# Generated by FakeRAM 2.0
VERSION 5.7 ;
BUSBITCHARS "[]" ;
PROPERTYDEFINITIONS
  MACRO width INTEGER ;
  MACRO depth INTEGER ;
  MACRO banks INTEGER ;
END PROPERTYDEFINITIONS
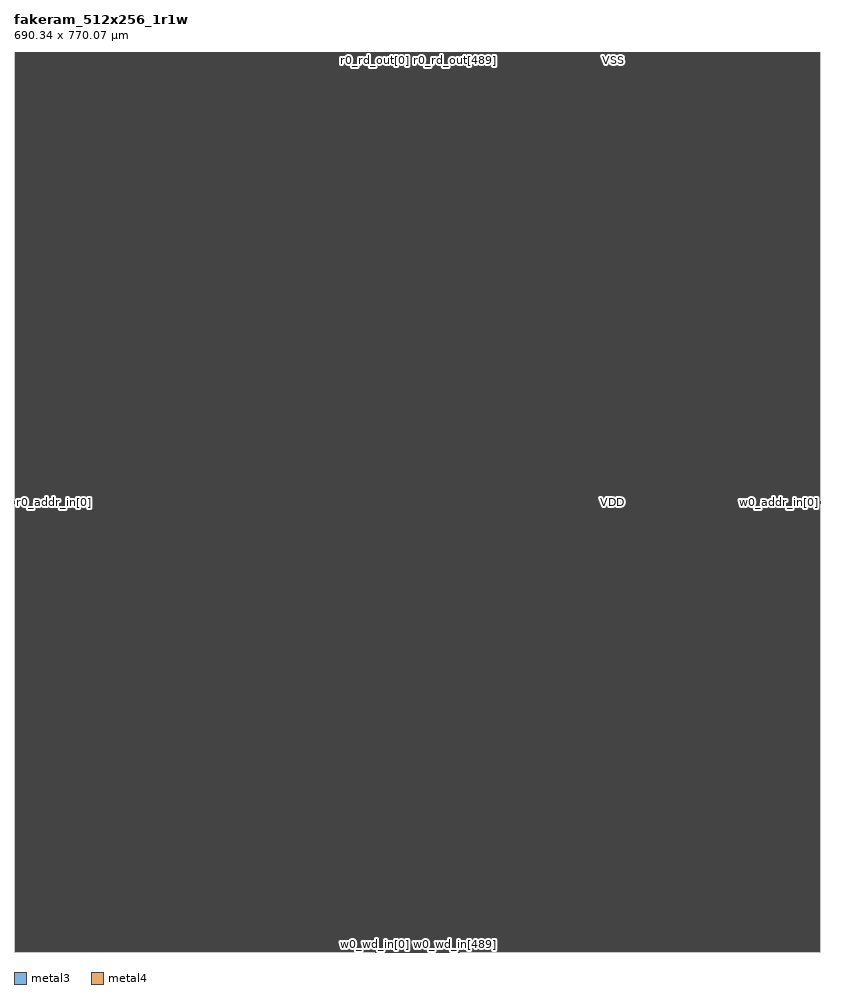
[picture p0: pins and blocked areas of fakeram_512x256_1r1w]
MACRO fakeram_512x256_1r1w
  PROPERTY width 512 ;
  PROPERTY depth 256 ;
  PROPERTY banks 1 ;
  FOREIGN fakeram_512x256_1r1w 0 0 ;
  SYMMETRY X Y R90 ;
  SIZE 690.340 BY 770.070 ;
  CLASS BLOCK ;
  PIN r0_addr_in[0]
    DIRECTION INPUT ;
    USE SIGNAL ;
    SHAPE ABUTMENT ;
    PORT
      LAYER metal3 ;
      RECT 0.000 384.160 0.070 384.230 ;
    END
  END r0_addr_in[0]
  PIN r0_addr_in[1]
    DIRECTION INPUT ;
    USE SIGNAL ;
    SHAPE ABUTMENT ;
    PORT
      LAYER metal3 ;
      RECT 0.000 384.300 0.070 384.370 ;
    END
  END r0_addr_in[1]
  PIN r0_addr_in[2]
    DIRECTION INPUT ;
    USE SIGNAL ;
    SHAPE ABUTMENT ;
    PORT
      LAYER metal3 ;
      RECT 0.000 384.440 0.070 384.510 ;
    END
  END r0_addr_in[2]
  PIN r0_addr_in[3]
    DIRECTION INPUT ;
    USE SIGNAL ;
    SHAPE ABUTMENT ;
    PORT
      LAYER metal3 ;
      RECT 0.000 384.580 0.070 384.650 ;
    END
  END r0_addr_in[3]
  PIN r0_addr_in[4]
    DIRECTION INPUT ;
    USE SIGNAL ;
    SHAPE ABUTMENT ;
    PORT
      LAYER metal3 ;
      RECT 0.000 384.720 0.070 384.790 ;
    END
  END r0_addr_in[4]
  PIN r0_addr_in[5]
    DIRECTION INPUT ;
    USE SIGNAL ;
    SHAPE ABUTMENT ;
    PORT
      LAYER metal3 ;
      RECT 0.000 384.860 0.070 384.930 ;
    END
  END r0_addr_in[5]
  PIN r0_addr_in[6]
    DIRECTION INPUT ;
    USE SIGNAL ;
    SHAPE ABUTMENT ;
    PORT
      LAYER metal3 ;
      RECT 0.000 385.000 0.070 385.070 ;
    END
  END r0_addr_in[6]
  PIN r0_addr_in[7]
    DIRECTION INPUT ;
    USE SIGNAL ;
    SHAPE ABUTMENT ;
    PORT
      LAYER metal3 ;
      RECT 0.000 385.140 0.070 385.210 ;
    END
  END r0_addr_in[7]
  PIN r0_ce_in
    DIRECTION INPUT ;
    USE SIGNAL ;
    SHAPE ABUTMENT ;
    PORT
      LAYER metal3 ;
      RECT 0.000 385.420 0.070 385.490 ;
    END
  END r0_ce_in
  PIN r0_clk
    DIRECTION INPUT ;
    USE SIGNAL ;
    SHAPE ABUTMENT ;
    PORT
      LAYER metal3 ;
      RECT 0.000 385.560 0.070 385.630 ;
    END
  END r0_clk
  PIN r0_rd_out[0]
    DIRECTION OUTPUT ;
    USE SIGNAL ;
    SHAPE ABUTMENT ;
    PORT
      LAYER metal3 ;
      RECT 309.225 770.000 309.295 770.070 ;
    END
  END r0_rd_out[0]
  PIN r0_rd_out[1]
    DIRECTION OUTPUT ;
    USE SIGNAL ;
    SHAPE ABUTMENT ;
    PORT
      LAYER metal3 ;
      RECT 309.365 770.000 309.435 770.070 ;
    END
  END r0_rd_out[1]
  PIN r0_rd_out[2]
    DIRECTION OUTPUT ;
    USE SIGNAL ;
    SHAPE ABUTMENT ;
    PORT
      LAYER metal3 ;
      RECT 309.505 770.000 309.575 770.070 ;
    END
  END r0_rd_out[2]
  PIN r0_rd_out[3]
    DIRECTION OUTPUT ;
    USE SIGNAL ;
    SHAPE ABUTMENT ;
    PORT
      LAYER metal3 ;
      RECT 309.645 770.000 309.715 770.070 ;
    END
  END r0_rd_out[3]
  PIN r0_rd_out[4]
    DIRECTION OUTPUT ;
    USE SIGNAL ;
    SHAPE ABUTMENT ;
    PORT
      LAYER metal3 ;
      RECT 309.785 770.000 309.855 770.070 ;
    END
  END r0_rd_out[4]
  PIN r0_rd_out[5]
    DIRECTION OUTPUT ;
    USE SIGNAL ;
    SHAPE ABUTMENT ;
    PORT
      LAYER metal3 ;
      RECT 309.925 770.000 309.995 770.070 ;
    END
  END r0_rd_out[5]
  PIN r0_rd_out[6]
    DIRECTION OUTPUT ;
    USE SIGNAL ;
    SHAPE ABUTMENT ;
    PORT
      LAYER metal3 ;
      RECT 310.065 770.000 310.135 770.070 ;
    END
  END r0_rd_out[6]
  PIN r0_rd_out[7]
    DIRECTION OUTPUT ;
    USE SIGNAL ;
    SHAPE ABUTMENT ;
    PORT
      LAYER metal3 ;
      RECT 310.205 770.000 310.275 770.070 ;
    END
  END r0_rd_out[7]
  PIN r0_rd_out[8]
    DIRECTION OUTPUT ;
    USE SIGNAL ;
    SHAPE ABUTMENT ;
    PORT
      LAYER metal3 ;
      RECT 310.345 770.000 310.415 770.070 ;
    END
  END r0_rd_out[8]
  PIN r0_rd_out[9]
    DIRECTION OUTPUT ;
    USE SIGNAL ;
    SHAPE ABUTMENT ;
    PORT
      LAYER metal3 ;
      RECT 310.485 770.000 310.555 770.070 ;
    END
  END r0_rd_out[9]
  PIN r0_rd_out[10]
    DIRECTION OUTPUT ;
    USE SIGNAL ;
    SHAPE ABUTMENT ;
    PORT
      LAYER metal3 ;
      RECT 310.625 770.000 310.695 770.070 ;
    END
  END r0_rd_out[10]
  PIN r0_rd_out[11]
    DIRECTION OUTPUT ;
    USE SIGNAL ;
    SHAPE ABUTMENT ;
    PORT
      LAYER metal3 ;
      RECT 310.765 770.000 310.835 770.070 ;
    END
  END r0_rd_out[11]
  PIN r0_rd_out[12]
    DIRECTION OUTPUT ;
    USE SIGNAL ;
    SHAPE ABUTMENT ;
    PORT
      LAYER metal3 ;
      RECT 310.905 770.000 310.975 770.070 ;
    END
  END r0_rd_out[12]
  PIN r0_rd_out[13]
    DIRECTION OUTPUT ;
    USE SIGNAL ;
    SHAPE ABUTMENT ;
    PORT
      LAYER metal3 ;
      RECT 311.045 770.000 311.115 770.070 ;
    END
  END r0_rd_out[13]
  PIN r0_rd_out[14]
    DIRECTION OUTPUT ;
    USE SIGNAL ;
    SHAPE ABUTMENT ;
    PORT
      LAYER metal3 ;
      RECT 311.185 770.000 311.255 770.070 ;
    END
  END r0_rd_out[14]
  PIN r0_rd_out[15]
    DIRECTION OUTPUT ;
    USE SIGNAL ;
    SHAPE ABUTMENT ;
    PORT
      LAYER metal3 ;
      RECT 311.325 770.000 311.395 770.070 ;
    END
  END r0_rd_out[15]
  PIN r0_rd_out[16]
    DIRECTION OUTPUT ;
    USE SIGNAL ;
    SHAPE ABUTMENT ;
    PORT
      LAYER metal3 ;
      RECT 311.465 770.000 311.535 770.070 ;
    END
  END r0_rd_out[16]
  PIN r0_rd_out[17]
    DIRECTION OUTPUT ;
    USE SIGNAL ;
    SHAPE ABUTMENT ;
    PORT
      LAYER metal3 ;
      RECT 311.605 770.000 311.675 770.070 ;
    END
  END r0_rd_out[17]
  PIN r0_rd_out[18]
    DIRECTION OUTPUT ;
    USE SIGNAL ;
    SHAPE ABUTMENT ;
    PORT
      LAYER metal3 ;
      RECT 311.745 770.000 311.815 770.070 ;
    END
  END r0_rd_out[18]
  PIN r0_rd_out[19]
    DIRECTION OUTPUT ;
    USE SIGNAL ;
    SHAPE ABUTMENT ;
    PORT
      LAYER metal3 ;
      RECT 311.885 770.000 311.955 770.070 ;
    END
  END r0_rd_out[19]
  PIN r0_rd_out[20]
    DIRECTION OUTPUT ;
    USE SIGNAL ;
    SHAPE ABUTMENT ;
    PORT
      LAYER metal3 ;
      RECT 312.025 770.000 312.095 770.070 ;
    END
  END r0_rd_out[20]
  PIN r0_rd_out[21]
    DIRECTION OUTPUT ;
    USE SIGNAL ;
    SHAPE ABUTMENT ;
    PORT
      LAYER metal3 ;
      RECT 312.165 770.000 312.235 770.070 ;
    END
  END r0_rd_out[21]
  PIN r0_rd_out[22]
    DIRECTION OUTPUT ;
    USE SIGNAL ;
    SHAPE ABUTMENT ;
    PORT
      LAYER metal3 ;
      RECT 312.305 770.000 312.375 770.070 ;
    END
  END r0_rd_out[22]
  PIN r0_rd_out[23]
    DIRECTION OUTPUT ;
    USE SIGNAL ;
    SHAPE ABUTMENT ;
    PORT
      LAYER metal3 ;
      RECT 312.445 770.000 312.515 770.070 ;
    END
  END r0_rd_out[23]
  PIN r0_rd_out[24]
    DIRECTION OUTPUT ;
    USE SIGNAL ;
    SHAPE ABUTMENT ;
    PORT
      LAYER metal3 ;
      RECT 312.585 770.000 312.655 770.070 ;
    END
  END r0_rd_out[24]
  PIN r0_rd_out[25]
    DIRECTION OUTPUT ;
    USE SIGNAL ;
    SHAPE ABUTMENT ;
    PORT
      LAYER metal3 ;
      RECT 312.725 770.000 312.795 770.070 ;
    END
  END r0_rd_out[25]
  PIN r0_rd_out[26]
    DIRECTION OUTPUT ;
    USE SIGNAL ;
    SHAPE ABUTMENT ;
    PORT
      LAYER metal3 ;
      RECT 312.865 770.000 312.935 770.070 ;
    END
  END r0_rd_out[26]
  PIN r0_rd_out[27]
    DIRECTION OUTPUT ;
    USE SIGNAL ;
    SHAPE ABUTMENT ;
    PORT
      LAYER metal3 ;
      RECT 313.005 770.000 313.075 770.070 ;
    END
  END r0_rd_out[27]
  PIN r0_rd_out[28]
    DIRECTION OUTPUT ;
    USE SIGNAL ;
    SHAPE ABUTMENT ;
    PORT
      LAYER metal3 ;
      RECT 313.145 770.000 313.215 770.070 ;
    END
  END r0_rd_out[28]
  PIN r0_rd_out[29]
    DIRECTION OUTPUT ;
    USE SIGNAL ;
    SHAPE ABUTMENT ;
    PORT
      LAYER metal3 ;
      RECT 313.285 770.000 313.355 770.070 ;
    END
  END r0_rd_out[29]
  PIN r0_rd_out[30]
    DIRECTION OUTPUT ;
    USE SIGNAL ;
    SHAPE ABUTMENT ;
    PORT
      LAYER metal3 ;
      RECT 313.425 770.000 313.495 770.070 ;
    END
  END r0_rd_out[30]
  PIN r0_rd_out[31]
    DIRECTION OUTPUT ;
    USE SIGNAL ;
    SHAPE ABUTMENT ;
    PORT
      LAYER metal3 ;
      RECT 313.565 770.000 313.635 770.070 ;
    END
  END r0_rd_out[31]
  PIN r0_rd_out[32]
    DIRECTION OUTPUT ;
    USE SIGNAL ;
    SHAPE ABUTMENT ;
    PORT
      LAYER metal3 ;
      RECT 313.705 770.000 313.775 770.070 ;
    END
  END r0_rd_out[32]
  PIN r0_rd_out[33]
    DIRECTION OUTPUT ;
    USE SIGNAL ;
    SHAPE ABUTMENT ;
    PORT
      LAYER metal3 ;
      RECT 313.845 770.000 313.915 770.070 ;
    END
  END r0_rd_out[33]
  PIN r0_rd_out[34]
    DIRECTION OUTPUT ;
    USE SIGNAL ;
    SHAPE ABUTMENT ;
    PORT
      LAYER metal3 ;
      RECT 313.985 770.000 314.055 770.070 ;
    END
  END r0_rd_out[34]
  PIN r0_rd_out[35]
    DIRECTION OUTPUT ;
    USE SIGNAL ;
    SHAPE ABUTMENT ;
    PORT
      LAYER metal3 ;
      RECT 314.125 770.000 314.195 770.070 ;
    END
  END r0_rd_out[35]
  PIN r0_rd_out[36]
    DIRECTION OUTPUT ;
    USE SIGNAL ;
    SHAPE ABUTMENT ;
    PORT
      LAYER metal3 ;
      RECT 314.265 770.000 314.335 770.070 ;
    END
  END r0_rd_out[36]
  PIN r0_rd_out[37]
    DIRECTION OUTPUT ;
    USE SIGNAL ;
    SHAPE ABUTMENT ;
    PORT
      LAYER metal3 ;
      RECT 314.405 770.000 314.475 770.070 ;
    END
  END r0_rd_out[37]
  PIN r0_rd_out[38]
    DIRECTION OUTPUT ;
    USE SIGNAL ;
    SHAPE ABUTMENT ;
    PORT
      LAYER metal3 ;
      RECT 314.545 770.000 314.615 770.070 ;
    END
  END r0_rd_out[38]
  PIN r0_rd_out[39]
    DIRECTION OUTPUT ;
    USE SIGNAL ;
    SHAPE ABUTMENT ;
    PORT
      LAYER metal3 ;
      RECT 314.685 770.000 314.755 770.070 ;
    END
  END r0_rd_out[39]
  PIN r0_rd_out[40]
    DIRECTION OUTPUT ;
    USE SIGNAL ;
    SHAPE ABUTMENT ;
    PORT
      LAYER metal3 ;
      RECT 314.825 770.000 314.895 770.070 ;
    END
  END r0_rd_out[40]
  PIN r0_rd_out[41]
    DIRECTION OUTPUT ;
    USE SIGNAL ;
    SHAPE ABUTMENT ;
    PORT
      LAYER metal3 ;
      RECT 314.965 770.000 315.035 770.070 ;
    END
  END r0_rd_out[41]
  PIN r0_rd_out[42]
    DIRECTION OUTPUT ;
    USE SIGNAL ;
    SHAPE ABUTMENT ;
    PORT
      LAYER metal3 ;
      RECT 315.105 770.000 315.175 770.070 ;
    END
  END r0_rd_out[42]
  PIN r0_rd_out[43]
    DIRECTION OUTPUT ;
    USE SIGNAL ;
    SHAPE ABUTMENT ;
    PORT
      LAYER metal3 ;
      RECT 315.245 770.000 315.315 770.070 ;
    END
  END r0_rd_out[43]
  PIN r0_rd_out[44]
    DIRECTION OUTPUT ;
    USE SIGNAL ;
    SHAPE ABUTMENT ;
    PORT
      LAYER metal3 ;
      RECT 315.385 770.000 315.455 770.070 ;
    END
  END r0_rd_out[44]
  PIN r0_rd_out[45]
    DIRECTION OUTPUT ;
    USE SIGNAL ;
    SHAPE ABUTMENT ;
    PORT
      LAYER metal3 ;
      RECT 315.525 770.000 315.595 770.070 ;
    END
  END r0_rd_out[45]
  PIN r0_rd_out[46]
    DIRECTION OUTPUT ;
    USE SIGNAL ;
    SHAPE ABUTMENT ;
    PORT
      LAYER metal3 ;
      RECT 315.665 770.000 315.735 770.070 ;
    END
  END r0_rd_out[46]
  PIN r0_rd_out[47]
    DIRECTION OUTPUT ;
    USE SIGNAL ;
    SHAPE ABUTMENT ;
    PORT
      LAYER metal3 ;
      RECT 315.805 770.000 315.875 770.070 ;
    END
  END r0_rd_out[47]
  PIN r0_rd_out[48]
    DIRECTION OUTPUT ;
    USE SIGNAL ;
    SHAPE ABUTMENT ;
    PORT
      LAYER metal3 ;
      RECT 315.945 770.000 316.015 770.070 ;
    END
  END r0_rd_out[48]
  PIN r0_rd_out[49]
    DIRECTION OUTPUT ;
    USE SIGNAL ;
    SHAPE ABUTMENT ;
    PORT
      LAYER metal3 ;
      RECT 316.085 770.000 316.155 770.070 ;
    END
  END r0_rd_out[49]
  PIN r0_rd_out[50]
    DIRECTION OUTPUT ;
    USE SIGNAL ;
    SHAPE ABUTMENT ;
    PORT
      LAYER metal3 ;
      RECT 316.225 770.000 316.295 770.070 ;
    END
  END r0_rd_out[50]
  PIN r0_rd_out[51]
    DIRECTION OUTPUT ;
    USE SIGNAL ;
    SHAPE ABUTMENT ;
    PORT
      LAYER metal3 ;
      RECT 316.365 770.000 316.435 770.070 ;
    END
  END r0_rd_out[51]
  PIN r0_rd_out[52]
    DIRECTION OUTPUT ;
    USE SIGNAL ;
    SHAPE ABUTMENT ;
    PORT
      LAYER metal3 ;
      RECT 316.505 770.000 316.575 770.070 ;
    END
  END r0_rd_out[52]
  PIN r0_rd_out[53]
    DIRECTION OUTPUT ;
    USE SIGNAL ;
    SHAPE ABUTMENT ;
    PORT
      LAYER metal3 ;
      RECT 316.645 770.000 316.715 770.070 ;
    END
  END r0_rd_out[53]
  PIN r0_rd_out[54]
    DIRECTION OUTPUT ;
    USE SIGNAL ;
    SHAPE ABUTMENT ;
    PORT
      LAYER metal3 ;
      RECT 316.785 770.000 316.855 770.070 ;
    END
  END r0_rd_out[54]
  PIN r0_rd_out[55]
    DIRECTION OUTPUT ;
    USE SIGNAL ;
    SHAPE ABUTMENT ;
    PORT
      LAYER metal3 ;
      RECT 316.925 770.000 316.995 770.070 ;
    END
  END r0_rd_out[55]
  PIN r0_rd_out[56]
    DIRECTION OUTPUT ;
    USE SIGNAL ;
    SHAPE ABUTMENT ;
    PORT
      LAYER metal3 ;
      RECT 317.065 770.000 317.135 770.070 ;
    END
  END r0_rd_out[56]
  PIN r0_rd_out[57]
    DIRECTION OUTPUT ;
    USE SIGNAL ;
    SHAPE ABUTMENT ;
    PORT
      LAYER metal3 ;
      RECT 317.205 770.000 317.275 770.070 ;
    END
  END r0_rd_out[57]
  PIN r0_rd_out[58]
    DIRECTION OUTPUT ;
    USE SIGNAL ;
    SHAPE ABUTMENT ;
    PORT
      LAYER metal3 ;
      RECT 317.345 770.000 317.415 770.070 ;
    END
  END r0_rd_out[58]
  PIN r0_rd_out[59]
    DIRECTION OUTPUT ;
    USE SIGNAL ;
    SHAPE ABUTMENT ;
    PORT
      LAYER metal3 ;
      RECT 317.485 770.000 317.555 770.070 ;
    END
  END r0_rd_out[59]
  PIN r0_rd_out[60]
    DIRECTION OUTPUT ;
    USE SIGNAL ;
    SHAPE ABUTMENT ;
    PORT
      LAYER metal3 ;
      RECT 317.625 770.000 317.695 770.070 ;
    END
  END r0_rd_out[60]
  PIN r0_rd_out[61]
    DIRECTION OUTPUT ;
    USE SIGNAL ;
    SHAPE ABUTMENT ;
    PORT
      LAYER metal3 ;
      RECT 317.765 770.000 317.835 770.070 ;
    END
  END r0_rd_out[61]
  PIN r0_rd_out[62]
    DIRECTION OUTPUT ;
    USE SIGNAL ;
    SHAPE ABUTMENT ;
    PORT
      LAYER metal3 ;
      RECT 317.905 770.000 317.975 770.070 ;
    END
  END r0_rd_out[62]
  PIN r0_rd_out[63]
    DIRECTION OUTPUT ;
    USE SIGNAL ;
    SHAPE ABUTMENT ;
    PORT
      LAYER metal3 ;
      RECT 318.045 770.000 318.115 770.070 ;
    END
  END r0_rd_out[63]
  PIN r0_rd_out[64]
    DIRECTION OUTPUT ;
    USE SIGNAL ;
    SHAPE ABUTMENT ;
    PORT
      LAYER metal3 ;
      RECT 318.185 770.000 318.255 770.070 ;
    END
  END r0_rd_out[64]
  PIN r0_rd_out[65]
    DIRECTION OUTPUT ;
    USE SIGNAL ;
    SHAPE ABUTMENT ;
    PORT
      LAYER metal3 ;
      RECT 318.325 770.000 318.395 770.070 ;
    END
  END r0_rd_out[65]
  PIN r0_rd_out[66]
    DIRECTION OUTPUT ;
    USE SIGNAL ;
    SHAPE ABUTMENT ;
    PORT
      LAYER metal3 ;
      RECT 318.465 770.000 318.535 770.070 ;
    END
  END r0_rd_out[66]
  PIN r0_rd_out[67]
    DIRECTION OUTPUT ;
    USE SIGNAL ;
    SHAPE ABUTMENT ;
    PORT
      LAYER metal3 ;
      RECT 318.605 770.000 318.675 770.070 ;
    END
  END r0_rd_out[67]
  PIN r0_rd_out[68]
    DIRECTION OUTPUT ;
    USE SIGNAL ;
    SHAPE ABUTMENT ;
    PORT
      LAYER metal3 ;
      RECT 318.745 770.000 318.815 770.070 ;
    END
  END r0_rd_out[68]
  PIN r0_rd_out[69]
    DIRECTION OUTPUT ;
    USE SIGNAL ;
    SHAPE ABUTMENT ;
    PORT
      LAYER metal3 ;
      RECT 318.885 770.000 318.955 770.070 ;
    END
  END r0_rd_out[69]
  PIN r0_rd_out[70]
    DIRECTION OUTPUT ;
    USE SIGNAL ;
    SHAPE ABUTMENT ;
    PORT
      LAYER metal3 ;
      RECT 319.025 770.000 319.095 770.070 ;
    END
  END r0_rd_out[70]
  PIN r0_rd_out[71]
    DIRECTION OUTPUT ;
    USE SIGNAL ;
    SHAPE ABUTMENT ;
    PORT
      LAYER metal3 ;
      RECT 319.165 770.000 319.235 770.070 ;
    END
  END r0_rd_out[71]
  PIN r0_rd_out[72]
    DIRECTION OUTPUT ;
    USE SIGNAL ;
    SHAPE ABUTMENT ;
    PORT
      LAYER metal3 ;
      RECT 319.305 770.000 319.375 770.070 ;
    END
  END r0_rd_out[72]
  PIN r0_rd_out[73]
    DIRECTION OUTPUT ;
    USE SIGNAL ;
    SHAPE ABUTMENT ;
    PORT
      LAYER metal3 ;
      RECT 319.445 770.000 319.515 770.070 ;
    END
  END r0_rd_out[73]
  PIN r0_rd_out[74]
    DIRECTION OUTPUT ;
    USE SIGNAL ;
    SHAPE ABUTMENT ;
    PORT
      LAYER metal3 ;
      RECT 319.585 770.000 319.655 770.070 ;
    END
  END r0_rd_out[74]
  PIN r0_rd_out[75]
    DIRECTION OUTPUT ;
    USE SIGNAL ;
    SHAPE ABUTMENT ;
    PORT
      LAYER metal3 ;
      RECT 319.725 770.000 319.795 770.070 ;
    END
  END r0_rd_out[75]
  PIN r0_rd_out[76]
    DIRECTION OUTPUT ;
    USE SIGNAL ;
    SHAPE ABUTMENT ;
    PORT
      LAYER metal3 ;
      RECT 319.865 770.000 319.935 770.070 ;
    END
  END r0_rd_out[76]
  PIN r0_rd_out[77]
    DIRECTION OUTPUT ;
    USE SIGNAL ;
    SHAPE ABUTMENT ;
    PORT
      LAYER metal3 ;
      RECT 320.005 770.000 320.075 770.070 ;
    END
  END r0_rd_out[77]
  PIN r0_rd_out[78]
    DIRECTION OUTPUT ;
    USE SIGNAL ;
    SHAPE ABUTMENT ;
    PORT
      LAYER metal3 ;
      RECT 320.145 770.000 320.215 770.070 ;
    END
  END r0_rd_out[78]
  PIN r0_rd_out[79]
    DIRECTION OUTPUT ;
    USE SIGNAL ;
    SHAPE ABUTMENT ;
    PORT
      LAYER metal3 ;
      RECT 320.285 770.000 320.355 770.070 ;
    END
  END r0_rd_out[79]
  PIN r0_rd_out[80]
    DIRECTION OUTPUT ;
    USE SIGNAL ;
    SHAPE ABUTMENT ;
    PORT
      LAYER metal3 ;
      RECT 320.425 770.000 320.495 770.070 ;
    END
  END r0_rd_out[80]
  PIN r0_rd_out[81]
    DIRECTION OUTPUT ;
    USE SIGNAL ;
    SHAPE ABUTMENT ;
    PORT
      LAYER metal3 ;
      RECT 320.565 770.000 320.635 770.070 ;
    END
  END r0_rd_out[81]
  PIN r0_rd_out[82]
    DIRECTION OUTPUT ;
    USE SIGNAL ;
    SHAPE ABUTMENT ;
    PORT
      LAYER metal3 ;
      RECT 320.705 770.000 320.775 770.070 ;
    END
  END r0_rd_out[82]
  PIN r0_rd_out[83]
    DIRECTION OUTPUT ;
    USE SIGNAL ;
    SHAPE ABUTMENT ;
    PORT
      LAYER metal3 ;
      RECT 320.845 770.000 320.915 770.070 ;
    END
  END r0_rd_out[83]
  PIN r0_rd_out[84]
    DIRECTION OUTPUT ;
    USE SIGNAL ;
    SHAPE ABUTMENT ;
    PORT
      LAYER metal3 ;
      RECT 320.985 770.000 321.055 770.070 ;
    END
  END r0_rd_out[84]
  PIN r0_rd_out[85]
    DIRECTION OUTPUT ;
    USE SIGNAL ;
    SHAPE ABUTMENT ;
    PORT
      LAYER metal3 ;
      RECT 321.125 770.000 321.195 770.070 ;
    END
  END r0_rd_out[85]
  PIN r0_rd_out[86]
    DIRECTION OUTPUT ;
    USE SIGNAL ;
    SHAPE ABUTMENT ;
    PORT
      LAYER metal3 ;
      RECT 321.265 770.000 321.335 770.070 ;
    END
  END r0_rd_out[86]
  PIN r0_rd_out[87]
    DIRECTION OUTPUT ;
    USE SIGNAL ;
    SHAPE ABUTMENT ;
    PORT
      LAYER metal3 ;
      RECT 321.405 770.000 321.475 770.070 ;
    END
  END r0_rd_out[87]
  PIN r0_rd_out[88]
    DIRECTION OUTPUT ;
    USE SIGNAL ;
    SHAPE ABUTMENT ;
    PORT
      LAYER metal3 ;
      RECT 321.545 770.000 321.615 770.070 ;
    END
  END r0_rd_out[88]
  PIN r0_rd_out[89]
    DIRECTION OUTPUT ;
    USE SIGNAL ;
    SHAPE ABUTMENT ;
    PORT
      LAYER metal3 ;
      RECT 321.685 770.000 321.755 770.070 ;
    END
  END r0_rd_out[89]
  PIN r0_rd_out[90]
    DIRECTION OUTPUT ;
    USE SIGNAL ;
    SHAPE ABUTMENT ;
    PORT
      LAYER metal3 ;
      RECT 321.825 770.000 321.895 770.070 ;
    END
  END r0_rd_out[90]
  PIN r0_rd_out[91]
    DIRECTION OUTPUT ;
    USE SIGNAL ;
    SHAPE ABUTMENT ;
    PORT
      LAYER metal3 ;
      RECT 321.965 770.000 322.035 770.070 ;
    END
  END r0_rd_out[91]
  PIN r0_rd_out[92]
    DIRECTION OUTPUT ;
    USE SIGNAL ;
    SHAPE ABUTMENT ;
    PORT
      LAYER metal3 ;
      RECT 322.105 770.000 322.175 770.070 ;
    END
  END r0_rd_out[92]
  PIN r0_rd_out[93]
    DIRECTION OUTPUT ;
    USE SIGNAL ;
    SHAPE ABUTMENT ;
    PORT
      LAYER metal3 ;
      RECT 322.245 770.000 322.315 770.070 ;
    END
  END r0_rd_out[93]
  PIN r0_rd_out[94]
    DIRECTION OUTPUT ;
    USE SIGNAL ;
    SHAPE ABUTMENT ;
    PORT
      LAYER metal3 ;
      RECT 322.385 770.000 322.455 770.070 ;
    END
  END r0_rd_out[94]
  PIN r0_rd_out[95]
    DIRECTION OUTPUT ;
    USE SIGNAL ;
    SHAPE ABUTMENT ;
    PORT
      LAYER metal3 ;
      RECT 322.525 770.000 322.595 770.070 ;
    END
  END r0_rd_out[95]
  PIN r0_rd_out[96]
    DIRECTION OUTPUT ;
    USE SIGNAL ;
    SHAPE ABUTMENT ;
    PORT
      LAYER metal3 ;
      RECT 322.665 770.000 322.735 770.070 ;
    END
  END r0_rd_out[96]
  PIN r0_rd_out[97]
    DIRECTION OUTPUT ;
    USE SIGNAL ;
    SHAPE ABUTMENT ;
    PORT
      LAYER metal3 ;
      RECT 322.805 770.000 322.875 770.070 ;
    END
  END r0_rd_out[97]
  PIN r0_rd_out[98]
    DIRECTION OUTPUT ;
    USE SIGNAL ;
    SHAPE ABUTMENT ;
    PORT
      LAYER metal3 ;
      RECT 322.945 770.000 323.015 770.070 ;
    END
  END r0_rd_out[98]
  PIN r0_rd_out[99]
    DIRECTION OUTPUT ;
    USE SIGNAL ;
    SHAPE ABUTMENT ;
    PORT
      LAYER metal3 ;
      RECT 323.085 770.000 323.155 770.070 ;
    END
  END r0_rd_out[99]
  PIN r0_rd_out[100]
    DIRECTION OUTPUT ;
    USE SIGNAL ;
    SHAPE ABUTMENT ;
    PORT
      LAYER metal3 ;
      RECT 323.225 770.000 323.295 770.070 ;
    END
  END r0_rd_out[100]
  PIN r0_rd_out[101]
    DIRECTION OUTPUT ;
    USE SIGNAL ;
    SHAPE ABUTMENT ;
    PORT
      LAYER metal3 ;
      RECT 323.365 770.000 323.435 770.070 ;
    END
  END r0_rd_out[101]
  PIN r0_rd_out[102]
    DIRECTION OUTPUT ;
    USE SIGNAL ;
    SHAPE ABUTMENT ;
    PORT
      LAYER metal3 ;
      RECT 323.505 770.000 323.575 770.070 ;
    END
  END r0_rd_out[102]
  PIN r0_rd_out[103]
    DIRECTION OUTPUT ;
    USE SIGNAL ;
    SHAPE ABUTMENT ;
    PORT
      LAYER metal3 ;
      RECT 323.645 770.000 323.715 770.070 ;
    END
  END r0_rd_out[103]
  PIN r0_rd_out[104]
    DIRECTION OUTPUT ;
    USE SIGNAL ;
    SHAPE ABUTMENT ;
    PORT
      LAYER metal3 ;
      RECT 323.785 770.000 323.855 770.070 ;
    END
  END r0_rd_out[104]
  PIN r0_rd_out[105]
    DIRECTION OUTPUT ;
    USE SIGNAL ;
    SHAPE ABUTMENT ;
    PORT
      LAYER metal3 ;
      RECT 323.925 770.000 323.995 770.070 ;
    END
  END r0_rd_out[105]
  PIN r0_rd_out[106]
    DIRECTION OUTPUT ;
    USE SIGNAL ;
    SHAPE ABUTMENT ;
    PORT
      LAYER metal3 ;
      RECT 324.065 770.000 324.135 770.070 ;
    END
  END r0_rd_out[106]
  PIN r0_rd_out[107]
    DIRECTION OUTPUT ;
    USE SIGNAL ;
    SHAPE ABUTMENT ;
    PORT
      LAYER metal3 ;
      RECT 324.205 770.000 324.275 770.070 ;
    END
  END r0_rd_out[107]
  PIN r0_rd_out[108]
    DIRECTION OUTPUT ;
    USE SIGNAL ;
    SHAPE ABUTMENT ;
    PORT
      LAYER metal3 ;
      RECT 324.345 770.000 324.415 770.070 ;
    END
  END r0_rd_out[108]
  PIN r0_rd_out[109]
    DIRECTION OUTPUT ;
    USE SIGNAL ;
    SHAPE ABUTMENT ;
    PORT
      LAYER metal3 ;
      RECT 324.485 770.000 324.555 770.070 ;
    END
  END r0_rd_out[109]
  PIN r0_rd_out[110]
    DIRECTION OUTPUT ;
    USE SIGNAL ;
    SHAPE ABUTMENT ;
    PORT
      LAYER metal3 ;
      RECT 324.625 770.000 324.695 770.070 ;
    END
  END r0_rd_out[110]
  PIN r0_rd_out[111]
    DIRECTION OUTPUT ;
    USE SIGNAL ;
    SHAPE ABUTMENT ;
    PORT
      LAYER metal3 ;
      RECT 324.765 770.000 324.835 770.070 ;
    END
  END r0_rd_out[111]
  PIN r0_rd_out[112]
    DIRECTION OUTPUT ;
    USE SIGNAL ;
    SHAPE ABUTMENT ;
    PORT
      LAYER metal3 ;
      RECT 324.905 770.000 324.975 770.070 ;
    END
  END r0_rd_out[112]
  PIN r0_rd_out[113]
    DIRECTION OUTPUT ;
    USE SIGNAL ;
    SHAPE ABUTMENT ;
    PORT
      LAYER metal3 ;
      RECT 325.045 770.000 325.115 770.070 ;
    END
  END r0_rd_out[113]
  PIN r0_rd_out[114]
    DIRECTION OUTPUT ;
    USE SIGNAL ;
    SHAPE ABUTMENT ;
    PORT
      LAYER metal3 ;
      RECT 325.185 770.000 325.255 770.070 ;
    END
  END r0_rd_out[114]
  PIN r0_rd_out[115]
    DIRECTION OUTPUT ;
    USE SIGNAL ;
    SHAPE ABUTMENT ;
    PORT
      LAYER metal3 ;
      RECT 325.325 770.000 325.395 770.070 ;
    END
  END r0_rd_out[115]
  PIN r0_rd_out[116]
    DIRECTION OUTPUT ;
    USE SIGNAL ;
    SHAPE ABUTMENT ;
    PORT
      LAYER metal3 ;
      RECT 325.465 770.000 325.535 770.070 ;
    END
  END r0_rd_out[116]
  PIN r0_rd_out[117]
    DIRECTION OUTPUT ;
    USE SIGNAL ;
    SHAPE ABUTMENT ;
    PORT
      LAYER metal3 ;
      RECT 325.605 770.000 325.675 770.070 ;
    END
  END r0_rd_out[117]
  PIN r0_rd_out[118]
    DIRECTION OUTPUT ;
    USE SIGNAL ;
    SHAPE ABUTMENT ;
    PORT
      LAYER metal3 ;
      RECT 325.745 770.000 325.815 770.070 ;
    END
  END r0_rd_out[118]
  PIN r0_rd_out[119]
    DIRECTION OUTPUT ;
    USE SIGNAL ;
    SHAPE ABUTMENT ;
    PORT
      LAYER metal3 ;
      RECT 325.885 770.000 325.955 770.070 ;
    END
  END r0_rd_out[119]
  PIN r0_rd_out[120]
    DIRECTION OUTPUT ;
    USE SIGNAL ;
    SHAPE ABUTMENT ;
    PORT
      LAYER metal3 ;
      RECT 326.025 770.000 326.095 770.070 ;
    END
  END r0_rd_out[120]
  PIN r0_rd_out[121]
    DIRECTION OUTPUT ;
    USE SIGNAL ;
    SHAPE ABUTMENT ;
    PORT
      LAYER metal3 ;
      RECT 326.165 770.000 326.235 770.070 ;
    END
  END r0_rd_out[121]
  PIN r0_rd_out[122]
    DIRECTION OUTPUT ;
    USE SIGNAL ;
    SHAPE ABUTMENT ;
    PORT
      LAYER metal3 ;
      RECT 326.305 770.000 326.375 770.070 ;
    END
  END r0_rd_out[122]
  PIN r0_rd_out[123]
    DIRECTION OUTPUT ;
    USE SIGNAL ;
    SHAPE ABUTMENT ;
    PORT
      LAYER metal3 ;
      RECT 326.445 770.000 326.515 770.070 ;
    END
  END r0_rd_out[123]
  PIN r0_rd_out[124]
    DIRECTION OUTPUT ;
    USE SIGNAL ;
    SHAPE ABUTMENT ;
    PORT
      LAYER metal3 ;
      RECT 326.585 770.000 326.655 770.070 ;
    END
  END r0_rd_out[124]
  PIN r0_rd_out[125]
    DIRECTION OUTPUT ;
    USE SIGNAL ;
    SHAPE ABUTMENT ;
    PORT
      LAYER metal3 ;
      RECT 326.725 770.000 326.795 770.070 ;
    END
  END r0_rd_out[125]
  PIN r0_rd_out[126]
    DIRECTION OUTPUT ;
    USE SIGNAL ;
    SHAPE ABUTMENT ;
    PORT
      LAYER metal3 ;
      RECT 326.865 770.000 326.935 770.070 ;
    END
  END r0_rd_out[126]
  PIN r0_rd_out[127]
    DIRECTION OUTPUT ;
    USE SIGNAL ;
    SHAPE ABUTMENT ;
    PORT
      LAYER metal3 ;
      RECT 327.005 770.000 327.075 770.070 ;
    END
  END r0_rd_out[127]
  PIN r0_rd_out[128]
    DIRECTION OUTPUT ;
    USE SIGNAL ;
    SHAPE ABUTMENT ;
    PORT
      LAYER metal3 ;
      RECT 327.145 770.000 327.215 770.070 ;
    END
  END r0_rd_out[128]
  PIN r0_rd_out[129]
    DIRECTION OUTPUT ;
    USE SIGNAL ;
    SHAPE ABUTMENT ;
    PORT
      LAYER metal3 ;
      RECT 327.285 770.000 327.355 770.070 ;
    END
  END r0_rd_out[129]
  PIN r0_rd_out[130]
    DIRECTION OUTPUT ;
    USE SIGNAL ;
    SHAPE ABUTMENT ;
    PORT
      LAYER metal3 ;
      RECT 327.425 770.000 327.495 770.070 ;
    END
  END r0_rd_out[130]
  PIN r0_rd_out[131]
    DIRECTION OUTPUT ;
    USE SIGNAL ;
    SHAPE ABUTMENT ;
    PORT
      LAYER metal3 ;
      RECT 327.565 770.000 327.635 770.070 ;
    END
  END r0_rd_out[131]
  PIN r0_rd_out[132]
    DIRECTION OUTPUT ;
    USE SIGNAL ;
    SHAPE ABUTMENT ;
    PORT
      LAYER metal3 ;
      RECT 327.705 770.000 327.775 770.070 ;
    END
  END r0_rd_out[132]
  PIN r0_rd_out[133]
    DIRECTION OUTPUT ;
    USE SIGNAL ;
    SHAPE ABUTMENT ;
    PORT
      LAYER metal3 ;
      RECT 327.845 770.000 327.915 770.070 ;
    END
  END r0_rd_out[133]
  PIN r0_rd_out[134]
    DIRECTION OUTPUT ;
    USE SIGNAL ;
    SHAPE ABUTMENT ;
    PORT
      LAYER metal3 ;
      RECT 327.985 770.000 328.055 770.070 ;
    END
  END r0_rd_out[134]
  PIN r0_rd_out[135]
    DIRECTION OUTPUT ;
    USE SIGNAL ;
    SHAPE ABUTMENT ;
    PORT
      LAYER metal3 ;
      RECT 328.125 770.000 328.195 770.070 ;
    END
  END r0_rd_out[135]
  PIN r0_rd_out[136]
    DIRECTION OUTPUT ;
    USE SIGNAL ;
    SHAPE ABUTMENT ;
    PORT
      LAYER metal3 ;
      RECT 328.265 770.000 328.335 770.070 ;
    END
  END r0_rd_out[136]
  PIN r0_rd_out[137]
    DIRECTION OUTPUT ;
    USE SIGNAL ;
    SHAPE ABUTMENT ;
    PORT
      LAYER metal3 ;
      RECT 328.405 770.000 328.475 770.070 ;
    END
  END r0_rd_out[137]
  PIN r0_rd_out[138]
    DIRECTION OUTPUT ;
    USE SIGNAL ;
    SHAPE ABUTMENT ;
    PORT
      LAYER metal3 ;
      RECT 328.545 770.000 328.615 770.070 ;
    END
  END r0_rd_out[138]
  PIN r0_rd_out[139]
    DIRECTION OUTPUT ;
    USE SIGNAL ;
    SHAPE ABUTMENT ;
    PORT
      LAYER metal3 ;
      RECT 328.685 770.000 328.755 770.070 ;
    END
  END r0_rd_out[139]
  PIN r0_rd_out[140]
    DIRECTION OUTPUT ;
    USE SIGNAL ;
    SHAPE ABUTMENT ;
    PORT
      LAYER metal3 ;
      RECT 328.825 770.000 328.895 770.070 ;
    END
  END r0_rd_out[140]
  PIN r0_rd_out[141]
    DIRECTION OUTPUT ;
    USE SIGNAL ;
    SHAPE ABUTMENT ;
    PORT
      LAYER metal3 ;
      RECT 328.965 770.000 329.035 770.070 ;
    END
  END r0_rd_out[141]
  PIN r0_rd_out[142]
    DIRECTION OUTPUT ;
    USE SIGNAL ;
    SHAPE ABUTMENT ;
    PORT
      LAYER metal3 ;
      RECT 329.105 770.000 329.175 770.070 ;
    END
  END r0_rd_out[142]
  PIN r0_rd_out[143]
    DIRECTION OUTPUT ;
    USE SIGNAL ;
    SHAPE ABUTMENT ;
    PORT
      LAYER metal3 ;
      RECT 329.245 770.000 329.315 770.070 ;
    END
  END r0_rd_out[143]
  PIN r0_rd_out[144]
    DIRECTION OUTPUT ;
    USE SIGNAL ;
    SHAPE ABUTMENT ;
    PORT
      LAYER metal3 ;
      RECT 329.385 770.000 329.455 770.070 ;
    END
  END r0_rd_out[144]
  PIN r0_rd_out[145]
    DIRECTION OUTPUT ;
    USE SIGNAL ;
    SHAPE ABUTMENT ;
    PORT
      LAYER metal3 ;
      RECT 329.525 770.000 329.595 770.070 ;
    END
  END r0_rd_out[145]
  PIN r0_rd_out[146]
    DIRECTION OUTPUT ;
    USE SIGNAL ;
    SHAPE ABUTMENT ;
    PORT
      LAYER metal3 ;
      RECT 329.665 770.000 329.735 770.070 ;
    END
  END r0_rd_out[146]
  PIN r0_rd_out[147]
    DIRECTION OUTPUT ;
    USE SIGNAL ;
    SHAPE ABUTMENT ;
    PORT
      LAYER metal3 ;
      RECT 329.805 770.000 329.875 770.070 ;
    END
  END r0_rd_out[147]
  PIN r0_rd_out[148]
    DIRECTION OUTPUT ;
    USE SIGNAL ;
    SHAPE ABUTMENT ;
    PORT
      LAYER metal3 ;
      RECT 329.945 770.000 330.015 770.070 ;
    END
  END r0_rd_out[148]
  PIN r0_rd_out[149]
    DIRECTION OUTPUT ;
    USE SIGNAL ;
    SHAPE ABUTMENT ;
    PORT
      LAYER metal3 ;
      RECT 330.085 770.000 330.155 770.070 ;
    END
  END r0_rd_out[149]
  PIN r0_rd_out[150]
    DIRECTION OUTPUT ;
    USE SIGNAL ;
    SHAPE ABUTMENT ;
    PORT
      LAYER metal3 ;
      RECT 330.225 770.000 330.295 770.070 ;
    END
  END r0_rd_out[150]
  PIN r0_rd_out[151]
    DIRECTION OUTPUT ;
    USE SIGNAL ;
    SHAPE ABUTMENT ;
    PORT
      LAYER metal3 ;
      RECT 330.365 770.000 330.435 770.070 ;
    END
  END r0_rd_out[151]
  PIN r0_rd_out[152]
    DIRECTION OUTPUT ;
    USE SIGNAL ;
    SHAPE ABUTMENT ;
    PORT
      LAYER metal3 ;
      RECT 330.505 770.000 330.575 770.070 ;
    END
  END r0_rd_out[152]
  PIN r0_rd_out[153]
    DIRECTION OUTPUT ;
    USE SIGNAL ;
    SHAPE ABUTMENT ;
    PORT
      LAYER metal3 ;
      RECT 330.645 770.000 330.715 770.070 ;
    END
  END r0_rd_out[153]
  PIN r0_rd_out[154]
    DIRECTION OUTPUT ;
    USE SIGNAL ;
    SHAPE ABUTMENT ;
    PORT
      LAYER metal3 ;
      RECT 330.785 770.000 330.855 770.070 ;
    END
  END r0_rd_out[154]
  PIN r0_rd_out[155]
    DIRECTION OUTPUT ;
    USE SIGNAL ;
    SHAPE ABUTMENT ;
    PORT
      LAYER metal3 ;
      RECT 330.925 770.000 330.995 770.070 ;
    END
  END r0_rd_out[155]
  PIN r0_rd_out[156]
    DIRECTION OUTPUT ;
    USE SIGNAL ;
    SHAPE ABUTMENT ;
    PORT
      LAYER metal3 ;
      RECT 331.065 770.000 331.135 770.070 ;
    END
  END r0_rd_out[156]
  PIN r0_rd_out[157]
    DIRECTION OUTPUT ;
    USE SIGNAL ;
    SHAPE ABUTMENT ;
    PORT
      LAYER metal3 ;
      RECT 331.205 770.000 331.275 770.070 ;
    END
  END r0_rd_out[157]
  PIN r0_rd_out[158]
    DIRECTION OUTPUT ;
    USE SIGNAL ;
    SHAPE ABUTMENT ;
    PORT
      LAYER metal3 ;
      RECT 331.345 770.000 331.415 770.070 ;
    END
  END r0_rd_out[158]
  PIN r0_rd_out[159]
    DIRECTION OUTPUT ;
    USE SIGNAL ;
    SHAPE ABUTMENT ;
    PORT
      LAYER metal3 ;
      RECT 331.485 770.000 331.555 770.070 ;
    END
  END r0_rd_out[159]
  PIN r0_rd_out[160]
    DIRECTION OUTPUT ;
    USE SIGNAL ;
    SHAPE ABUTMENT ;
    PORT
      LAYER metal3 ;
      RECT 331.625 770.000 331.695 770.070 ;
    END
  END r0_rd_out[160]
  PIN r0_rd_out[161]
    DIRECTION OUTPUT ;
    USE SIGNAL ;
    SHAPE ABUTMENT ;
    PORT
      LAYER metal3 ;
      RECT 331.765 770.000 331.835 770.070 ;
    END
  END r0_rd_out[161]
  PIN r0_rd_out[162]
    DIRECTION OUTPUT ;
    USE SIGNAL ;
    SHAPE ABUTMENT ;
    PORT
      LAYER metal3 ;
      RECT 331.905 770.000 331.975 770.070 ;
    END
  END r0_rd_out[162]
  PIN r0_rd_out[163]
    DIRECTION OUTPUT ;
    USE SIGNAL ;
    SHAPE ABUTMENT ;
    PORT
      LAYER metal3 ;
      RECT 332.045 770.000 332.115 770.070 ;
    END
  END r0_rd_out[163]
  PIN r0_rd_out[164]
    DIRECTION OUTPUT ;
    USE SIGNAL ;
    SHAPE ABUTMENT ;
    PORT
      LAYER metal3 ;
      RECT 332.185 770.000 332.255 770.070 ;
    END
  END r0_rd_out[164]
  PIN r0_rd_out[165]
    DIRECTION OUTPUT ;
    USE SIGNAL ;
    SHAPE ABUTMENT ;
    PORT
      LAYER metal3 ;
      RECT 332.325 770.000 332.395 770.070 ;
    END
  END r0_rd_out[165]
  PIN r0_rd_out[166]
    DIRECTION OUTPUT ;
    USE SIGNAL ;
    SHAPE ABUTMENT ;
    PORT
      LAYER metal3 ;
      RECT 332.465 770.000 332.535 770.070 ;
    END
  END r0_rd_out[166]
  PIN r0_rd_out[167]
    DIRECTION OUTPUT ;
    USE SIGNAL ;
    SHAPE ABUTMENT ;
    PORT
      LAYER metal3 ;
      RECT 332.605 770.000 332.675 770.070 ;
    END
  END r0_rd_out[167]
  PIN r0_rd_out[168]
    DIRECTION OUTPUT ;
    USE SIGNAL ;
    SHAPE ABUTMENT ;
    PORT
      LAYER metal3 ;
      RECT 332.745 770.000 332.815 770.070 ;
    END
  END r0_rd_out[168]
  PIN r0_rd_out[169]
    DIRECTION OUTPUT ;
    USE SIGNAL ;
    SHAPE ABUTMENT ;
    PORT
      LAYER metal3 ;
      RECT 332.885 770.000 332.955 770.070 ;
    END
  END r0_rd_out[169]
  PIN r0_rd_out[170]
    DIRECTION OUTPUT ;
    USE SIGNAL ;
    SHAPE ABUTMENT ;
    PORT
      LAYER metal3 ;
      RECT 333.025 770.000 333.095 770.070 ;
    END
  END r0_rd_out[170]
  PIN r0_rd_out[171]
    DIRECTION OUTPUT ;
    USE SIGNAL ;
    SHAPE ABUTMENT ;
    PORT
      LAYER metal3 ;
      RECT 333.165 770.000 333.235 770.070 ;
    END
  END r0_rd_out[171]
  PIN r0_rd_out[172]
    DIRECTION OUTPUT ;
    USE SIGNAL ;
    SHAPE ABUTMENT ;
    PORT
      LAYER metal3 ;
      RECT 333.305 770.000 333.375 770.070 ;
    END
  END r0_rd_out[172]
  PIN r0_rd_out[173]
    DIRECTION OUTPUT ;
    USE SIGNAL ;
    SHAPE ABUTMENT ;
    PORT
      LAYER metal3 ;
      RECT 333.445 770.000 333.515 770.070 ;
    END
  END r0_rd_out[173]
  PIN r0_rd_out[174]
    DIRECTION OUTPUT ;
    USE SIGNAL ;
    SHAPE ABUTMENT ;
    PORT
      LAYER metal3 ;
      RECT 333.585 770.000 333.655 770.070 ;
    END
  END r0_rd_out[174]
  PIN r0_rd_out[175]
    DIRECTION OUTPUT ;
    USE SIGNAL ;
    SHAPE ABUTMENT ;
    PORT
      LAYER metal3 ;
      RECT 333.725 770.000 333.795 770.070 ;
    END
  END r0_rd_out[175]
  PIN r0_rd_out[176]
    DIRECTION OUTPUT ;
    USE SIGNAL ;
    SHAPE ABUTMENT ;
    PORT
      LAYER metal3 ;
      RECT 333.865 770.000 333.935 770.070 ;
    END
  END r0_rd_out[176]
  PIN r0_rd_out[177]
    DIRECTION OUTPUT ;
    USE SIGNAL ;
    SHAPE ABUTMENT ;
    PORT
      LAYER metal3 ;
      RECT 334.005 770.000 334.075 770.070 ;
    END
  END r0_rd_out[177]
  PIN r0_rd_out[178]
    DIRECTION OUTPUT ;
    USE SIGNAL ;
    SHAPE ABUTMENT ;
    PORT
      LAYER metal3 ;
      RECT 334.145 770.000 334.215 770.070 ;
    END
  END r0_rd_out[178]
  PIN r0_rd_out[179]
    DIRECTION OUTPUT ;
    USE SIGNAL ;
    SHAPE ABUTMENT ;
    PORT
      LAYER metal3 ;
      RECT 334.285 770.000 334.355 770.070 ;
    END
  END r0_rd_out[179]
  PIN r0_rd_out[180]
    DIRECTION OUTPUT ;
    USE SIGNAL ;
    SHAPE ABUTMENT ;
    PORT
      LAYER metal3 ;
      RECT 334.425 770.000 334.495 770.070 ;
    END
  END r0_rd_out[180]
  PIN r0_rd_out[181]
    DIRECTION OUTPUT ;
    USE SIGNAL ;
    SHAPE ABUTMENT ;
    PORT
      LAYER metal3 ;
      RECT 334.565 770.000 334.635 770.070 ;
    END
  END r0_rd_out[181]
  PIN r0_rd_out[182]
    DIRECTION OUTPUT ;
    USE SIGNAL ;
    SHAPE ABUTMENT ;
    PORT
      LAYER metal3 ;
      RECT 334.705 770.000 334.775 770.070 ;
    END
  END r0_rd_out[182]
  PIN r0_rd_out[183]
    DIRECTION OUTPUT ;
    USE SIGNAL ;
    SHAPE ABUTMENT ;
    PORT
      LAYER metal3 ;
      RECT 334.845 770.000 334.915 770.070 ;
    END
  END r0_rd_out[183]
  PIN r0_rd_out[184]
    DIRECTION OUTPUT ;
    USE SIGNAL ;
    SHAPE ABUTMENT ;
    PORT
      LAYER metal3 ;
      RECT 334.985 770.000 335.055 770.070 ;
    END
  END r0_rd_out[184]
  PIN r0_rd_out[185]
    DIRECTION OUTPUT ;
    USE SIGNAL ;
    SHAPE ABUTMENT ;
    PORT
      LAYER metal3 ;
      RECT 335.125 770.000 335.195 770.070 ;
    END
  END r0_rd_out[185]
  PIN r0_rd_out[186]
    DIRECTION OUTPUT ;
    USE SIGNAL ;
    SHAPE ABUTMENT ;
    PORT
      LAYER metal3 ;
      RECT 335.265 770.000 335.335 770.070 ;
    END
  END r0_rd_out[186]
  PIN r0_rd_out[187]
    DIRECTION OUTPUT ;
    USE SIGNAL ;
    SHAPE ABUTMENT ;
    PORT
      LAYER metal3 ;
      RECT 335.405 770.000 335.475 770.070 ;
    END
  END r0_rd_out[187]
  PIN r0_rd_out[188]
    DIRECTION OUTPUT ;
    USE SIGNAL ;
    SHAPE ABUTMENT ;
    PORT
      LAYER metal3 ;
      RECT 335.545 770.000 335.615 770.070 ;
    END
  END r0_rd_out[188]
  PIN r0_rd_out[189]
    DIRECTION OUTPUT ;
    USE SIGNAL ;
    SHAPE ABUTMENT ;
    PORT
      LAYER metal3 ;
      RECT 335.685 770.000 335.755 770.070 ;
    END
  END r0_rd_out[189]
  PIN r0_rd_out[190]
    DIRECTION OUTPUT ;
    USE SIGNAL ;
    SHAPE ABUTMENT ;
    PORT
      LAYER metal3 ;
      RECT 335.825 770.000 335.895 770.070 ;
    END
  END r0_rd_out[190]
  PIN r0_rd_out[191]
    DIRECTION OUTPUT ;
    USE SIGNAL ;
    SHAPE ABUTMENT ;
    PORT
      LAYER metal3 ;
      RECT 335.965 770.000 336.035 770.070 ;
    END
  END r0_rd_out[191]
  PIN r0_rd_out[192]
    DIRECTION OUTPUT ;
    USE SIGNAL ;
    SHAPE ABUTMENT ;
    PORT
      LAYER metal3 ;
      RECT 336.105 770.000 336.175 770.070 ;
    END
  END r0_rd_out[192]
  PIN r0_rd_out[193]
    DIRECTION OUTPUT ;
    USE SIGNAL ;
    SHAPE ABUTMENT ;
    PORT
      LAYER metal3 ;
      RECT 336.245 770.000 336.315 770.070 ;
    END
  END r0_rd_out[193]
  PIN r0_rd_out[194]
    DIRECTION OUTPUT ;
    USE SIGNAL ;
    SHAPE ABUTMENT ;
    PORT
      LAYER metal3 ;
      RECT 336.385 770.000 336.455 770.070 ;
    END
  END r0_rd_out[194]
  PIN r0_rd_out[195]
    DIRECTION OUTPUT ;
    USE SIGNAL ;
    SHAPE ABUTMENT ;
    PORT
      LAYER metal3 ;
      RECT 336.525 770.000 336.595 770.070 ;
    END
  END r0_rd_out[195]
  PIN r0_rd_out[196]
    DIRECTION OUTPUT ;
    USE SIGNAL ;
    SHAPE ABUTMENT ;
    PORT
      LAYER metal3 ;
      RECT 336.665 770.000 336.735 770.070 ;
    END
  END r0_rd_out[196]
  PIN r0_rd_out[197]
    DIRECTION OUTPUT ;
    USE SIGNAL ;
    SHAPE ABUTMENT ;
    PORT
      LAYER metal3 ;
      RECT 336.805 770.000 336.875 770.070 ;
    END
  END r0_rd_out[197]
  PIN r0_rd_out[198]
    DIRECTION OUTPUT ;
    USE SIGNAL ;
    SHAPE ABUTMENT ;
    PORT
      LAYER metal3 ;
      RECT 336.945 770.000 337.015 770.070 ;
    END
  END r0_rd_out[198]
  PIN r0_rd_out[199]
    DIRECTION OUTPUT ;
    USE SIGNAL ;
    SHAPE ABUTMENT ;
    PORT
      LAYER metal3 ;
      RECT 337.085 770.000 337.155 770.070 ;
    END
  END r0_rd_out[199]
  PIN r0_rd_out[200]
    DIRECTION OUTPUT ;
    USE SIGNAL ;
    SHAPE ABUTMENT ;
    PORT
      LAYER metal3 ;
      RECT 337.225 770.000 337.295 770.070 ;
    END
  END r0_rd_out[200]
  PIN r0_rd_out[201]
    DIRECTION OUTPUT ;
    USE SIGNAL ;
    SHAPE ABUTMENT ;
    PORT
      LAYER metal3 ;
      RECT 337.365 770.000 337.435 770.070 ;
    END
  END r0_rd_out[201]
  PIN r0_rd_out[202]
    DIRECTION OUTPUT ;
    USE SIGNAL ;
    SHAPE ABUTMENT ;
    PORT
      LAYER metal3 ;
      RECT 337.505 770.000 337.575 770.070 ;
    END
  END r0_rd_out[202]
  PIN r0_rd_out[203]
    DIRECTION OUTPUT ;
    USE SIGNAL ;
    SHAPE ABUTMENT ;
    PORT
      LAYER metal3 ;
      RECT 337.645 770.000 337.715 770.070 ;
    END
  END r0_rd_out[203]
  PIN r0_rd_out[204]
    DIRECTION OUTPUT ;
    USE SIGNAL ;
    SHAPE ABUTMENT ;
    PORT
      LAYER metal3 ;
      RECT 337.785 770.000 337.855 770.070 ;
    END
  END r0_rd_out[204]
  PIN r0_rd_out[205]
    DIRECTION OUTPUT ;
    USE SIGNAL ;
    SHAPE ABUTMENT ;
    PORT
      LAYER metal3 ;
      RECT 337.925 770.000 337.995 770.070 ;
    END
  END r0_rd_out[205]
  PIN r0_rd_out[206]
    DIRECTION OUTPUT ;
    USE SIGNAL ;
    SHAPE ABUTMENT ;
    PORT
      LAYER metal3 ;
      RECT 338.065 770.000 338.135 770.070 ;
    END
  END r0_rd_out[206]
  PIN r0_rd_out[207]
    DIRECTION OUTPUT ;
    USE SIGNAL ;
    SHAPE ABUTMENT ;
    PORT
      LAYER metal3 ;
      RECT 338.205 770.000 338.275 770.070 ;
    END
  END r0_rd_out[207]
  PIN r0_rd_out[208]
    DIRECTION OUTPUT ;
    USE SIGNAL ;
    SHAPE ABUTMENT ;
    PORT
      LAYER metal3 ;
      RECT 338.345 770.000 338.415 770.070 ;
    END
  END r0_rd_out[208]
  PIN r0_rd_out[209]
    DIRECTION OUTPUT ;
    USE SIGNAL ;
    SHAPE ABUTMENT ;
    PORT
      LAYER metal3 ;
      RECT 338.485 770.000 338.555 770.070 ;
    END
  END r0_rd_out[209]
  PIN r0_rd_out[210]
    DIRECTION OUTPUT ;
    USE SIGNAL ;
    SHAPE ABUTMENT ;
    PORT
      LAYER metal3 ;
      RECT 338.625 770.000 338.695 770.070 ;
    END
  END r0_rd_out[210]
  PIN r0_rd_out[211]
    DIRECTION OUTPUT ;
    USE SIGNAL ;
    SHAPE ABUTMENT ;
    PORT
      LAYER metal3 ;
      RECT 338.765 770.000 338.835 770.070 ;
    END
  END r0_rd_out[211]
  PIN r0_rd_out[212]
    DIRECTION OUTPUT ;
    USE SIGNAL ;
    SHAPE ABUTMENT ;
    PORT
      LAYER metal3 ;
      RECT 338.905 770.000 338.975 770.070 ;
    END
  END r0_rd_out[212]
  PIN r0_rd_out[213]
    DIRECTION OUTPUT ;
    USE SIGNAL ;
    SHAPE ABUTMENT ;
    PORT
      LAYER metal3 ;
      RECT 339.045 770.000 339.115 770.070 ;
    END
  END r0_rd_out[213]
  PIN r0_rd_out[214]
    DIRECTION OUTPUT ;
    USE SIGNAL ;
    SHAPE ABUTMENT ;
    PORT
      LAYER metal3 ;
      RECT 339.185 770.000 339.255 770.070 ;
    END
  END r0_rd_out[214]
  PIN r0_rd_out[215]
    DIRECTION OUTPUT ;
    USE SIGNAL ;
    SHAPE ABUTMENT ;
    PORT
      LAYER metal3 ;
      RECT 339.325 770.000 339.395 770.070 ;
    END
  END r0_rd_out[215]
  PIN r0_rd_out[216]
    DIRECTION OUTPUT ;
    USE SIGNAL ;
    SHAPE ABUTMENT ;
    PORT
      LAYER metal3 ;
      RECT 339.465 770.000 339.535 770.070 ;
    END
  END r0_rd_out[216]
  PIN r0_rd_out[217]
    DIRECTION OUTPUT ;
    USE SIGNAL ;
    SHAPE ABUTMENT ;
    PORT
      LAYER metal3 ;
      RECT 339.605 770.000 339.675 770.070 ;
    END
  END r0_rd_out[217]
  PIN r0_rd_out[218]
    DIRECTION OUTPUT ;
    USE SIGNAL ;
    SHAPE ABUTMENT ;
    PORT
      LAYER metal3 ;
      RECT 339.745 770.000 339.815 770.070 ;
    END
  END r0_rd_out[218]
  PIN r0_rd_out[219]
    DIRECTION OUTPUT ;
    USE SIGNAL ;
    SHAPE ABUTMENT ;
    PORT
      LAYER metal3 ;
      RECT 339.885 770.000 339.955 770.070 ;
    END
  END r0_rd_out[219]
  PIN r0_rd_out[220]
    DIRECTION OUTPUT ;
    USE SIGNAL ;
    SHAPE ABUTMENT ;
    PORT
      LAYER metal3 ;
      RECT 340.025 770.000 340.095 770.070 ;
    END
  END r0_rd_out[220]
  PIN r0_rd_out[221]
    DIRECTION OUTPUT ;
    USE SIGNAL ;
    SHAPE ABUTMENT ;
    PORT
      LAYER metal3 ;
      RECT 340.165 770.000 340.235 770.070 ;
    END
  END r0_rd_out[221]
  PIN r0_rd_out[222]
    DIRECTION OUTPUT ;
    USE SIGNAL ;
    SHAPE ABUTMENT ;
    PORT
      LAYER metal3 ;
      RECT 340.305 770.000 340.375 770.070 ;
    END
  END r0_rd_out[222]
  PIN r0_rd_out[223]
    DIRECTION OUTPUT ;
    USE SIGNAL ;
    SHAPE ABUTMENT ;
    PORT
      LAYER metal3 ;
      RECT 340.445 770.000 340.515 770.070 ;
    END
  END r0_rd_out[223]
  PIN r0_rd_out[224]
    DIRECTION OUTPUT ;
    USE SIGNAL ;
    SHAPE ABUTMENT ;
    PORT
      LAYER metal3 ;
      RECT 340.585 770.000 340.655 770.070 ;
    END
  END r0_rd_out[224]
  PIN r0_rd_out[225]
    DIRECTION OUTPUT ;
    USE SIGNAL ;
    SHAPE ABUTMENT ;
    PORT
      LAYER metal3 ;
      RECT 340.725 770.000 340.795 770.070 ;
    END
  END r0_rd_out[225]
  PIN r0_rd_out[226]
    DIRECTION OUTPUT ;
    USE SIGNAL ;
    SHAPE ABUTMENT ;
    PORT
      LAYER metal3 ;
      RECT 340.865 770.000 340.935 770.070 ;
    END
  END r0_rd_out[226]
  PIN r0_rd_out[227]
    DIRECTION OUTPUT ;
    USE SIGNAL ;
    SHAPE ABUTMENT ;
    PORT
      LAYER metal3 ;
      RECT 341.005 770.000 341.075 770.070 ;
    END
  END r0_rd_out[227]
  PIN r0_rd_out[228]
    DIRECTION OUTPUT ;
    USE SIGNAL ;
    SHAPE ABUTMENT ;
    PORT
      LAYER metal3 ;
      RECT 341.145 770.000 341.215 770.070 ;
    END
  END r0_rd_out[228]
  PIN r0_rd_out[229]
    DIRECTION OUTPUT ;
    USE SIGNAL ;
    SHAPE ABUTMENT ;
    PORT
      LAYER metal3 ;
      RECT 341.285 770.000 341.355 770.070 ;
    END
  END r0_rd_out[229]
  PIN r0_rd_out[230]
    DIRECTION OUTPUT ;
    USE SIGNAL ;
    SHAPE ABUTMENT ;
    PORT
      LAYER metal3 ;
      RECT 341.425 770.000 341.495 770.070 ;
    END
  END r0_rd_out[230]
  PIN r0_rd_out[231]
    DIRECTION OUTPUT ;
    USE SIGNAL ;
    SHAPE ABUTMENT ;
    PORT
      LAYER metal3 ;
      RECT 341.565 770.000 341.635 770.070 ;
    END
  END r0_rd_out[231]
  PIN r0_rd_out[232]
    DIRECTION OUTPUT ;
    USE SIGNAL ;
    SHAPE ABUTMENT ;
    PORT
      LAYER metal3 ;
      RECT 341.705 770.000 341.775 770.070 ;
    END
  END r0_rd_out[232]
  PIN r0_rd_out[233]
    DIRECTION OUTPUT ;
    USE SIGNAL ;
    SHAPE ABUTMENT ;
    PORT
      LAYER metal3 ;
      RECT 341.845 770.000 341.915 770.070 ;
    END
  END r0_rd_out[233]
  PIN r0_rd_out[234]
    DIRECTION OUTPUT ;
    USE SIGNAL ;
    SHAPE ABUTMENT ;
    PORT
      LAYER metal3 ;
      RECT 341.985 770.000 342.055 770.070 ;
    END
  END r0_rd_out[234]
  PIN r0_rd_out[235]
    DIRECTION OUTPUT ;
    USE SIGNAL ;
    SHAPE ABUTMENT ;
    PORT
      LAYER metal3 ;
      RECT 342.125 770.000 342.195 770.070 ;
    END
  END r0_rd_out[235]
  PIN r0_rd_out[236]
    DIRECTION OUTPUT ;
    USE SIGNAL ;
    SHAPE ABUTMENT ;
    PORT
      LAYER metal3 ;
      RECT 342.265 770.000 342.335 770.070 ;
    END
  END r0_rd_out[236]
  PIN r0_rd_out[237]
    DIRECTION OUTPUT ;
    USE SIGNAL ;
    SHAPE ABUTMENT ;
    PORT
      LAYER metal3 ;
      RECT 342.405 770.000 342.475 770.070 ;
    END
  END r0_rd_out[237]
  PIN r0_rd_out[238]
    DIRECTION OUTPUT ;
    USE SIGNAL ;
    SHAPE ABUTMENT ;
    PORT
      LAYER metal3 ;
      RECT 342.545 770.000 342.615 770.070 ;
    END
  END r0_rd_out[238]
  PIN r0_rd_out[239]
    DIRECTION OUTPUT ;
    USE SIGNAL ;
    SHAPE ABUTMENT ;
    PORT
      LAYER metal3 ;
      RECT 342.685 770.000 342.755 770.070 ;
    END
  END r0_rd_out[239]
  PIN r0_rd_out[240]
    DIRECTION OUTPUT ;
    USE SIGNAL ;
    SHAPE ABUTMENT ;
    PORT
      LAYER metal3 ;
      RECT 342.825 770.000 342.895 770.070 ;
    END
  END r0_rd_out[240]
  PIN r0_rd_out[241]
    DIRECTION OUTPUT ;
    USE SIGNAL ;
    SHAPE ABUTMENT ;
    PORT
      LAYER metal3 ;
      RECT 342.965 770.000 343.035 770.070 ;
    END
  END r0_rd_out[241]
  PIN r0_rd_out[242]
    DIRECTION OUTPUT ;
    USE SIGNAL ;
    SHAPE ABUTMENT ;
    PORT
      LAYER metal3 ;
      RECT 343.105 770.000 343.175 770.070 ;
    END
  END r0_rd_out[242]
  PIN r0_rd_out[243]
    DIRECTION OUTPUT ;
    USE SIGNAL ;
    SHAPE ABUTMENT ;
    PORT
      LAYER metal3 ;
      RECT 343.245 770.000 343.315 770.070 ;
    END
  END r0_rd_out[243]
  PIN r0_rd_out[244]
    DIRECTION OUTPUT ;
    USE SIGNAL ;
    SHAPE ABUTMENT ;
    PORT
      LAYER metal3 ;
      RECT 343.385 770.000 343.455 770.070 ;
    END
  END r0_rd_out[244]
  PIN r0_rd_out[245]
    DIRECTION OUTPUT ;
    USE SIGNAL ;
    SHAPE ABUTMENT ;
    PORT
      LAYER metal3 ;
      RECT 343.525 770.000 343.595 770.070 ;
    END
  END r0_rd_out[245]
  PIN r0_rd_out[246]
    DIRECTION OUTPUT ;
    USE SIGNAL ;
    SHAPE ABUTMENT ;
    PORT
      LAYER metal3 ;
      RECT 343.665 770.000 343.735 770.070 ;
    END
  END r0_rd_out[246]
  PIN r0_rd_out[247]
    DIRECTION OUTPUT ;
    USE SIGNAL ;
    SHAPE ABUTMENT ;
    PORT
      LAYER metal3 ;
      RECT 343.805 770.000 343.875 770.070 ;
    END
  END r0_rd_out[247]
  PIN r0_rd_out[248]
    DIRECTION OUTPUT ;
    USE SIGNAL ;
    SHAPE ABUTMENT ;
    PORT
      LAYER metal3 ;
      RECT 343.945 770.000 344.015 770.070 ;
    END
  END r0_rd_out[248]
  PIN r0_rd_out[249]
    DIRECTION OUTPUT ;
    USE SIGNAL ;
    SHAPE ABUTMENT ;
    PORT
      LAYER metal3 ;
      RECT 344.085 770.000 344.155 770.070 ;
    END
  END r0_rd_out[249]
  PIN r0_rd_out[250]
    DIRECTION OUTPUT ;
    USE SIGNAL ;
    SHAPE ABUTMENT ;
    PORT
      LAYER metal3 ;
      RECT 344.225 770.000 344.295 770.070 ;
    END
  END r0_rd_out[250]
  PIN r0_rd_out[251]
    DIRECTION OUTPUT ;
    USE SIGNAL ;
    SHAPE ABUTMENT ;
    PORT
      LAYER metal3 ;
      RECT 344.365 770.000 344.435 770.070 ;
    END
  END r0_rd_out[251]
  PIN r0_rd_out[252]
    DIRECTION OUTPUT ;
    USE SIGNAL ;
    SHAPE ABUTMENT ;
    PORT
      LAYER metal3 ;
      RECT 344.505 770.000 344.575 770.070 ;
    END
  END r0_rd_out[252]
  PIN r0_rd_out[253]
    DIRECTION OUTPUT ;
    USE SIGNAL ;
    SHAPE ABUTMENT ;
    PORT
      LAYER metal3 ;
      RECT 344.645 770.000 344.715 770.070 ;
    END
  END r0_rd_out[253]
  PIN r0_rd_out[254]
    DIRECTION OUTPUT ;
    USE SIGNAL ;
    SHAPE ABUTMENT ;
    PORT
      LAYER metal3 ;
      RECT 344.785 770.000 344.855 770.070 ;
    END
  END r0_rd_out[254]
  PIN r0_rd_out[255]
    DIRECTION OUTPUT ;
    USE SIGNAL ;
    SHAPE ABUTMENT ;
    PORT
      LAYER metal3 ;
      RECT 344.925 770.000 344.995 770.070 ;
    END
  END r0_rd_out[255]
  PIN r0_rd_out[256]
    DIRECTION OUTPUT ;
    USE SIGNAL ;
    SHAPE ABUTMENT ;
    PORT
      LAYER metal3 ;
      RECT 345.065 770.000 345.135 770.070 ;
    END
  END r0_rd_out[256]
  PIN r0_rd_out[257]
    DIRECTION OUTPUT ;
    USE SIGNAL ;
    SHAPE ABUTMENT ;
    PORT
      LAYER metal3 ;
      RECT 345.205 770.000 345.275 770.070 ;
    END
  END r0_rd_out[257]
  PIN r0_rd_out[258]
    DIRECTION OUTPUT ;
    USE SIGNAL ;
    SHAPE ABUTMENT ;
    PORT
      LAYER metal3 ;
      RECT 345.345 770.000 345.415 770.070 ;
    END
  END r0_rd_out[258]
  PIN r0_rd_out[259]
    DIRECTION OUTPUT ;
    USE SIGNAL ;
    SHAPE ABUTMENT ;
    PORT
      LAYER metal3 ;
      RECT 345.485 770.000 345.555 770.070 ;
    END
  END r0_rd_out[259]
  PIN r0_rd_out[260]
    DIRECTION OUTPUT ;
    USE SIGNAL ;
    SHAPE ABUTMENT ;
    PORT
      LAYER metal3 ;
      RECT 345.625 770.000 345.695 770.070 ;
    END
  END r0_rd_out[260]
  PIN r0_rd_out[261]
    DIRECTION OUTPUT ;
    USE SIGNAL ;
    SHAPE ABUTMENT ;
    PORT
      LAYER metal3 ;
      RECT 345.765 770.000 345.835 770.070 ;
    END
  END r0_rd_out[261]
  PIN r0_rd_out[262]
    DIRECTION OUTPUT ;
    USE SIGNAL ;
    SHAPE ABUTMENT ;
    PORT
      LAYER metal3 ;
      RECT 345.905 770.000 345.975 770.070 ;
    END
  END r0_rd_out[262]
  PIN r0_rd_out[263]
    DIRECTION OUTPUT ;
    USE SIGNAL ;
    SHAPE ABUTMENT ;
    PORT
      LAYER metal3 ;
      RECT 346.045 770.000 346.115 770.070 ;
    END
  END r0_rd_out[263]
  PIN r0_rd_out[264]
    DIRECTION OUTPUT ;
    USE SIGNAL ;
    SHAPE ABUTMENT ;
    PORT
      LAYER metal3 ;
      RECT 346.185 770.000 346.255 770.070 ;
    END
  END r0_rd_out[264]
  PIN r0_rd_out[265]
    DIRECTION OUTPUT ;
    USE SIGNAL ;
    SHAPE ABUTMENT ;
    PORT
      LAYER metal3 ;
      RECT 346.325 770.000 346.395 770.070 ;
    END
  END r0_rd_out[265]
  PIN r0_rd_out[266]
    DIRECTION OUTPUT ;
    USE SIGNAL ;
    SHAPE ABUTMENT ;
    PORT
      LAYER metal3 ;
      RECT 346.465 770.000 346.535 770.070 ;
    END
  END r0_rd_out[266]
  PIN r0_rd_out[267]
    DIRECTION OUTPUT ;
    USE SIGNAL ;
    SHAPE ABUTMENT ;
    PORT
      LAYER metal3 ;
      RECT 346.605 770.000 346.675 770.070 ;
    END
  END r0_rd_out[267]
  PIN r0_rd_out[268]
    DIRECTION OUTPUT ;
    USE SIGNAL ;
    SHAPE ABUTMENT ;
    PORT
      LAYER metal3 ;
      RECT 346.745 770.000 346.815 770.070 ;
    END
  END r0_rd_out[268]
  PIN r0_rd_out[269]
    DIRECTION OUTPUT ;
    USE SIGNAL ;
    SHAPE ABUTMENT ;
    PORT
      LAYER metal3 ;
      RECT 346.885 770.000 346.955 770.070 ;
    END
  END r0_rd_out[269]
  PIN r0_rd_out[270]
    DIRECTION OUTPUT ;
    USE SIGNAL ;
    SHAPE ABUTMENT ;
    PORT
      LAYER metal3 ;
      RECT 347.025 770.000 347.095 770.070 ;
    END
  END r0_rd_out[270]
  PIN r0_rd_out[271]
    DIRECTION OUTPUT ;
    USE SIGNAL ;
    SHAPE ABUTMENT ;
    PORT
      LAYER metal3 ;
      RECT 347.165 770.000 347.235 770.070 ;
    END
  END r0_rd_out[271]
  PIN r0_rd_out[272]
    DIRECTION OUTPUT ;
    USE SIGNAL ;
    SHAPE ABUTMENT ;
    PORT
      LAYER metal3 ;
      RECT 347.305 770.000 347.375 770.070 ;
    END
  END r0_rd_out[272]
  PIN r0_rd_out[273]
    DIRECTION OUTPUT ;
    USE SIGNAL ;
    SHAPE ABUTMENT ;
    PORT
      LAYER metal3 ;
      RECT 347.445 770.000 347.515 770.070 ;
    END
  END r0_rd_out[273]
  PIN r0_rd_out[274]
    DIRECTION OUTPUT ;
    USE SIGNAL ;
    SHAPE ABUTMENT ;
    PORT
      LAYER metal3 ;
      RECT 347.585 770.000 347.655 770.070 ;
    END
  END r0_rd_out[274]
  PIN r0_rd_out[275]
    DIRECTION OUTPUT ;
    USE SIGNAL ;
    SHAPE ABUTMENT ;
    PORT
      LAYER metal3 ;
      RECT 347.725 770.000 347.795 770.070 ;
    END
  END r0_rd_out[275]
  PIN r0_rd_out[276]
    DIRECTION OUTPUT ;
    USE SIGNAL ;
    SHAPE ABUTMENT ;
    PORT
      LAYER metal3 ;
      RECT 347.865 770.000 347.935 770.070 ;
    END
  END r0_rd_out[276]
  PIN r0_rd_out[277]
    DIRECTION OUTPUT ;
    USE SIGNAL ;
    SHAPE ABUTMENT ;
    PORT
      LAYER metal3 ;
      RECT 348.005 770.000 348.075 770.070 ;
    END
  END r0_rd_out[277]
  PIN r0_rd_out[278]
    DIRECTION OUTPUT ;
    USE SIGNAL ;
    SHAPE ABUTMENT ;
    PORT
      LAYER metal3 ;
      RECT 348.145 770.000 348.215 770.070 ;
    END
  END r0_rd_out[278]
  PIN r0_rd_out[279]
    DIRECTION OUTPUT ;
    USE SIGNAL ;
    SHAPE ABUTMENT ;
    PORT
      LAYER metal3 ;
      RECT 348.285 770.000 348.355 770.070 ;
    END
  END r0_rd_out[279]
  PIN r0_rd_out[280]
    DIRECTION OUTPUT ;
    USE SIGNAL ;
    SHAPE ABUTMENT ;
    PORT
      LAYER metal3 ;
      RECT 348.425 770.000 348.495 770.070 ;
    END
  END r0_rd_out[280]
  PIN r0_rd_out[281]
    DIRECTION OUTPUT ;
    USE SIGNAL ;
    SHAPE ABUTMENT ;
    PORT
      LAYER metal3 ;
      RECT 348.565 770.000 348.635 770.070 ;
    END
  END r0_rd_out[281]
  PIN r0_rd_out[282]
    DIRECTION OUTPUT ;
    USE SIGNAL ;
    SHAPE ABUTMENT ;
    PORT
      LAYER metal3 ;
      RECT 348.705 770.000 348.775 770.070 ;
    END
  END r0_rd_out[282]
  PIN r0_rd_out[283]
    DIRECTION OUTPUT ;
    USE SIGNAL ;
    SHAPE ABUTMENT ;
    PORT
      LAYER metal3 ;
      RECT 348.845 770.000 348.915 770.070 ;
    END
  END r0_rd_out[283]
  PIN r0_rd_out[284]
    DIRECTION OUTPUT ;
    USE SIGNAL ;
    SHAPE ABUTMENT ;
    PORT
      LAYER metal3 ;
      RECT 348.985 770.000 349.055 770.070 ;
    END
  END r0_rd_out[284]
  PIN r0_rd_out[285]
    DIRECTION OUTPUT ;
    USE SIGNAL ;
    SHAPE ABUTMENT ;
    PORT
      LAYER metal3 ;
      RECT 349.125 770.000 349.195 770.070 ;
    END
  END r0_rd_out[285]
  PIN r0_rd_out[286]
    DIRECTION OUTPUT ;
    USE SIGNAL ;
    SHAPE ABUTMENT ;
    PORT
      LAYER metal3 ;
      RECT 349.265 770.000 349.335 770.070 ;
    END
  END r0_rd_out[286]
  PIN r0_rd_out[287]
    DIRECTION OUTPUT ;
    USE SIGNAL ;
    SHAPE ABUTMENT ;
    PORT
      LAYER metal3 ;
      RECT 349.405 770.000 349.475 770.070 ;
    END
  END r0_rd_out[287]
  PIN r0_rd_out[288]
    DIRECTION OUTPUT ;
    USE SIGNAL ;
    SHAPE ABUTMENT ;
    PORT
      LAYER metal3 ;
      RECT 349.545 770.000 349.615 770.070 ;
    END
  END r0_rd_out[288]
  PIN r0_rd_out[289]
    DIRECTION OUTPUT ;
    USE SIGNAL ;
    SHAPE ABUTMENT ;
    PORT
      LAYER metal3 ;
      RECT 349.685 770.000 349.755 770.070 ;
    END
  END r0_rd_out[289]
  PIN r0_rd_out[290]
    DIRECTION OUTPUT ;
    USE SIGNAL ;
    SHAPE ABUTMENT ;
    PORT
      LAYER metal3 ;
      RECT 349.825 770.000 349.895 770.070 ;
    END
  END r0_rd_out[290]
  PIN r0_rd_out[291]
    DIRECTION OUTPUT ;
    USE SIGNAL ;
    SHAPE ABUTMENT ;
    PORT
      LAYER metal3 ;
      RECT 349.965 770.000 350.035 770.070 ;
    END
  END r0_rd_out[291]
  PIN r0_rd_out[292]
    DIRECTION OUTPUT ;
    USE SIGNAL ;
    SHAPE ABUTMENT ;
    PORT
      LAYER metal3 ;
      RECT 350.105 770.000 350.175 770.070 ;
    END
  END r0_rd_out[292]
  PIN r0_rd_out[293]
    DIRECTION OUTPUT ;
    USE SIGNAL ;
    SHAPE ABUTMENT ;
    PORT
      LAYER metal3 ;
      RECT 350.245 770.000 350.315 770.070 ;
    END
  END r0_rd_out[293]
  PIN r0_rd_out[294]
    DIRECTION OUTPUT ;
    USE SIGNAL ;
    SHAPE ABUTMENT ;
    PORT
      LAYER metal3 ;
      RECT 350.385 770.000 350.455 770.070 ;
    END
  END r0_rd_out[294]
  PIN r0_rd_out[295]
    DIRECTION OUTPUT ;
    USE SIGNAL ;
    SHAPE ABUTMENT ;
    PORT
      LAYER metal3 ;
      RECT 350.525 770.000 350.595 770.070 ;
    END
  END r0_rd_out[295]
  PIN r0_rd_out[296]
    DIRECTION OUTPUT ;
    USE SIGNAL ;
    SHAPE ABUTMENT ;
    PORT
      LAYER metal3 ;
      RECT 350.665 770.000 350.735 770.070 ;
    END
  END r0_rd_out[296]
  PIN r0_rd_out[297]
    DIRECTION OUTPUT ;
    USE SIGNAL ;
    SHAPE ABUTMENT ;
    PORT
      LAYER metal3 ;
      RECT 350.805 770.000 350.875 770.070 ;
    END
  END r0_rd_out[297]
  PIN r0_rd_out[298]
    DIRECTION OUTPUT ;
    USE SIGNAL ;
    SHAPE ABUTMENT ;
    PORT
      LAYER metal3 ;
      RECT 350.945 770.000 351.015 770.070 ;
    END
  END r0_rd_out[298]
  PIN r0_rd_out[299]
    DIRECTION OUTPUT ;
    USE SIGNAL ;
    SHAPE ABUTMENT ;
    PORT
      LAYER metal3 ;
      RECT 351.085 770.000 351.155 770.070 ;
    END
  END r0_rd_out[299]
  PIN r0_rd_out[300]
    DIRECTION OUTPUT ;
    USE SIGNAL ;
    SHAPE ABUTMENT ;
    PORT
      LAYER metal3 ;
      RECT 351.225 770.000 351.295 770.070 ;
    END
  END r0_rd_out[300]
  PIN r0_rd_out[301]
    DIRECTION OUTPUT ;
    USE SIGNAL ;
    SHAPE ABUTMENT ;
    PORT
      LAYER metal3 ;
      RECT 351.365 770.000 351.435 770.070 ;
    END
  END r0_rd_out[301]
  PIN r0_rd_out[302]
    DIRECTION OUTPUT ;
    USE SIGNAL ;
    SHAPE ABUTMENT ;
    PORT
      LAYER metal3 ;
      RECT 351.505 770.000 351.575 770.070 ;
    END
  END r0_rd_out[302]
  PIN r0_rd_out[303]
    DIRECTION OUTPUT ;
    USE SIGNAL ;
    SHAPE ABUTMENT ;
    PORT
      LAYER metal3 ;
      RECT 351.645 770.000 351.715 770.070 ;
    END
  END r0_rd_out[303]
  PIN r0_rd_out[304]
    DIRECTION OUTPUT ;
    USE SIGNAL ;
    SHAPE ABUTMENT ;
    PORT
      LAYER metal3 ;
      RECT 351.785 770.000 351.855 770.070 ;
    END
  END r0_rd_out[304]
  PIN r0_rd_out[305]
    DIRECTION OUTPUT ;
    USE SIGNAL ;
    SHAPE ABUTMENT ;
    PORT
      LAYER metal3 ;
      RECT 351.925 770.000 351.995 770.070 ;
    END
  END r0_rd_out[305]
  PIN r0_rd_out[306]
    DIRECTION OUTPUT ;
    USE SIGNAL ;
    SHAPE ABUTMENT ;
    PORT
      LAYER metal3 ;
      RECT 352.065 770.000 352.135 770.070 ;
    END
  END r0_rd_out[306]
  PIN r0_rd_out[307]
    DIRECTION OUTPUT ;
    USE SIGNAL ;
    SHAPE ABUTMENT ;
    PORT
      LAYER metal3 ;
      RECT 352.205 770.000 352.275 770.070 ;
    END
  END r0_rd_out[307]
  PIN r0_rd_out[308]
    DIRECTION OUTPUT ;
    USE SIGNAL ;
    SHAPE ABUTMENT ;
    PORT
      LAYER metal3 ;
      RECT 352.345 770.000 352.415 770.070 ;
    END
  END r0_rd_out[308]
  PIN r0_rd_out[309]
    DIRECTION OUTPUT ;
    USE SIGNAL ;
    SHAPE ABUTMENT ;
    PORT
      LAYER metal3 ;
      RECT 352.485 770.000 352.555 770.070 ;
    END
  END r0_rd_out[309]
  PIN r0_rd_out[310]
    DIRECTION OUTPUT ;
    USE SIGNAL ;
    SHAPE ABUTMENT ;
    PORT
      LAYER metal3 ;
      RECT 352.625 770.000 352.695 770.070 ;
    END
  END r0_rd_out[310]
  PIN r0_rd_out[311]
    DIRECTION OUTPUT ;
    USE SIGNAL ;
    SHAPE ABUTMENT ;
    PORT
      LAYER metal3 ;
      RECT 352.765 770.000 352.835 770.070 ;
    END
  END r0_rd_out[311]
  PIN r0_rd_out[312]
    DIRECTION OUTPUT ;
    USE SIGNAL ;
    SHAPE ABUTMENT ;
    PORT
      LAYER metal3 ;
      RECT 352.905 770.000 352.975 770.070 ;
    END
  END r0_rd_out[312]
  PIN r0_rd_out[313]
    DIRECTION OUTPUT ;
    USE SIGNAL ;
    SHAPE ABUTMENT ;
    PORT
      LAYER metal3 ;
      RECT 353.045 770.000 353.115 770.070 ;
    END
  END r0_rd_out[313]
  PIN r0_rd_out[314]
    DIRECTION OUTPUT ;
    USE SIGNAL ;
    SHAPE ABUTMENT ;
    PORT
      LAYER metal3 ;
      RECT 353.185 770.000 353.255 770.070 ;
    END
  END r0_rd_out[314]
  PIN r0_rd_out[315]
    DIRECTION OUTPUT ;
    USE SIGNAL ;
    SHAPE ABUTMENT ;
    PORT
      LAYER metal3 ;
      RECT 353.325 770.000 353.395 770.070 ;
    END
  END r0_rd_out[315]
  PIN r0_rd_out[316]
    DIRECTION OUTPUT ;
    USE SIGNAL ;
    SHAPE ABUTMENT ;
    PORT
      LAYER metal3 ;
      RECT 353.465 770.000 353.535 770.070 ;
    END
  END r0_rd_out[316]
  PIN r0_rd_out[317]
    DIRECTION OUTPUT ;
    USE SIGNAL ;
    SHAPE ABUTMENT ;
    PORT
      LAYER metal3 ;
      RECT 353.605 770.000 353.675 770.070 ;
    END
  END r0_rd_out[317]
  PIN r0_rd_out[318]
    DIRECTION OUTPUT ;
    USE SIGNAL ;
    SHAPE ABUTMENT ;
    PORT
      LAYER metal3 ;
      RECT 353.745 770.000 353.815 770.070 ;
    END
  END r0_rd_out[318]
  PIN r0_rd_out[319]
    DIRECTION OUTPUT ;
    USE SIGNAL ;
    SHAPE ABUTMENT ;
    PORT
      LAYER metal3 ;
      RECT 353.885 770.000 353.955 770.070 ;
    END
  END r0_rd_out[319]
  PIN r0_rd_out[320]
    DIRECTION OUTPUT ;
    USE SIGNAL ;
    SHAPE ABUTMENT ;
    PORT
      LAYER metal3 ;
      RECT 354.025 770.000 354.095 770.070 ;
    END
  END r0_rd_out[320]
  PIN r0_rd_out[321]
    DIRECTION OUTPUT ;
    USE SIGNAL ;
    SHAPE ABUTMENT ;
    PORT
      LAYER metal3 ;
      RECT 354.165 770.000 354.235 770.070 ;
    END
  END r0_rd_out[321]
  PIN r0_rd_out[322]
    DIRECTION OUTPUT ;
    USE SIGNAL ;
    SHAPE ABUTMENT ;
    PORT
      LAYER metal3 ;
      RECT 354.305 770.000 354.375 770.070 ;
    END
  END r0_rd_out[322]
  PIN r0_rd_out[323]
    DIRECTION OUTPUT ;
    USE SIGNAL ;
    SHAPE ABUTMENT ;
    PORT
      LAYER metal3 ;
      RECT 354.445 770.000 354.515 770.070 ;
    END
  END r0_rd_out[323]
  PIN r0_rd_out[324]
    DIRECTION OUTPUT ;
    USE SIGNAL ;
    SHAPE ABUTMENT ;
    PORT
      LAYER metal3 ;
      RECT 354.585 770.000 354.655 770.070 ;
    END
  END r0_rd_out[324]
  PIN r0_rd_out[325]
    DIRECTION OUTPUT ;
    USE SIGNAL ;
    SHAPE ABUTMENT ;
    PORT
      LAYER metal3 ;
      RECT 354.725 770.000 354.795 770.070 ;
    END
  END r0_rd_out[325]
  PIN r0_rd_out[326]
    DIRECTION OUTPUT ;
    USE SIGNAL ;
    SHAPE ABUTMENT ;
    PORT
      LAYER metal3 ;
      RECT 354.865 770.000 354.935 770.070 ;
    END
  END r0_rd_out[326]
  PIN r0_rd_out[327]
    DIRECTION OUTPUT ;
    USE SIGNAL ;
    SHAPE ABUTMENT ;
    PORT
      LAYER metal3 ;
      RECT 355.005 770.000 355.075 770.070 ;
    END
  END r0_rd_out[327]
  PIN r0_rd_out[328]
    DIRECTION OUTPUT ;
    USE SIGNAL ;
    SHAPE ABUTMENT ;
    PORT
      LAYER metal3 ;
      RECT 355.145 770.000 355.215 770.070 ;
    END
  END r0_rd_out[328]
  PIN r0_rd_out[329]
    DIRECTION OUTPUT ;
    USE SIGNAL ;
    SHAPE ABUTMENT ;
    PORT
      LAYER metal3 ;
      RECT 355.285 770.000 355.355 770.070 ;
    END
  END r0_rd_out[329]
  PIN r0_rd_out[330]
    DIRECTION OUTPUT ;
    USE SIGNAL ;
    SHAPE ABUTMENT ;
    PORT
      LAYER metal3 ;
      RECT 355.425 770.000 355.495 770.070 ;
    END
  END r0_rd_out[330]
  PIN r0_rd_out[331]
    DIRECTION OUTPUT ;
    USE SIGNAL ;
    SHAPE ABUTMENT ;
    PORT
      LAYER metal3 ;
      RECT 355.565 770.000 355.635 770.070 ;
    END
  END r0_rd_out[331]
  PIN r0_rd_out[332]
    DIRECTION OUTPUT ;
    USE SIGNAL ;
    SHAPE ABUTMENT ;
    PORT
      LAYER metal3 ;
      RECT 355.705 770.000 355.775 770.070 ;
    END
  END r0_rd_out[332]
  PIN r0_rd_out[333]
    DIRECTION OUTPUT ;
    USE SIGNAL ;
    SHAPE ABUTMENT ;
    PORT
      LAYER metal3 ;
      RECT 355.845 770.000 355.915 770.070 ;
    END
  END r0_rd_out[333]
  PIN r0_rd_out[334]
    DIRECTION OUTPUT ;
    USE SIGNAL ;
    SHAPE ABUTMENT ;
    PORT
      LAYER metal3 ;
      RECT 355.985 770.000 356.055 770.070 ;
    END
  END r0_rd_out[334]
  PIN r0_rd_out[335]
    DIRECTION OUTPUT ;
    USE SIGNAL ;
    SHAPE ABUTMENT ;
    PORT
      LAYER metal3 ;
      RECT 356.125 770.000 356.195 770.070 ;
    END
  END r0_rd_out[335]
  PIN r0_rd_out[336]
    DIRECTION OUTPUT ;
    USE SIGNAL ;
    SHAPE ABUTMENT ;
    PORT
      LAYER metal3 ;
      RECT 356.265 770.000 356.335 770.070 ;
    END
  END r0_rd_out[336]
  PIN r0_rd_out[337]
    DIRECTION OUTPUT ;
    USE SIGNAL ;
    SHAPE ABUTMENT ;
    PORT
      LAYER metal3 ;
      RECT 356.405 770.000 356.475 770.070 ;
    END
  END r0_rd_out[337]
  PIN r0_rd_out[338]
    DIRECTION OUTPUT ;
    USE SIGNAL ;
    SHAPE ABUTMENT ;
    PORT
      LAYER metal3 ;
      RECT 356.545 770.000 356.615 770.070 ;
    END
  END r0_rd_out[338]
  PIN r0_rd_out[339]
    DIRECTION OUTPUT ;
    USE SIGNAL ;
    SHAPE ABUTMENT ;
    PORT
      LAYER metal3 ;
      RECT 356.685 770.000 356.755 770.070 ;
    END
  END r0_rd_out[339]
  PIN r0_rd_out[340]
    DIRECTION OUTPUT ;
    USE SIGNAL ;
    SHAPE ABUTMENT ;
    PORT
      LAYER metal3 ;
      RECT 356.825 770.000 356.895 770.070 ;
    END
  END r0_rd_out[340]
  PIN r0_rd_out[341]
    DIRECTION OUTPUT ;
    USE SIGNAL ;
    SHAPE ABUTMENT ;
    PORT
      LAYER metal3 ;
      RECT 356.965 770.000 357.035 770.070 ;
    END
  END r0_rd_out[341]
  PIN r0_rd_out[342]
    DIRECTION OUTPUT ;
    USE SIGNAL ;
    SHAPE ABUTMENT ;
    PORT
      LAYER metal3 ;
      RECT 357.105 770.000 357.175 770.070 ;
    END
  END r0_rd_out[342]
  PIN r0_rd_out[343]
    DIRECTION OUTPUT ;
    USE SIGNAL ;
    SHAPE ABUTMENT ;
    PORT
      LAYER metal3 ;
      RECT 357.245 770.000 357.315 770.070 ;
    END
  END r0_rd_out[343]
  PIN r0_rd_out[344]
    DIRECTION OUTPUT ;
    USE SIGNAL ;
    SHAPE ABUTMENT ;
    PORT
      LAYER metal3 ;
      RECT 357.385 770.000 357.455 770.070 ;
    END
  END r0_rd_out[344]
  PIN r0_rd_out[345]
    DIRECTION OUTPUT ;
    USE SIGNAL ;
    SHAPE ABUTMENT ;
    PORT
      LAYER metal3 ;
      RECT 357.525 770.000 357.595 770.070 ;
    END
  END r0_rd_out[345]
  PIN r0_rd_out[346]
    DIRECTION OUTPUT ;
    USE SIGNAL ;
    SHAPE ABUTMENT ;
    PORT
      LAYER metal3 ;
      RECT 357.665 770.000 357.735 770.070 ;
    END
  END r0_rd_out[346]
  PIN r0_rd_out[347]
    DIRECTION OUTPUT ;
    USE SIGNAL ;
    SHAPE ABUTMENT ;
    PORT
      LAYER metal3 ;
      RECT 357.805 770.000 357.875 770.070 ;
    END
  END r0_rd_out[347]
  PIN r0_rd_out[348]
    DIRECTION OUTPUT ;
    USE SIGNAL ;
    SHAPE ABUTMENT ;
    PORT
      LAYER metal3 ;
      RECT 357.945 770.000 358.015 770.070 ;
    END
  END r0_rd_out[348]
  PIN r0_rd_out[349]
    DIRECTION OUTPUT ;
    USE SIGNAL ;
    SHAPE ABUTMENT ;
    PORT
      LAYER metal3 ;
      RECT 358.085 770.000 358.155 770.070 ;
    END
  END r0_rd_out[349]
  PIN r0_rd_out[350]
    DIRECTION OUTPUT ;
    USE SIGNAL ;
    SHAPE ABUTMENT ;
    PORT
      LAYER metal3 ;
      RECT 358.225 770.000 358.295 770.070 ;
    END
  END r0_rd_out[350]
  PIN r0_rd_out[351]
    DIRECTION OUTPUT ;
    USE SIGNAL ;
    SHAPE ABUTMENT ;
    PORT
      LAYER metal3 ;
      RECT 358.365 770.000 358.435 770.070 ;
    END
  END r0_rd_out[351]
  PIN r0_rd_out[352]
    DIRECTION OUTPUT ;
    USE SIGNAL ;
    SHAPE ABUTMENT ;
    PORT
      LAYER metal3 ;
      RECT 358.505 770.000 358.575 770.070 ;
    END
  END r0_rd_out[352]
  PIN r0_rd_out[353]
    DIRECTION OUTPUT ;
    USE SIGNAL ;
    SHAPE ABUTMENT ;
    PORT
      LAYER metal3 ;
      RECT 358.645 770.000 358.715 770.070 ;
    END
  END r0_rd_out[353]
  PIN r0_rd_out[354]
    DIRECTION OUTPUT ;
    USE SIGNAL ;
    SHAPE ABUTMENT ;
    PORT
      LAYER metal3 ;
      RECT 358.785 770.000 358.855 770.070 ;
    END
  END r0_rd_out[354]
  PIN r0_rd_out[355]
    DIRECTION OUTPUT ;
    USE SIGNAL ;
    SHAPE ABUTMENT ;
    PORT
      LAYER metal3 ;
      RECT 358.925 770.000 358.995 770.070 ;
    END
  END r0_rd_out[355]
  PIN r0_rd_out[356]
    DIRECTION OUTPUT ;
    USE SIGNAL ;
    SHAPE ABUTMENT ;
    PORT
      LAYER metal3 ;
      RECT 359.065 770.000 359.135 770.070 ;
    END
  END r0_rd_out[356]
  PIN r0_rd_out[357]
    DIRECTION OUTPUT ;
    USE SIGNAL ;
    SHAPE ABUTMENT ;
    PORT
      LAYER metal3 ;
      RECT 359.205 770.000 359.275 770.070 ;
    END
  END r0_rd_out[357]
  PIN r0_rd_out[358]
    DIRECTION OUTPUT ;
    USE SIGNAL ;
    SHAPE ABUTMENT ;
    PORT
      LAYER metal3 ;
      RECT 359.345 770.000 359.415 770.070 ;
    END
  END r0_rd_out[358]
  PIN r0_rd_out[359]
    DIRECTION OUTPUT ;
    USE SIGNAL ;
    SHAPE ABUTMENT ;
    PORT
      LAYER metal3 ;
      RECT 359.485 770.000 359.555 770.070 ;
    END
  END r0_rd_out[359]
  PIN r0_rd_out[360]
    DIRECTION OUTPUT ;
    USE SIGNAL ;
    SHAPE ABUTMENT ;
    PORT
      LAYER metal3 ;
      RECT 359.625 770.000 359.695 770.070 ;
    END
  END r0_rd_out[360]
  PIN r0_rd_out[361]
    DIRECTION OUTPUT ;
    USE SIGNAL ;
    SHAPE ABUTMENT ;
    PORT
      LAYER metal3 ;
      RECT 359.765 770.000 359.835 770.070 ;
    END
  END r0_rd_out[361]
  PIN r0_rd_out[362]
    DIRECTION OUTPUT ;
    USE SIGNAL ;
    SHAPE ABUTMENT ;
    PORT
      LAYER metal3 ;
      RECT 359.905 770.000 359.975 770.070 ;
    END
  END r0_rd_out[362]
  PIN r0_rd_out[363]
    DIRECTION OUTPUT ;
    USE SIGNAL ;
    SHAPE ABUTMENT ;
    PORT
      LAYER metal3 ;
      RECT 360.045 770.000 360.115 770.070 ;
    END
  END r0_rd_out[363]
  PIN r0_rd_out[364]
    DIRECTION OUTPUT ;
    USE SIGNAL ;
    SHAPE ABUTMENT ;
    PORT
      LAYER metal3 ;
      RECT 360.185 770.000 360.255 770.070 ;
    END
  END r0_rd_out[364]
  PIN r0_rd_out[365]
    DIRECTION OUTPUT ;
    USE SIGNAL ;
    SHAPE ABUTMENT ;
    PORT
      LAYER metal3 ;
      RECT 360.325 770.000 360.395 770.070 ;
    END
  END r0_rd_out[365]
  PIN r0_rd_out[366]
    DIRECTION OUTPUT ;
    USE SIGNAL ;
    SHAPE ABUTMENT ;
    PORT
      LAYER metal3 ;
      RECT 360.465 770.000 360.535 770.070 ;
    END
  END r0_rd_out[366]
  PIN r0_rd_out[367]
    DIRECTION OUTPUT ;
    USE SIGNAL ;
    SHAPE ABUTMENT ;
    PORT
      LAYER metal3 ;
      RECT 360.605 770.000 360.675 770.070 ;
    END
  END r0_rd_out[367]
  PIN r0_rd_out[368]
    DIRECTION OUTPUT ;
    USE SIGNAL ;
    SHAPE ABUTMENT ;
    PORT
      LAYER metal3 ;
      RECT 360.745 770.000 360.815 770.070 ;
    END
  END r0_rd_out[368]
  PIN r0_rd_out[369]
    DIRECTION OUTPUT ;
    USE SIGNAL ;
    SHAPE ABUTMENT ;
    PORT
      LAYER metal3 ;
      RECT 360.885 770.000 360.955 770.070 ;
    END
  END r0_rd_out[369]
  PIN r0_rd_out[370]
    DIRECTION OUTPUT ;
    USE SIGNAL ;
    SHAPE ABUTMENT ;
    PORT
      LAYER metal3 ;
      RECT 361.025 770.000 361.095 770.070 ;
    END
  END r0_rd_out[370]
  PIN r0_rd_out[371]
    DIRECTION OUTPUT ;
    USE SIGNAL ;
    SHAPE ABUTMENT ;
    PORT
      LAYER metal3 ;
      RECT 361.165 770.000 361.235 770.070 ;
    END
  END r0_rd_out[371]
  PIN r0_rd_out[372]
    DIRECTION OUTPUT ;
    USE SIGNAL ;
    SHAPE ABUTMENT ;
    PORT
      LAYER metal3 ;
      RECT 361.305 770.000 361.375 770.070 ;
    END
  END r0_rd_out[372]
  PIN r0_rd_out[373]
    DIRECTION OUTPUT ;
    USE SIGNAL ;
    SHAPE ABUTMENT ;
    PORT
      LAYER metal3 ;
      RECT 361.445 770.000 361.515 770.070 ;
    END
  END r0_rd_out[373]
  PIN r0_rd_out[374]
    DIRECTION OUTPUT ;
    USE SIGNAL ;
    SHAPE ABUTMENT ;
    PORT
      LAYER metal3 ;
      RECT 361.585 770.000 361.655 770.070 ;
    END
  END r0_rd_out[374]
  PIN r0_rd_out[375]
    DIRECTION OUTPUT ;
    USE SIGNAL ;
    SHAPE ABUTMENT ;
    PORT
      LAYER metal3 ;
      RECT 361.725 770.000 361.795 770.070 ;
    END
  END r0_rd_out[375]
  PIN r0_rd_out[376]
    DIRECTION OUTPUT ;
    USE SIGNAL ;
    SHAPE ABUTMENT ;
    PORT
      LAYER metal3 ;
      RECT 361.865 770.000 361.935 770.070 ;
    END
  END r0_rd_out[376]
  PIN r0_rd_out[377]
    DIRECTION OUTPUT ;
    USE SIGNAL ;
    SHAPE ABUTMENT ;
    PORT
      LAYER metal3 ;
      RECT 362.005 770.000 362.075 770.070 ;
    END
  END r0_rd_out[377]
  PIN r0_rd_out[378]
    DIRECTION OUTPUT ;
    USE SIGNAL ;
    SHAPE ABUTMENT ;
    PORT
      LAYER metal3 ;
      RECT 362.145 770.000 362.215 770.070 ;
    END
  END r0_rd_out[378]
  PIN r0_rd_out[379]
    DIRECTION OUTPUT ;
    USE SIGNAL ;
    SHAPE ABUTMENT ;
    PORT
      LAYER metal3 ;
      RECT 362.285 770.000 362.355 770.070 ;
    END
  END r0_rd_out[379]
  PIN r0_rd_out[380]
    DIRECTION OUTPUT ;
    USE SIGNAL ;
    SHAPE ABUTMENT ;
    PORT
      LAYER metal3 ;
      RECT 362.425 770.000 362.495 770.070 ;
    END
  END r0_rd_out[380]
  PIN r0_rd_out[381]
    DIRECTION OUTPUT ;
    USE SIGNAL ;
    SHAPE ABUTMENT ;
    PORT
      LAYER metal3 ;
      RECT 362.565 770.000 362.635 770.070 ;
    END
  END r0_rd_out[381]
  PIN r0_rd_out[382]
    DIRECTION OUTPUT ;
    USE SIGNAL ;
    SHAPE ABUTMENT ;
    PORT
      LAYER metal3 ;
      RECT 362.705 770.000 362.775 770.070 ;
    END
  END r0_rd_out[382]
  PIN r0_rd_out[383]
    DIRECTION OUTPUT ;
    USE SIGNAL ;
    SHAPE ABUTMENT ;
    PORT
      LAYER metal3 ;
      RECT 362.845 770.000 362.915 770.070 ;
    END
  END r0_rd_out[383]
  PIN r0_rd_out[384]
    DIRECTION OUTPUT ;
    USE SIGNAL ;
    SHAPE ABUTMENT ;
    PORT
      LAYER metal3 ;
      RECT 362.985 770.000 363.055 770.070 ;
    END
  END r0_rd_out[384]
  PIN r0_rd_out[385]
    DIRECTION OUTPUT ;
    USE SIGNAL ;
    SHAPE ABUTMENT ;
    PORT
      LAYER metal3 ;
      RECT 363.125 770.000 363.195 770.070 ;
    END
  END r0_rd_out[385]
  PIN r0_rd_out[386]
    DIRECTION OUTPUT ;
    USE SIGNAL ;
    SHAPE ABUTMENT ;
    PORT
      LAYER metal3 ;
      RECT 363.265 770.000 363.335 770.070 ;
    END
  END r0_rd_out[386]
  PIN r0_rd_out[387]
    DIRECTION OUTPUT ;
    USE SIGNAL ;
    SHAPE ABUTMENT ;
    PORT
      LAYER metal3 ;
      RECT 363.405 770.000 363.475 770.070 ;
    END
  END r0_rd_out[387]
  PIN r0_rd_out[388]
    DIRECTION OUTPUT ;
    USE SIGNAL ;
    SHAPE ABUTMENT ;
    PORT
      LAYER metal3 ;
      RECT 363.545 770.000 363.615 770.070 ;
    END
  END r0_rd_out[388]
  PIN r0_rd_out[389]
    DIRECTION OUTPUT ;
    USE SIGNAL ;
    SHAPE ABUTMENT ;
    PORT
      LAYER metal3 ;
      RECT 363.685 770.000 363.755 770.070 ;
    END
  END r0_rd_out[389]
  PIN r0_rd_out[390]
    DIRECTION OUTPUT ;
    USE SIGNAL ;
    SHAPE ABUTMENT ;
    PORT
      LAYER metal3 ;
      RECT 363.825 770.000 363.895 770.070 ;
    END
  END r0_rd_out[390]
  PIN r0_rd_out[391]
    DIRECTION OUTPUT ;
    USE SIGNAL ;
    SHAPE ABUTMENT ;
    PORT
      LAYER metal3 ;
      RECT 363.965 770.000 364.035 770.070 ;
    END
  END r0_rd_out[391]
  PIN r0_rd_out[392]
    DIRECTION OUTPUT ;
    USE SIGNAL ;
    SHAPE ABUTMENT ;
    PORT
      LAYER metal3 ;
      RECT 364.105 770.000 364.175 770.070 ;
    END
  END r0_rd_out[392]
  PIN r0_rd_out[393]
    DIRECTION OUTPUT ;
    USE SIGNAL ;
    SHAPE ABUTMENT ;
    PORT
      LAYER metal3 ;
      RECT 364.245 770.000 364.315 770.070 ;
    END
  END r0_rd_out[393]
  PIN r0_rd_out[394]
    DIRECTION OUTPUT ;
    USE SIGNAL ;
    SHAPE ABUTMENT ;
    PORT
      LAYER metal3 ;
      RECT 364.385 770.000 364.455 770.070 ;
    END
  END r0_rd_out[394]
  PIN r0_rd_out[395]
    DIRECTION OUTPUT ;
    USE SIGNAL ;
    SHAPE ABUTMENT ;
    PORT
      LAYER metal3 ;
      RECT 364.525 770.000 364.595 770.070 ;
    END
  END r0_rd_out[395]
  PIN r0_rd_out[396]
    DIRECTION OUTPUT ;
    USE SIGNAL ;
    SHAPE ABUTMENT ;
    PORT
      LAYER metal3 ;
      RECT 364.665 770.000 364.735 770.070 ;
    END
  END r0_rd_out[396]
  PIN r0_rd_out[397]
    DIRECTION OUTPUT ;
    USE SIGNAL ;
    SHAPE ABUTMENT ;
    PORT
      LAYER metal3 ;
      RECT 364.805 770.000 364.875 770.070 ;
    END
  END r0_rd_out[397]
  PIN r0_rd_out[398]
    DIRECTION OUTPUT ;
    USE SIGNAL ;
    SHAPE ABUTMENT ;
    PORT
      LAYER metal3 ;
      RECT 364.945 770.000 365.015 770.070 ;
    END
  END r0_rd_out[398]
  PIN r0_rd_out[399]
    DIRECTION OUTPUT ;
    USE SIGNAL ;
    SHAPE ABUTMENT ;
    PORT
      LAYER metal3 ;
      RECT 365.085 770.000 365.155 770.070 ;
    END
  END r0_rd_out[399]
  PIN r0_rd_out[400]
    DIRECTION OUTPUT ;
    USE SIGNAL ;
    SHAPE ABUTMENT ;
    PORT
      LAYER metal3 ;
      RECT 365.225 770.000 365.295 770.070 ;
    END
  END r0_rd_out[400]
  PIN r0_rd_out[401]
    DIRECTION OUTPUT ;
    USE SIGNAL ;
    SHAPE ABUTMENT ;
    PORT
      LAYER metal3 ;
      RECT 365.365 770.000 365.435 770.070 ;
    END
  END r0_rd_out[401]
  PIN r0_rd_out[402]
    DIRECTION OUTPUT ;
    USE SIGNAL ;
    SHAPE ABUTMENT ;
    PORT
      LAYER metal3 ;
      RECT 365.505 770.000 365.575 770.070 ;
    END
  END r0_rd_out[402]
  PIN r0_rd_out[403]
    DIRECTION OUTPUT ;
    USE SIGNAL ;
    SHAPE ABUTMENT ;
    PORT
      LAYER metal3 ;
      RECT 365.645 770.000 365.715 770.070 ;
    END
  END r0_rd_out[403]
  PIN r0_rd_out[404]
    DIRECTION OUTPUT ;
    USE SIGNAL ;
    SHAPE ABUTMENT ;
    PORT
      LAYER metal3 ;
      RECT 365.785 770.000 365.855 770.070 ;
    END
  END r0_rd_out[404]
  PIN r0_rd_out[405]
    DIRECTION OUTPUT ;
    USE SIGNAL ;
    SHAPE ABUTMENT ;
    PORT
      LAYER metal3 ;
      RECT 365.925 770.000 365.995 770.070 ;
    END
  END r0_rd_out[405]
  PIN r0_rd_out[406]
    DIRECTION OUTPUT ;
    USE SIGNAL ;
    SHAPE ABUTMENT ;
    PORT
      LAYER metal3 ;
      RECT 366.065 770.000 366.135 770.070 ;
    END
  END r0_rd_out[406]
  PIN r0_rd_out[407]
    DIRECTION OUTPUT ;
    USE SIGNAL ;
    SHAPE ABUTMENT ;
    PORT
      LAYER metal3 ;
      RECT 366.205 770.000 366.275 770.070 ;
    END
  END r0_rd_out[407]
  PIN r0_rd_out[408]
    DIRECTION OUTPUT ;
    USE SIGNAL ;
    SHAPE ABUTMENT ;
    PORT
      LAYER metal3 ;
      RECT 366.345 770.000 366.415 770.070 ;
    END
  END r0_rd_out[408]
  PIN r0_rd_out[409]
    DIRECTION OUTPUT ;
    USE SIGNAL ;
    SHAPE ABUTMENT ;
    PORT
      LAYER metal3 ;
      RECT 366.485 770.000 366.555 770.070 ;
    END
  END r0_rd_out[409]
  PIN r0_rd_out[410]
    DIRECTION OUTPUT ;
    USE SIGNAL ;
    SHAPE ABUTMENT ;
    PORT
      LAYER metal3 ;
      RECT 366.625 770.000 366.695 770.070 ;
    END
  END r0_rd_out[410]
  PIN r0_rd_out[411]
    DIRECTION OUTPUT ;
    USE SIGNAL ;
    SHAPE ABUTMENT ;
    PORT
      LAYER metal3 ;
      RECT 366.765 770.000 366.835 770.070 ;
    END
  END r0_rd_out[411]
  PIN r0_rd_out[412]
    DIRECTION OUTPUT ;
    USE SIGNAL ;
    SHAPE ABUTMENT ;
    PORT
      LAYER metal3 ;
      RECT 366.905 770.000 366.975 770.070 ;
    END
  END r0_rd_out[412]
  PIN r0_rd_out[413]
    DIRECTION OUTPUT ;
    USE SIGNAL ;
    SHAPE ABUTMENT ;
    PORT
      LAYER metal3 ;
      RECT 367.045 770.000 367.115 770.070 ;
    END
  END r0_rd_out[413]
  PIN r0_rd_out[414]
    DIRECTION OUTPUT ;
    USE SIGNAL ;
    SHAPE ABUTMENT ;
    PORT
      LAYER metal3 ;
      RECT 367.185 770.000 367.255 770.070 ;
    END
  END r0_rd_out[414]
  PIN r0_rd_out[415]
    DIRECTION OUTPUT ;
    USE SIGNAL ;
    SHAPE ABUTMENT ;
    PORT
      LAYER metal3 ;
      RECT 367.325 770.000 367.395 770.070 ;
    END
  END r0_rd_out[415]
  PIN r0_rd_out[416]
    DIRECTION OUTPUT ;
    USE SIGNAL ;
    SHAPE ABUTMENT ;
    PORT
      LAYER metal3 ;
      RECT 367.465 770.000 367.535 770.070 ;
    END
  END r0_rd_out[416]
  PIN r0_rd_out[417]
    DIRECTION OUTPUT ;
    USE SIGNAL ;
    SHAPE ABUTMENT ;
    PORT
      LAYER metal3 ;
      RECT 367.605 770.000 367.675 770.070 ;
    END
  END r0_rd_out[417]
  PIN r0_rd_out[418]
    DIRECTION OUTPUT ;
    USE SIGNAL ;
    SHAPE ABUTMENT ;
    PORT
      LAYER metal3 ;
      RECT 367.745 770.000 367.815 770.070 ;
    END
  END r0_rd_out[418]
  PIN r0_rd_out[419]
    DIRECTION OUTPUT ;
    USE SIGNAL ;
    SHAPE ABUTMENT ;
    PORT
      LAYER metal3 ;
      RECT 367.885 770.000 367.955 770.070 ;
    END
  END r0_rd_out[419]
  PIN r0_rd_out[420]
    DIRECTION OUTPUT ;
    USE SIGNAL ;
    SHAPE ABUTMENT ;
    PORT
      LAYER metal3 ;
      RECT 368.025 770.000 368.095 770.070 ;
    END
  END r0_rd_out[420]
  PIN r0_rd_out[421]
    DIRECTION OUTPUT ;
    USE SIGNAL ;
    SHAPE ABUTMENT ;
    PORT
      LAYER metal3 ;
      RECT 368.165 770.000 368.235 770.070 ;
    END
  END r0_rd_out[421]
  PIN r0_rd_out[422]
    DIRECTION OUTPUT ;
    USE SIGNAL ;
    SHAPE ABUTMENT ;
    PORT
      LAYER metal3 ;
      RECT 368.305 770.000 368.375 770.070 ;
    END
  END r0_rd_out[422]
  PIN r0_rd_out[423]
    DIRECTION OUTPUT ;
    USE SIGNAL ;
    SHAPE ABUTMENT ;
    PORT
      LAYER metal3 ;
      RECT 368.445 770.000 368.515 770.070 ;
    END
  END r0_rd_out[423]
  PIN r0_rd_out[424]
    DIRECTION OUTPUT ;
    USE SIGNAL ;
    SHAPE ABUTMENT ;
    PORT
      LAYER metal3 ;
      RECT 368.585 770.000 368.655 770.070 ;
    END
  END r0_rd_out[424]
  PIN r0_rd_out[425]
    DIRECTION OUTPUT ;
    USE SIGNAL ;
    SHAPE ABUTMENT ;
    PORT
      LAYER metal3 ;
      RECT 368.725 770.000 368.795 770.070 ;
    END
  END r0_rd_out[425]
  PIN r0_rd_out[426]
    DIRECTION OUTPUT ;
    USE SIGNAL ;
    SHAPE ABUTMENT ;
    PORT
      LAYER metal3 ;
      RECT 368.865 770.000 368.935 770.070 ;
    END
  END r0_rd_out[426]
  PIN r0_rd_out[427]
    DIRECTION OUTPUT ;
    USE SIGNAL ;
    SHAPE ABUTMENT ;
    PORT
      LAYER metal3 ;
      RECT 369.005 770.000 369.075 770.070 ;
    END
  END r0_rd_out[427]
  PIN r0_rd_out[428]
    DIRECTION OUTPUT ;
    USE SIGNAL ;
    SHAPE ABUTMENT ;
    PORT
      LAYER metal3 ;
      RECT 369.145 770.000 369.215 770.070 ;
    END
  END r0_rd_out[428]
  PIN r0_rd_out[429]
    DIRECTION OUTPUT ;
    USE SIGNAL ;
    SHAPE ABUTMENT ;
    PORT
      LAYER metal3 ;
      RECT 369.285 770.000 369.355 770.070 ;
    END
  END r0_rd_out[429]
  PIN r0_rd_out[430]
    DIRECTION OUTPUT ;
    USE SIGNAL ;
    SHAPE ABUTMENT ;
    PORT
      LAYER metal3 ;
      RECT 369.425 770.000 369.495 770.070 ;
    END
  END r0_rd_out[430]
  PIN r0_rd_out[431]
    DIRECTION OUTPUT ;
    USE SIGNAL ;
    SHAPE ABUTMENT ;
    PORT
      LAYER metal3 ;
      RECT 369.565 770.000 369.635 770.070 ;
    END
  END r0_rd_out[431]
  PIN r0_rd_out[432]
    DIRECTION OUTPUT ;
    USE SIGNAL ;
    SHAPE ABUTMENT ;
    PORT
      LAYER metal3 ;
      RECT 369.705 770.000 369.775 770.070 ;
    END
  END r0_rd_out[432]
  PIN r0_rd_out[433]
    DIRECTION OUTPUT ;
    USE SIGNAL ;
    SHAPE ABUTMENT ;
    PORT
      LAYER metal3 ;
      RECT 369.845 770.000 369.915 770.070 ;
    END
  END r0_rd_out[433]
  PIN r0_rd_out[434]
    DIRECTION OUTPUT ;
    USE SIGNAL ;
    SHAPE ABUTMENT ;
    PORT
      LAYER metal3 ;
      RECT 369.985 770.000 370.055 770.070 ;
    END
  END r0_rd_out[434]
  PIN r0_rd_out[435]
    DIRECTION OUTPUT ;
    USE SIGNAL ;
    SHAPE ABUTMENT ;
    PORT
      LAYER metal3 ;
      RECT 370.125 770.000 370.195 770.070 ;
    END
  END r0_rd_out[435]
  PIN r0_rd_out[436]
    DIRECTION OUTPUT ;
    USE SIGNAL ;
    SHAPE ABUTMENT ;
    PORT
      LAYER metal3 ;
      RECT 370.265 770.000 370.335 770.070 ;
    END
  END r0_rd_out[436]
  PIN r0_rd_out[437]
    DIRECTION OUTPUT ;
    USE SIGNAL ;
    SHAPE ABUTMENT ;
    PORT
      LAYER metal3 ;
      RECT 370.405 770.000 370.475 770.070 ;
    END
  END r0_rd_out[437]
  PIN r0_rd_out[438]
    DIRECTION OUTPUT ;
    USE SIGNAL ;
    SHAPE ABUTMENT ;
    PORT
      LAYER metal3 ;
      RECT 370.545 770.000 370.615 770.070 ;
    END
  END r0_rd_out[438]
  PIN r0_rd_out[439]
    DIRECTION OUTPUT ;
    USE SIGNAL ;
    SHAPE ABUTMENT ;
    PORT
      LAYER metal3 ;
      RECT 370.685 770.000 370.755 770.070 ;
    END
  END r0_rd_out[439]
  PIN r0_rd_out[440]
    DIRECTION OUTPUT ;
    USE SIGNAL ;
    SHAPE ABUTMENT ;
    PORT
      LAYER metal3 ;
      RECT 370.825 770.000 370.895 770.070 ;
    END
  END r0_rd_out[440]
  PIN r0_rd_out[441]
    DIRECTION OUTPUT ;
    USE SIGNAL ;
    SHAPE ABUTMENT ;
    PORT
      LAYER metal3 ;
      RECT 370.965 770.000 371.035 770.070 ;
    END
  END r0_rd_out[441]
  PIN r0_rd_out[442]
    DIRECTION OUTPUT ;
    USE SIGNAL ;
    SHAPE ABUTMENT ;
    PORT
      LAYER metal3 ;
      RECT 371.105 770.000 371.175 770.070 ;
    END
  END r0_rd_out[442]
  PIN r0_rd_out[443]
    DIRECTION OUTPUT ;
    USE SIGNAL ;
    SHAPE ABUTMENT ;
    PORT
      LAYER metal3 ;
      RECT 371.245 770.000 371.315 770.070 ;
    END
  END r0_rd_out[443]
  PIN r0_rd_out[444]
    DIRECTION OUTPUT ;
    USE SIGNAL ;
    SHAPE ABUTMENT ;
    PORT
      LAYER metal3 ;
      RECT 371.385 770.000 371.455 770.070 ;
    END
  END r0_rd_out[444]
  PIN r0_rd_out[445]
    DIRECTION OUTPUT ;
    USE SIGNAL ;
    SHAPE ABUTMENT ;
    PORT
      LAYER metal3 ;
      RECT 371.525 770.000 371.595 770.070 ;
    END
  END r0_rd_out[445]
  PIN r0_rd_out[446]
    DIRECTION OUTPUT ;
    USE SIGNAL ;
    SHAPE ABUTMENT ;
    PORT
      LAYER metal3 ;
      RECT 371.665 770.000 371.735 770.070 ;
    END
  END r0_rd_out[446]
  PIN r0_rd_out[447]
    DIRECTION OUTPUT ;
    USE SIGNAL ;
    SHAPE ABUTMENT ;
    PORT
      LAYER metal3 ;
      RECT 371.805 770.000 371.875 770.070 ;
    END
  END r0_rd_out[447]
  PIN r0_rd_out[448]
    DIRECTION OUTPUT ;
    USE SIGNAL ;
    SHAPE ABUTMENT ;
    PORT
      LAYER metal3 ;
      RECT 371.945 770.000 372.015 770.070 ;
    END
  END r0_rd_out[448]
  PIN r0_rd_out[449]
    DIRECTION OUTPUT ;
    USE SIGNAL ;
    SHAPE ABUTMENT ;
    PORT
      LAYER metal3 ;
      RECT 372.085 770.000 372.155 770.070 ;
    END
  END r0_rd_out[449]
  PIN r0_rd_out[450]
    DIRECTION OUTPUT ;
    USE SIGNAL ;
    SHAPE ABUTMENT ;
    PORT
      LAYER metal3 ;
      RECT 372.225 770.000 372.295 770.070 ;
    END
  END r0_rd_out[450]
  PIN r0_rd_out[451]
    DIRECTION OUTPUT ;
    USE SIGNAL ;
    SHAPE ABUTMENT ;
    PORT
      LAYER metal3 ;
      RECT 372.365 770.000 372.435 770.070 ;
    END
  END r0_rd_out[451]
  PIN r0_rd_out[452]
    DIRECTION OUTPUT ;
    USE SIGNAL ;
    SHAPE ABUTMENT ;
    PORT
      LAYER metal3 ;
      RECT 372.505 770.000 372.575 770.070 ;
    END
  END r0_rd_out[452]
  PIN r0_rd_out[453]
    DIRECTION OUTPUT ;
    USE SIGNAL ;
    SHAPE ABUTMENT ;
    PORT
      LAYER metal3 ;
      RECT 372.645 770.000 372.715 770.070 ;
    END
  END r0_rd_out[453]
  PIN r0_rd_out[454]
    DIRECTION OUTPUT ;
    USE SIGNAL ;
    SHAPE ABUTMENT ;
    PORT
      LAYER metal3 ;
      RECT 372.785 770.000 372.855 770.070 ;
    END
  END r0_rd_out[454]
  PIN r0_rd_out[455]
    DIRECTION OUTPUT ;
    USE SIGNAL ;
    SHAPE ABUTMENT ;
    PORT
      LAYER metal3 ;
      RECT 372.925 770.000 372.995 770.070 ;
    END
  END r0_rd_out[455]
  PIN r0_rd_out[456]
    DIRECTION OUTPUT ;
    USE SIGNAL ;
    SHAPE ABUTMENT ;
    PORT
      LAYER metal3 ;
      RECT 373.065 770.000 373.135 770.070 ;
    END
  END r0_rd_out[456]
  PIN r0_rd_out[457]
    DIRECTION OUTPUT ;
    USE SIGNAL ;
    SHAPE ABUTMENT ;
    PORT
      LAYER metal3 ;
      RECT 373.205 770.000 373.275 770.070 ;
    END
  END r0_rd_out[457]
  PIN r0_rd_out[458]
    DIRECTION OUTPUT ;
    USE SIGNAL ;
    SHAPE ABUTMENT ;
    PORT
      LAYER metal3 ;
      RECT 373.345 770.000 373.415 770.070 ;
    END
  END r0_rd_out[458]
  PIN r0_rd_out[459]
    DIRECTION OUTPUT ;
    USE SIGNAL ;
    SHAPE ABUTMENT ;
    PORT
      LAYER metal3 ;
      RECT 373.485 770.000 373.555 770.070 ;
    END
  END r0_rd_out[459]
  PIN r0_rd_out[460]
    DIRECTION OUTPUT ;
    USE SIGNAL ;
    SHAPE ABUTMENT ;
    PORT
      LAYER metal3 ;
      RECT 373.625 770.000 373.695 770.070 ;
    END
  END r0_rd_out[460]
  PIN r0_rd_out[461]
    DIRECTION OUTPUT ;
    USE SIGNAL ;
    SHAPE ABUTMENT ;
    PORT
      LAYER metal3 ;
      RECT 373.765 770.000 373.835 770.070 ;
    END
  END r0_rd_out[461]
  PIN r0_rd_out[462]
    DIRECTION OUTPUT ;
    USE SIGNAL ;
    SHAPE ABUTMENT ;
    PORT
      LAYER metal3 ;
      RECT 373.905 770.000 373.975 770.070 ;
    END
  END r0_rd_out[462]
  PIN r0_rd_out[463]
    DIRECTION OUTPUT ;
    USE SIGNAL ;
    SHAPE ABUTMENT ;
    PORT
      LAYER metal3 ;
      RECT 374.045 770.000 374.115 770.070 ;
    END
  END r0_rd_out[463]
  PIN r0_rd_out[464]
    DIRECTION OUTPUT ;
    USE SIGNAL ;
    SHAPE ABUTMENT ;
    PORT
      LAYER metal3 ;
      RECT 374.185 770.000 374.255 770.070 ;
    END
  END r0_rd_out[464]
  PIN r0_rd_out[465]
    DIRECTION OUTPUT ;
    USE SIGNAL ;
    SHAPE ABUTMENT ;
    PORT
      LAYER metal3 ;
      RECT 374.325 770.000 374.395 770.070 ;
    END
  END r0_rd_out[465]
  PIN r0_rd_out[466]
    DIRECTION OUTPUT ;
    USE SIGNAL ;
    SHAPE ABUTMENT ;
    PORT
      LAYER metal3 ;
      RECT 374.465 770.000 374.535 770.070 ;
    END
  END r0_rd_out[466]
  PIN r0_rd_out[467]
    DIRECTION OUTPUT ;
    USE SIGNAL ;
    SHAPE ABUTMENT ;
    PORT
      LAYER metal3 ;
      RECT 374.605 770.000 374.675 770.070 ;
    END
  END r0_rd_out[467]
  PIN r0_rd_out[468]
    DIRECTION OUTPUT ;
    USE SIGNAL ;
    SHAPE ABUTMENT ;
    PORT
      LAYER metal3 ;
      RECT 374.745 770.000 374.815 770.070 ;
    END
  END r0_rd_out[468]
  PIN r0_rd_out[469]
    DIRECTION OUTPUT ;
    USE SIGNAL ;
    SHAPE ABUTMENT ;
    PORT
      LAYER metal3 ;
      RECT 374.885 770.000 374.955 770.070 ;
    END
  END r0_rd_out[469]
  PIN r0_rd_out[470]
    DIRECTION OUTPUT ;
    USE SIGNAL ;
    SHAPE ABUTMENT ;
    PORT
      LAYER metal3 ;
      RECT 375.025 770.000 375.095 770.070 ;
    END
  END r0_rd_out[470]
  PIN r0_rd_out[471]
    DIRECTION OUTPUT ;
    USE SIGNAL ;
    SHAPE ABUTMENT ;
    PORT
      LAYER metal3 ;
      RECT 375.165 770.000 375.235 770.070 ;
    END
  END r0_rd_out[471]
  PIN r0_rd_out[472]
    DIRECTION OUTPUT ;
    USE SIGNAL ;
    SHAPE ABUTMENT ;
    PORT
      LAYER metal3 ;
      RECT 375.305 770.000 375.375 770.070 ;
    END
  END r0_rd_out[472]
  PIN r0_rd_out[473]
    DIRECTION OUTPUT ;
    USE SIGNAL ;
    SHAPE ABUTMENT ;
    PORT
      LAYER metal3 ;
      RECT 375.445 770.000 375.515 770.070 ;
    END
  END r0_rd_out[473]
  PIN r0_rd_out[474]
    DIRECTION OUTPUT ;
    USE SIGNAL ;
    SHAPE ABUTMENT ;
    PORT
      LAYER metal3 ;
      RECT 375.585 770.000 375.655 770.070 ;
    END
  END r0_rd_out[474]
  PIN r0_rd_out[475]
    DIRECTION OUTPUT ;
    USE SIGNAL ;
    SHAPE ABUTMENT ;
    PORT
      LAYER metal3 ;
      RECT 375.725 770.000 375.795 770.070 ;
    END
  END r0_rd_out[475]
  PIN r0_rd_out[476]
    DIRECTION OUTPUT ;
    USE SIGNAL ;
    SHAPE ABUTMENT ;
    PORT
      LAYER metal3 ;
      RECT 375.865 770.000 375.935 770.070 ;
    END
  END r0_rd_out[476]
  PIN r0_rd_out[477]
    DIRECTION OUTPUT ;
    USE SIGNAL ;
    SHAPE ABUTMENT ;
    PORT
      LAYER metal3 ;
      RECT 376.005 770.000 376.075 770.070 ;
    END
  END r0_rd_out[477]
  PIN r0_rd_out[478]
    DIRECTION OUTPUT ;
    USE SIGNAL ;
    SHAPE ABUTMENT ;
    PORT
      LAYER metal3 ;
      RECT 376.145 770.000 376.215 770.070 ;
    END
  END r0_rd_out[478]
  PIN r0_rd_out[479]
    DIRECTION OUTPUT ;
    USE SIGNAL ;
    SHAPE ABUTMENT ;
    PORT
      LAYER metal3 ;
      RECT 376.285 770.000 376.355 770.070 ;
    END
  END r0_rd_out[479]
  PIN r0_rd_out[480]
    DIRECTION OUTPUT ;
    USE SIGNAL ;
    SHAPE ABUTMENT ;
    PORT
      LAYER metal3 ;
      RECT 376.425 770.000 376.495 770.070 ;
    END
  END r0_rd_out[480]
  PIN r0_rd_out[481]
    DIRECTION OUTPUT ;
    USE SIGNAL ;
    SHAPE ABUTMENT ;
    PORT
      LAYER metal3 ;
      RECT 376.565 770.000 376.635 770.070 ;
    END
  END r0_rd_out[481]
  PIN r0_rd_out[482]
    DIRECTION OUTPUT ;
    USE SIGNAL ;
    SHAPE ABUTMENT ;
    PORT
      LAYER metal3 ;
      RECT 376.705 770.000 376.775 770.070 ;
    END
  END r0_rd_out[482]
  PIN r0_rd_out[483]
    DIRECTION OUTPUT ;
    USE SIGNAL ;
    SHAPE ABUTMENT ;
    PORT
      LAYER metal3 ;
      RECT 376.845 770.000 376.915 770.070 ;
    END
  END r0_rd_out[483]
  PIN r0_rd_out[484]
    DIRECTION OUTPUT ;
    USE SIGNAL ;
    SHAPE ABUTMENT ;
    PORT
      LAYER metal3 ;
      RECT 376.985 770.000 377.055 770.070 ;
    END
  END r0_rd_out[484]
  PIN r0_rd_out[485]
    DIRECTION OUTPUT ;
    USE SIGNAL ;
    SHAPE ABUTMENT ;
    PORT
      LAYER metal3 ;
      RECT 377.125 770.000 377.195 770.070 ;
    END
  END r0_rd_out[485]
  PIN r0_rd_out[486]
    DIRECTION OUTPUT ;
    USE SIGNAL ;
    SHAPE ABUTMENT ;
    PORT
      LAYER metal3 ;
      RECT 377.265 770.000 377.335 770.070 ;
    END
  END r0_rd_out[486]
  PIN r0_rd_out[487]
    DIRECTION OUTPUT ;
    USE SIGNAL ;
    SHAPE ABUTMENT ;
    PORT
      LAYER metal3 ;
      RECT 377.405 770.000 377.475 770.070 ;
    END
  END r0_rd_out[487]
  PIN r0_rd_out[488]
    DIRECTION OUTPUT ;
    USE SIGNAL ;
    SHAPE ABUTMENT ;
    PORT
      LAYER metal3 ;
      RECT 377.545 770.000 377.615 770.070 ;
    END
  END r0_rd_out[488]
  PIN r0_rd_out[489]
    DIRECTION OUTPUT ;
    USE SIGNAL ;
    SHAPE ABUTMENT ;
    PORT
      LAYER metal3 ;
      RECT 377.685 770.000 377.755 770.070 ;
    END
  END r0_rd_out[489]
  PIN r0_rd_out[490]
    DIRECTION OUTPUT ;
    USE SIGNAL ;
    SHAPE ABUTMENT ;
    PORT
      LAYER metal3 ;
      RECT 377.825 770.000 377.895 770.070 ;
    END
  END r0_rd_out[490]
  PIN r0_rd_out[491]
    DIRECTION OUTPUT ;
    USE SIGNAL ;
    SHAPE ABUTMENT ;
    PORT
      LAYER metal3 ;
      RECT 377.965 770.000 378.035 770.070 ;
    END
  END r0_rd_out[491]
  PIN r0_rd_out[492]
    DIRECTION OUTPUT ;
    USE SIGNAL ;
    SHAPE ABUTMENT ;
    PORT
      LAYER metal3 ;
      RECT 378.105 770.000 378.175 770.070 ;
    END
  END r0_rd_out[492]
  PIN r0_rd_out[493]
    DIRECTION OUTPUT ;
    USE SIGNAL ;
    SHAPE ABUTMENT ;
    PORT
      LAYER metal3 ;
      RECT 378.245 770.000 378.315 770.070 ;
    END
  END r0_rd_out[493]
  PIN r0_rd_out[494]
    DIRECTION OUTPUT ;
    USE SIGNAL ;
    SHAPE ABUTMENT ;
    PORT
      LAYER metal3 ;
      RECT 378.385 770.000 378.455 770.070 ;
    END
  END r0_rd_out[494]
  PIN r0_rd_out[495]
    DIRECTION OUTPUT ;
    USE SIGNAL ;
    SHAPE ABUTMENT ;
    PORT
      LAYER metal3 ;
      RECT 378.525 770.000 378.595 770.070 ;
    END
  END r0_rd_out[495]
  PIN r0_rd_out[496]
    DIRECTION OUTPUT ;
    USE SIGNAL ;
    SHAPE ABUTMENT ;
    PORT
      LAYER metal3 ;
      RECT 378.665 770.000 378.735 770.070 ;
    END
  END r0_rd_out[496]
  PIN r0_rd_out[497]
    DIRECTION OUTPUT ;
    USE SIGNAL ;
    SHAPE ABUTMENT ;
    PORT
      LAYER metal3 ;
      RECT 378.805 770.000 378.875 770.070 ;
    END
  END r0_rd_out[497]
  PIN r0_rd_out[498]
    DIRECTION OUTPUT ;
    USE SIGNAL ;
    SHAPE ABUTMENT ;
    PORT
      LAYER metal3 ;
      RECT 378.945 770.000 379.015 770.070 ;
    END
  END r0_rd_out[498]
  PIN r0_rd_out[499]
    DIRECTION OUTPUT ;
    USE SIGNAL ;
    SHAPE ABUTMENT ;
    PORT
      LAYER metal3 ;
      RECT 379.085 770.000 379.155 770.070 ;
    END
  END r0_rd_out[499]
  PIN r0_rd_out[500]
    DIRECTION OUTPUT ;
    USE SIGNAL ;
    SHAPE ABUTMENT ;
    PORT
      LAYER metal3 ;
      RECT 379.225 770.000 379.295 770.070 ;
    END
  END r0_rd_out[500]
  PIN r0_rd_out[501]
    DIRECTION OUTPUT ;
    USE SIGNAL ;
    SHAPE ABUTMENT ;
    PORT
      LAYER metal3 ;
      RECT 379.365 770.000 379.435 770.070 ;
    END
  END r0_rd_out[501]
  PIN r0_rd_out[502]
    DIRECTION OUTPUT ;
    USE SIGNAL ;
    SHAPE ABUTMENT ;
    PORT
      LAYER metal3 ;
      RECT 379.505 770.000 379.575 770.070 ;
    END
  END r0_rd_out[502]
  PIN r0_rd_out[503]
    DIRECTION OUTPUT ;
    USE SIGNAL ;
    SHAPE ABUTMENT ;
    PORT
      LAYER metal3 ;
      RECT 379.645 770.000 379.715 770.070 ;
    END
  END r0_rd_out[503]
  PIN r0_rd_out[504]
    DIRECTION OUTPUT ;
    USE SIGNAL ;
    SHAPE ABUTMENT ;
    PORT
      LAYER metal3 ;
      RECT 379.785 770.000 379.855 770.070 ;
    END
  END r0_rd_out[504]
  PIN r0_rd_out[505]
    DIRECTION OUTPUT ;
    USE SIGNAL ;
    SHAPE ABUTMENT ;
    PORT
      LAYER metal3 ;
      RECT 379.925 770.000 379.995 770.070 ;
    END
  END r0_rd_out[505]
  PIN r0_rd_out[506]
    DIRECTION OUTPUT ;
    USE SIGNAL ;
    SHAPE ABUTMENT ;
    PORT
      LAYER metal3 ;
      RECT 380.065 770.000 380.135 770.070 ;
    END
  END r0_rd_out[506]
  PIN r0_rd_out[507]
    DIRECTION OUTPUT ;
    USE SIGNAL ;
    SHAPE ABUTMENT ;
    PORT
      LAYER metal3 ;
      RECT 380.205 770.000 380.275 770.070 ;
    END
  END r0_rd_out[507]
  PIN r0_rd_out[508]
    DIRECTION OUTPUT ;
    USE SIGNAL ;
    SHAPE ABUTMENT ;
    PORT
      LAYER metal3 ;
      RECT 380.345 770.000 380.415 770.070 ;
    END
  END r0_rd_out[508]
  PIN r0_rd_out[509]
    DIRECTION OUTPUT ;
    USE SIGNAL ;
    SHAPE ABUTMENT ;
    PORT
      LAYER metal3 ;
      RECT 380.485 770.000 380.555 770.070 ;
    END
  END r0_rd_out[509]
  PIN r0_rd_out[510]
    DIRECTION OUTPUT ;
    USE SIGNAL ;
    SHAPE ABUTMENT ;
    PORT
      LAYER metal3 ;
      RECT 380.625 770.000 380.695 770.070 ;
    END
  END r0_rd_out[510]
  PIN r0_rd_out[511]
    DIRECTION OUTPUT ;
    USE SIGNAL ;
    SHAPE ABUTMENT ;
    PORT
      LAYER metal3 ;
      RECT 380.765 770.000 380.835 770.070 ;
    END
  END r0_rd_out[511]
  PIN w0_addr_in[0]
    DIRECTION INPUT ;
    USE SIGNAL ;
    SHAPE ABUTMENT ;
    PORT
      LAYER metal3 ;
      RECT 690.270 384.160 690.340 384.230 ;
    END
  END w0_addr_in[0]
  PIN w0_addr_in[1]
    DIRECTION INPUT ;
    USE SIGNAL ;
    SHAPE ABUTMENT ;
    PORT
      LAYER metal3 ;
      RECT 690.270 384.300 690.340 384.370 ;
    END
  END w0_addr_in[1]
  PIN w0_addr_in[2]
    DIRECTION INPUT ;
    USE SIGNAL ;
    SHAPE ABUTMENT ;
    PORT
      LAYER metal3 ;
      RECT 690.270 384.440 690.340 384.510 ;
    END
  END w0_addr_in[2]
  PIN w0_addr_in[3]
    DIRECTION INPUT ;
    USE SIGNAL ;
    SHAPE ABUTMENT ;
    PORT
      LAYER metal3 ;
      RECT 690.270 384.580 690.340 384.650 ;
    END
  END w0_addr_in[3]
  PIN w0_addr_in[4]
    DIRECTION INPUT ;
    USE SIGNAL ;
    SHAPE ABUTMENT ;
    PORT
      LAYER metal3 ;
      RECT 690.270 384.720 690.340 384.790 ;
    END
  END w0_addr_in[4]
  PIN w0_addr_in[5]
    DIRECTION INPUT ;
    USE SIGNAL ;
    SHAPE ABUTMENT ;
    PORT
      LAYER metal3 ;
      RECT 690.270 384.860 690.340 384.930 ;
    END
  END w0_addr_in[5]
  PIN w0_addr_in[6]
    DIRECTION INPUT ;
    USE SIGNAL ;
    SHAPE ABUTMENT ;
    PORT
      LAYER metal3 ;
      RECT 690.270 385.000 690.340 385.070 ;
    END
  END w0_addr_in[6]
  PIN w0_addr_in[7]
    DIRECTION INPUT ;
    USE SIGNAL ;
    SHAPE ABUTMENT ;
    PORT
      LAYER metal3 ;
      RECT 690.270 385.140 690.340 385.210 ;
    END
  END w0_addr_in[7]
  PIN w0_we_in
    DIRECTION INPUT ;
    USE SIGNAL ;
    SHAPE ABUTMENT ;
    PORT
      LAYER metal3 ;
      RECT 690.270 385.420 690.340 385.490 ;
    END
  END w0_we_in
  PIN w0_ce_in
    DIRECTION INPUT ;
    USE SIGNAL ;
    SHAPE ABUTMENT ;
    PORT
      LAYER metal3 ;
      RECT 690.270 385.560 690.340 385.630 ;
    END
  END w0_ce_in
  PIN w0_clk
    DIRECTION INPUT ;
    USE SIGNAL ;
    SHAPE ABUTMENT ;
    PORT
      LAYER metal3 ;
      RECT 690.270 385.700 690.340 385.770 ;
    END
  END w0_clk
  PIN w0_wd_in[0]
    DIRECTION INPUT ;
    USE SIGNAL ;
    SHAPE ABUTMENT ;
    PORT
      LAYER metal3 ;
      RECT 309.225 0.000 309.295 0.070 ;
    END
  END w0_wd_in[0]
  PIN w0_wd_in[1]
    DIRECTION INPUT ;
    USE SIGNAL ;
    SHAPE ABUTMENT ;
    PORT
      LAYER metal3 ;
      RECT 309.365 0.000 309.435 0.070 ;
    END
  END w0_wd_in[1]
  PIN w0_wd_in[2]
    DIRECTION INPUT ;
    USE SIGNAL ;
    SHAPE ABUTMENT ;
    PORT
      LAYER metal3 ;
      RECT 309.505 0.000 309.575 0.070 ;
    END
  END w0_wd_in[2]
  PIN w0_wd_in[3]
    DIRECTION INPUT ;
    USE SIGNAL ;
    SHAPE ABUTMENT ;
    PORT
      LAYER metal3 ;
      RECT 309.645 0.000 309.715 0.070 ;
    END
  END w0_wd_in[3]
  PIN w0_wd_in[4]
    DIRECTION INPUT ;
    USE SIGNAL ;
    SHAPE ABUTMENT ;
    PORT
      LAYER metal3 ;
      RECT 309.785 0.000 309.855 0.070 ;
    END
  END w0_wd_in[4]
  PIN w0_wd_in[5]
    DIRECTION INPUT ;
    USE SIGNAL ;
    SHAPE ABUTMENT ;
    PORT
      LAYER metal3 ;
      RECT 309.925 0.000 309.995 0.070 ;
    END
  END w0_wd_in[5]
  PIN w0_wd_in[6]
    DIRECTION INPUT ;
    USE SIGNAL ;
    SHAPE ABUTMENT ;
    PORT
      LAYER metal3 ;
      RECT 310.065 0.000 310.135 0.070 ;
    END
  END w0_wd_in[6]
  PIN w0_wd_in[7]
    DIRECTION INPUT ;
    USE SIGNAL ;
    SHAPE ABUTMENT ;
    PORT
      LAYER metal3 ;
      RECT 310.205 0.000 310.275 0.070 ;
    END
  END w0_wd_in[7]
  PIN w0_wd_in[8]
    DIRECTION INPUT ;
    USE SIGNAL ;
    SHAPE ABUTMENT ;
    PORT
      LAYER metal3 ;
      RECT 310.345 0.000 310.415 0.070 ;
    END
  END w0_wd_in[8]
  PIN w0_wd_in[9]
    DIRECTION INPUT ;
    USE SIGNAL ;
    SHAPE ABUTMENT ;
    PORT
      LAYER metal3 ;
      RECT 310.485 0.000 310.555 0.070 ;
    END
  END w0_wd_in[9]
  PIN w0_wd_in[10]
    DIRECTION INPUT ;
    USE SIGNAL ;
    SHAPE ABUTMENT ;
    PORT
      LAYER metal3 ;
      RECT 310.625 0.000 310.695 0.070 ;
    END
  END w0_wd_in[10]
  PIN w0_wd_in[11]
    DIRECTION INPUT ;
    USE SIGNAL ;
    SHAPE ABUTMENT ;
    PORT
      LAYER metal3 ;
      RECT 310.765 0.000 310.835 0.070 ;
    END
  END w0_wd_in[11]
  PIN w0_wd_in[12]
    DIRECTION INPUT ;
    USE SIGNAL ;
    SHAPE ABUTMENT ;
    PORT
      LAYER metal3 ;
      RECT 310.905 0.000 310.975 0.070 ;
    END
  END w0_wd_in[12]
  PIN w0_wd_in[13]
    DIRECTION INPUT ;
    USE SIGNAL ;
    SHAPE ABUTMENT ;
    PORT
      LAYER metal3 ;
      RECT 311.045 0.000 311.115 0.070 ;
    END
  END w0_wd_in[13]
  PIN w0_wd_in[14]
    DIRECTION INPUT ;
    USE SIGNAL ;
    SHAPE ABUTMENT ;
    PORT
      LAYER metal3 ;
      RECT 311.185 0.000 311.255 0.070 ;
    END
  END w0_wd_in[14]
  PIN w0_wd_in[15]
    DIRECTION INPUT ;
    USE SIGNAL ;
    SHAPE ABUTMENT ;
    PORT
      LAYER metal3 ;
      RECT 311.325 0.000 311.395 0.070 ;
    END
  END w0_wd_in[15]
  PIN w0_wd_in[16]
    DIRECTION INPUT ;
    USE SIGNAL ;
    SHAPE ABUTMENT ;
    PORT
      LAYER metal3 ;
      RECT 311.465 0.000 311.535 0.070 ;
    END
  END w0_wd_in[16]
  PIN w0_wd_in[17]
    DIRECTION INPUT ;
    USE SIGNAL ;
    SHAPE ABUTMENT ;
    PORT
      LAYER metal3 ;
      RECT 311.605 0.000 311.675 0.070 ;
    END
  END w0_wd_in[17]
  PIN w0_wd_in[18]
    DIRECTION INPUT ;
    USE SIGNAL ;
    SHAPE ABUTMENT ;
    PORT
      LAYER metal3 ;
      RECT 311.745 0.000 311.815 0.070 ;
    END
  END w0_wd_in[18]
  PIN w0_wd_in[19]
    DIRECTION INPUT ;
    USE SIGNAL ;
    SHAPE ABUTMENT ;
    PORT
      LAYER metal3 ;
      RECT 311.885 0.000 311.955 0.070 ;
    END
  END w0_wd_in[19]
  PIN w0_wd_in[20]
    DIRECTION INPUT ;
    USE SIGNAL ;
    SHAPE ABUTMENT ;
    PORT
      LAYER metal3 ;
      RECT 312.025 0.000 312.095 0.070 ;
    END
  END w0_wd_in[20]
  PIN w0_wd_in[21]
    DIRECTION INPUT ;
    USE SIGNAL ;
    SHAPE ABUTMENT ;
    PORT
      LAYER metal3 ;
      RECT 312.165 0.000 312.235 0.070 ;
    END
  END w0_wd_in[21]
  PIN w0_wd_in[22]
    DIRECTION INPUT ;
    USE SIGNAL ;
    SHAPE ABUTMENT ;
    PORT
      LAYER metal3 ;
      RECT 312.305 0.000 312.375 0.070 ;
    END
  END w0_wd_in[22]
  PIN w0_wd_in[23]
    DIRECTION INPUT ;
    USE SIGNAL ;
    SHAPE ABUTMENT ;
    PORT
      LAYER metal3 ;
      RECT 312.445 0.000 312.515 0.070 ;
    END
  END w0_wd_in[23]
  PIN w0_wd_in[24]
    DIRECTION INPUT ;
    USE SIGNAL ;
    SHAPE ABUTMENT ;
    PORT
      LAYER metal3 ;
      RECT 312.585 0.000 312.655 0.070 ;
    END
  END w0_wd_in[24]
  PIN w0_wd_in[25]
    DIRECTION INPUT ;
    USE SIGNAL ;
    SHAPE ABUTMENT ;
    PORT
      LAYER metal3 ;
      RECT 312.725 0.000 312.795 0.070 ;
    END
  END w0_wd_in[25]
  PIN w0_wd_in[26]
    DIRECTION INPUT ;
    USE SIGNAL ;
    SHAPE ABUTMENT ;
    PORT
      LAYER metal3 ;
      RECT 312.865 0.000 312.935 0.070 ;
    END
  END w0_wd_in[26]
  PIN w0_wd_in[27]
    DIRECTION INPUT ;
    USE SIGNAL ;
    SHAPE ABUTMENT ;
    PORT
      LAYER metal3 ;
      RECT 313.005 0.000 313.075 0.070 ;
    END
  END w0_wd_in[27]
  PIN w0_wd_in[28]
    DIRECTION INPUT ;
    USE SIGNAL ;
    SHAPE ABUTMENT ;
    PORT
      LAYER metal3 ;
      RECT 313.145 0.000 313.215 0.070 ;
    END
  END w0_wd_in[28]
  PIN w0_wd_in[29]
    DIRECTION INPUT ;
    USE SIGNAL ;
    SHAPE ABUTMENT ;
    PORT
      LAYER metal3 ;
      RECT 313.285 0.000 313.355 0.070 ;
    END
  END w0_wd_in[29]
  PIN w0_wd_in[30]
    DIRECTION INPUT ;
    USE SIGNAL ;
    SHAPE ABUTMENT ;
    PORT
      LAYER metal3 ;
      RECT 313.425 0.000 313.495 0.070 ;
    END
  END w0_wd_in[30]
  PIN w0_wd_in[31]
    DIRECTION INPUT ;
    USE SIGNAL ;
    SHAPE ABUTMENT ;
    PORT
      LAYER metal3 ;
      RECT 313.565 0.000 313.635 0.070 ;
    END
  END w0_wd_in[31]
  PIN w0_wd_in[32]
    DIRECTION INPUT ;
    USE SIGNAL ;
    SHAPE ABUTMENT ;
    PORT
      LAYER metal3 ;
      RECT 313.705 0.000 313.775 0.070 ;
    END
  END w0_wd_in[32]
  PIN w0_wd_in[33]
    DIRECTION INPUT ;
    USE SIGNAL ;
    SHAPE ABUTMENT ;
    PORT
      LAYER metal3 ;
      RECT 313.845 0.000 313.915 0.070 ;
    END
  END w0_wd_in[33]
  PIN w0_wd_in[34]
    DIRECTION INPUT ;
    USE SIGNAL ;
    SHAPE ABUTMENT ;
    PORT
      LAYER metal3 ;
      RECT 313.985 0.000 314.055 0.070 ;
    END
  END w0_wd_in[34]
  PIN w0_wd_in[35]
    DIRECTION INPUT ;
    USE SIGNAL ;
    SHAPE ABUTMENT ;
    PORT
      LAYER metal3 ;
      RECT 314.125 0.000 314.195 0.070 ;
    END
  END w0_wd_in[35]
  PIN w0_wd_in[36]
    DIRECTION INPUT ;
    USE SIGNAL ;
    SHAPE ABUTMENT ;
    PORT
      LAYER metal3 ;
      RECT 314.265 0.000 314.335 0.070 ;
    END
  END w0_wd_in[36]
  PIN w0_wd_in[37]
    DIRECTION INPUT ;
    USE SIGNAL ;
    SHAPE ABUTMENT ;
    PORT
      LAYER metal3 ;
      RECT 314.405 0.000 314.475 0.070 ;
    END
  END w0_wd_in[37]
  PIN w0_wd_in[38]
    DIRECTION INPUT ;
    USE SIGNAL ;
    SHAPE ABUTMENT ;
    PORT
      LAYER metal3 ;
      RECT 314.545 0.000 314.615 0.070 ;
    END
  END w0_wd_in[38]
  PIN w0_wd_in[39]
    DIRECTION INPUT ;
    USE SIGNAL ;
    SHAPE ABUTMENT ;
    PORT
      LAYER metal3 ;
      RECT 314.685 0.000 314.755 0.070 ;
    END
  END w0_wd_in[39]
  PIN w0_wd_in[40]
    DIRECTION INPUT ;
    USE SIGNAL ;
    SHAPE ABUTMENT ;
    PORT
      LAYER metal3 ;
      RECT 314.825 0.000 314.895 0.070 ;
    END
  END w0_wd_in[40]
  PIN w0_wd_in[41]
    DIRECTION INPUT ;
    USE SIGNAL ;
    SHAPE ABUTMENT ;
    PORT
      LAYER metal3 ;
      RECT 314.965 0.000 315.035 0.070 ;
    END
  END w0_wd_in[41]
  PIN w0_wd_in[42]
    DIRECTION INPUT ;
    USE SIGNAL ;
    SHAPE ABUTMENT ;
    PORT
      LAYER metal3 ;
      RECT 315.105 0.000 315.175 0.070 ;
    END
  END w0_wd_in[42]
  PIN w0_wd_in[43]
    DIRECTION INPUT ;
    USE SIGNAL ;
    SHAPE ABUTMENT ;
    PORT
      LAYER metal3 ;
      RECT 315.245 0.000 315.315 0.070 ;
    END
  END w0_wd_in[43]
  PIN w0_wd_in[44]
    DIRECTION INPUT ;
    USE SIGNAL ;
    SHAPE ABUTMENT ;
    PORT
      LAYER metal3 ;
      RECT 315.385 0.000 315.455 0.070 ;
    END
  END w0_wd_in[44]
  PIN w0_wd_in[45]
    DIRECTION INPUT ;
    USE SIGNAL ;
    SHAPE ABUTMENT ;
    PORT
      LAYER metal3 ;
      RECT 315.525 0.000 315.595 0.070 ;
    END
  END w0_wd_in[45]
  PIN w0_wd_in[46]
    DIRECTION INPUT ;
    USE SIGNAL ;
    SHAPE ABUTMENT ;
    PORT
      LAYER metal3 ;
      RECT 315.665 0.000 315.735 0.070 ;
    END
  END w0_wd_in[46]
  PIN w0_wd_in[47]
    DIRECTION INPUT ;
    USE SIGNAL ;
    SHAPE ABUTMENT ;
    PORT
      LAYER metal3 ;
      RECT 315.805 0.000 315.875 0.070 ;
    END
  END w0_wd_in[47]
  PIN w0_wd_in[48]
    DIRECTION INPUT ;
    USE SIGNAL ;
    SHAPE ABUTMENT ;
    PORT
      LAYER metal3 ;
      RECT 315.945 0.000 316.015 0.070 ;
    END
  END w0_wd_in[48]
  PIN w0_wd_in[49]
    DIRECTION INPUT ;
    USE SIGNAL ;
    SHAPE ABUTMENT ;
    PORT
      LAYER metal3 ;
      RECT 316.085 0.000 316.155 0.070 ;
    END
  END w0_wd_in[49]
  PIN w0_wd_in[50]
    DIRECTION INPUT ;
    USE SIGNAL ;
    SHAPE ABUTMENT ;
    PORT
      LAYER metal3 ;
      RECT 316.225 0.000 316.295 0.070 ;
    END
  END w0_wd_in[50]
  PIN w0_wd_in[51]
    DIRECTION INPUT ;
    USE SIGNAL ;
    SHAPE ABUTMENT ;
    PORT
      LAYER metal3 ;
      RECT 316.365 0.000 316.435 0.070 ;
    END
  END w0_wd_in[51]
  PIN w0_wd_in[52]
    DIRECTION INPUT ;
    USE SIGNAL ;
    SHAPE ABUTMENT ;
    PORT
      LAYER metal3 ;
      RECT 316.505 0.000 316.575 0.070 ;
    END
  END w0_wd_in[52]
  PIN w0_wd_in[53]
    DIRECTION INPUT ;
    USE SIGNAL ;
    SHAPE ABUTMENT ;
    PORT
      LAYER metal3 ;
      RECT 316.645 0.000 316.715 0.070 ;
    END
  END w0_wd_in[53]
  PIN w0_wd_in[54]
    DIRECTION INPUT ;
    USE SIGNAL ;
    SHAPE ABUTMENT ;
    PORT
      LAYER metal3 ;
      RECT 316.785 0.000 316.855 0.070 ;
    END
  END w0_wd_in[54]
  PIN w0_wd_in[55]
    DIRECTION INPUT ;
    USE SIGNAL ;
    SHAPE ABUTMENT ;
    PORT
      LAYER metal3 ;
      RECT 316.925 0.000 316.995 0.070 ;
    END
  END w0_wd_in[55]
  PIN w0_wd_in[56]
    DIRECTION INPUT ;
    USE SIGNAL ;
    SHAPE ABUTMENT ;
    PORT
      LAYER metal3 ;
      RECT 317.065 0.000 317.135 0.070 ;
    END
  END w0_wd_in[56]
  PIN w0_wd_in[57]
    DIRECTION INPUT ;
    USE SIGNAL ;
    SHAPE ABUTMENT ;
    PORT
      LAYER metal3 ;
      RECT 317.205 0.000 317.275 0.070 ;
    END
  END w0_wd_in[57]
  PIN w0_wd_in[58]
    DIRECTION INPUT ;
    USE SIGNAL ;
    SHAPE ABUTMENT ;
    PORT
      LAYER metal3 ;
      RECT 317.345 0.000 317.415 0.070 ;
    END
  END w0_wd_in[58]
  PIN w0_wd_in[59]
    DIRECTION INPUT ;
    USE SIGNAL ;
    SHAPE ABUTMENT ;
    PORT
      LAYER metal3 ;
      RECT 317.485 0.000 317.555 0.070 ;
    END
  END w0_wd_in[59]
  PIN w0_wd_in[60]
    DIRECTION INPUT ;
    USE SIGNAL ;
    SHAPE ABUTMENT ;
    PORT
      LAYER metal3 ;
      RECT 317.625 0.000 317.695 0.070 ;
    END
  END w0_wd_in[60]
  PIN w0_wd_in[61]
    DIRECTION INPUT ;
    USE SIGNAL ;
    SHAPE ABUTMENT ;
    PORT
      LAYER metal3 ;
      RECT 317.765 0.000 317.835 0.070 ;
    END
  END w0_wd_in[61]
  PIN w0_wd_in[62]
    DIRECTION INPUT ;
    USE SIGNAL ;
    SHAPE ABUTMENT ;
    PORT
      LAYER metal3 ;
      RECT 317.905 0.000 317.975 0.070 ;
    END
  END w0_wd_in[62]
  PIN w0_wd_in[63]
    DIRECTION INPUT ;
    USE SIGNAL ;
    SHAPE ABUTMENT ;
    PORT
      LAYER metal3 ;
      RECT 318.045 0.000 318.115 0.070 ;
    END
  END w0_wd_in[63]
  PIN w0_wd_in[64]
    DIRECTION INPUT ;
    USE SIGNAL ;
    SHAPE ABUTMENT ;
    PORT
      LAYER metal3 ;
      RECT 318.185 0.000 318.255 0.070 ;
    END
  END w0_wd_in[64]
  PIN w0_wd_in[65]
    DIRECTION INPUT ;
    USE SIGNAL ;
    SHAPE ABUTMENT ;
    PORT
      LAYER metal3 ;
      RECT 318.325 0.000 318.395 0.070 ;
    END
  END w0_wd_in[65]
  PIN w0_wd_in[66]
    DIRECTION INPUT ;
    USE SIGNAL ;
    SHAPE ABUTMENT ;
    PORT
      LAYER metal3 ;
      RECT 318.465 0.000 318.535 0.070 ;
    END
  END w0_wd_in[66]
  PIN w0_wd_in[67]
    DIRECTION INPUT ;
    USE SIGNAL ;
    SHAPE ABUTMENT ;
    PORT
      LAYER metal3 ;
      RECT 318.605 0.000 318.675 0.070 ;
    END
  END w0_wd_in[67]
  PIN w0_wd_in[68]
    DIRECTION INPUT ;
    USE SIGNAL ;
    SHAPE ABUTMENT ;
    PORT
      LAYER metal3 ;
      RECT 318.745 0.000 318.815 0.070 ;
    END
  END w0_wd_in[68]
  PIN w0_wd_in[69]
    DIRECTION INPUT ;
    USE SIGNAL ;
    SHAPE ABUTMENT ;
    PORT
      LAYER metal3 ;
      RECT 318.885 0.000 318.955 0.070 ;
    END
  END w0_wd_in[69]
  PIN w0_wd_in[70]
    DIRECTION INPUT ;
    USE SIGNAL ;
    SHAPE ABUTMENT ;
    PORT
      LAYER metal3 ;
      RECT 319.025 0.000 319.095 0.070 ;
    END
  END w0_wd_in[70]
  PIN w0_wd_in[71]
    DIRECTION INPUT ;
    USE SIGNAL ;
    SHAPE ABUTMENT ;
    PORT
      LAYER metal3 ;
      RECT 319.165 0.000 319.235 0.070 ;
    END
  END w0_wd_in[71]
  PIN w0_wd_in[72]
    DIRECTION INPUT ;
    USE SIGNAL ;
    SHAPE ABUTMENT ;
    PORT
      LAYER metal3 ;
      RECT 319.305 0.000 319.375 0.070 ;
    END
  END w0_wd_in[72]
  PIN w0_wd_in[73]
    DIRECTION INPUT ;
    USE SIGNAL ;
    SHAPE ABUTMENT ;
    PORT
      LAYER metal3 ;
      RECT 319.445 0.000 319.515 0.070 ;
    END
  END w0_wd_in[73]
  PIN w0_wd_in[74]
    DIRECTION INPUT ;
    USE SIGNAL ;
    SHAPE ABUTMENT ;
    PORT
      LAYER metal3 ;
      RECT 319.585 0.000 319.655 0.070 ;
    END
  END w0_wd_in[74]
  PIN w0_wd_in[75]
    DIRECTION INPUT ;
    USE SIGNAL ;
    SHAPE ABUTMENT ;
    PORT
      LAYER metal3 ;
      RECT 319.725 0.000 319.795 0.070 ;
    END
  END w0_wd_in[75]
  PIN w0_wd_in[76]
    DIRECTION INPUT ;
    USE SIGNAL ;
    SHAPE ABUTMENT ;
    PORT
      LAYER metal3 ;
      RECT 319.865 0.000 319.935 0.070 ;
    END
  END w0_wd_in[76]
  PIN w0_wd_in[77]
    DIRECTION INPUT ;
    USE SIGNAL ;
    SHAPE ABUTMENT ;
    PORT
      LAYER metal3 ;
      RECT 320.005 0.000 320.075 0.070 ;
    END
  END w0_wd_in[77]
  PIN w0_wd_in[78]
    DIRECTION INPUT ;
    USE SIGNAL ;
    SHAPE ABUTMENT ;
    PORT
      LAYER metal3 ;
      RECT 320.145 0.000 320.215 0.070 ;
    END
  END w0_wd_in[78]
  PIN w0_wd_in[79]
    DIRECTION INPUT ;
    USE SIGNAL ;
    SHAPE ABUTMENT ;
    PORT
      LAYER metal3 ;
      RECT 320.285 0.000 320.355 0.070 ;
    END
  END w0_wd_in[79]
  PIN w0_wd_in[80]
    DIRECTION INPUT ;
    USE SIGNAL ;
    SHAPE ABUTMENT ;
    PORT
      LAYER metal3 ;
      RECT 320.425 0.000 320.495 0.070 ;
    END
  END w0_wd_in[80]
  PIN w0_wd_in[81]
    DIRECTION INPUT ;
    USE SIGNAL ;
    SHAPE ABUTMENT ;
    PORT
      LAYER metal3 ;
      RECT 320.565 0.000 320.635 0.070 ;
    END
  END w0_wd_in[81]
  PIN w0_wd_in[82]
    DIRECTION INPUT ;
    USE SIGNAL ;
    SHAPE ABUTMENT ;
    PORT
      LAYER metal3 ;
      RECT 320.705 0.000 320.775 0.070 ;
    END
  END w0_wd_in[82]
  PIN w0_wd_in[83]
    DIRECTION INPUT ;
    USE SIGNAL ;
    SHAPE ABUTMENT ;
    PORT
      LAYER metal3 ;
      RECT 320.845 0.000 320.915 0.070 ;
    END
  END w0_wd_in[83]
  PIN w0_wd_in[84]
    DIRECTION INPUT ;
    USE SIGNAL ;
    SHAPE ABUTMENT ;
    PORT
      LAYER metal3 ;
      RECT 320.985 0.000 321.055 0.070 ;
    END
  END w0_wd_in[84]
  PIN w0_wd_in[85]
    DIRECTION INPUT ;
    USE SIGNAL ;
    SHAPE ABUTMENT ;
    PORT
      LAYER metal3 ;
      RECT 321.125 0.000 321.195 0.070 ;
    END
  END w0_wd_in[85]
  PIN w0_wd_in[86]
    DIRECTION INPUT ;
    USE SIGNAL ;
    SHAPE ABUTMENT ;
    PORT
      LAYER metal3 ;
      RECT 321.265 0.000 321.335 0.070 ;
    END
  END w0_wd_in[86]
  PIN w0_wd_in[87]
    DIRECTION INPUT ;
    USE SIGNAL ;
    SHAPE ABUTMENT ;
    PORT
      LAYER metal3 ;
      RECT 321.405 0.000 321.475 0.070 ;
    END
  END w0_wd_in[87]
  PIN w0_wd_in[88]
    DIRECTION INPUT ;
    USE SIGNAL ;
    SHAPE ABUTMENT ;
    PORT
      LAYER metal3 ;
      RECT 321.545 0.000 321.615 0.070 ;
    END
  END w0_wd_in[88]
  PIN w0_wd_in[89]
    DIRECTION INPUT ;
    USE SIGNAL ;
    SHAPE ABUTMENT ;
    PORT
      LAYER metal3 ;
      RECT 321.685 0.000 321.755 0.070 ;
    END
  END w0_wd_in[89]
  PIN w0_wd_in[90]
    DIRECTION INPUT ;
    USE SIGNAL ;
    SHAPE ABUTMENT ;
    PORT
      LAYER metal3 ;
      RECT 321.825 0.000 321.895 0.070 ;
    END
  END w0_wd_in[90]
  PIN w0_wd_in[91]
    DIRECTION INPUT ;
    USE SIGNAL ;
    SHAPE ABUTMENT ;
    PORT
      LAYER metal3 ;
      RECT 321.965 0.000 322.035 0.070 ;
    END
  END w0_wd_in[91]
  PIN w0_wd_in[92]
    DIRECTION INPUT ;
    USE SIGNAL ;
    SHAPE ABUTMENT ;
    PORT
      LAYER metal3 ;
      RECT 322.105 0.000 322.175 0.070 ;
    END
  END w0_wd_in[92]
  PIN w0_wd_in[93]
    DIRECTION INPUT ;
    USE SIGNAL ;
    SHAPE ABUTMENT ;
    PORT
      LAYER metal3 ;
      RECT 322.245 0.000 322.315 0.070 ;
    END
  END w0_wd_in[93]
  PIN w0_wd_in[94]
    DIRECTION INPUT ;
    USE SIGNAL ;
    SHAPE ABUTMENT ;
    PORT
      LAYER metal3 ;
      RECT 322.385 0.000 322.455 0.070 ;
    END
  END w0_wd_in[94]
  PIN w0_wd_in[95]
    DIRECTION INPUT ;
    USE SIGNAL ;
    SHAPE ABUTMENT ;
    PORT
      LAYER metal3 ;
      RECT 322.525 0.000 322.595 0.070 ;
    END
  END w0_wd_in[95]
  PIN w0_wd_in[96]
    DIRECTION INPUT ;
    USE SIGNAL ;
    SHAPE ABUTMENT ;
    PORT
      LAYER metal3 ;
      RECT 322.665 0.000 322.735 0.070 ;
    END
  END w0_wd_in[96]
  PIN w0_wd_in[97]
    DIRECTION INPUT ;
    USE SIGNAL ;
    SHAPE ABUTMENT ;
    PORT
      LAYER metal3 ;
      RECT 322.805 0.000 322.875 0.070 ;
    END
  END w0_wd_in[97]
  PIN w0_wd_in[98]
    DIRECTION INPUT ;
    USE SIGNAL ;
    SHAPE ABUTMENT ;
    PORT
      LAYER metal3 ;
      RECT 322.945 0.000 323.015 0.070 ;
    END
  END w0_wd_in[98]
  PIN w0_wd_in[99]
    DIRECTION INPUT ;
    USE SIGNAL ;
    SHAPE ABUTMENT ;
    PORT
      LAYER metal3 ;
      RECT 323.085 0.000 323.155 0.070 ;
    END
  END w0_wd_in[99]
  PIN w0_wd_in[100]
    DIRECTION INPUT ;
    USE SIGNAL ;
    SHAPE ABUTMENT ;
    PORT
      LAYER metal3 ;
      RECT 323.225 0.000 323.295 0.070 ;
    END
  END w0_wd_in[100]
  PIN w0_wd_in[101]
    DIRECTION INPUT ;
    USE SIGNAL ;
    SHAPE ABUTMENT ;
    PORT
      LAYER metal3 ;
      RECT 323.365 0.000 323.435 0.070 ;
    END
  END w0_wd_in[101]
  PIN w0_wd_in[102]
    DIRECTION INPUT ;
    USE SIGNAL ;
    SHAPE ABUTMENT ;
    PORT
      LAYER metal3 ;
      RECT 323.505 0.000 323.575 0.070 ;
    END
  END w0_wd_in[102]
  PIN w0_wd_in[103]
    DIRECTION INPUT ;
    USE SIGNAL ;
    SHAPE ABUTMENT ;
    PORT
      LAYER metal3 ;
      RECT 323.645 0.000 323.715 0.070 ;
    END
  END w0_wd_in[103]
  PIN w0_wd_in[104]
    DIRECTION INPUT ;
    USE SIGNAL ;
    SHAPE ABUTMENT ;
    PORT
      LAYER metal3 ;
      RECT 323.785 0.000 323.855 0.070 ;
    END
  END w0_wd_in[104]
  PIN w0_wd_in[105]
    DIRECTION INPUT ;
    USE SIGNAL ;
    SHAPE ABUTMENT ;
    PORT
      LAYER metal3 ;
      RECT 323.925 0.000 323.995 0.070 ;
    END
  END w0_wd_in[105]
  PIN w0_wd_in[106]
    DIRECTION INPUT ;
    USE SIGNAL ;
    SHAPE ABUTMENT ;
    PORT
      LAYER metal3 ;
      RECT 324.065 0.000 324.135 0.070 ;
    END
  END w0_wd_in[106]
  PIN w0_wd_in[107]
    DIRECTION INPUT ;
    USE SIGNAL ;
    SHAPE ABUTMENT ;
    PORT
      LAYER metal3 ;
      RECT 324.205 0.000 324.275 0.070 ;
    END
  END w0_wd_in[107]
  PIN w0_wd_in[108]
    DIRECTION INPUT ;
    USE SIGNAL ;
    SHAPE ABUTMENT ;
    PORT
      LAYER metal3 ;
      RECT 324.345 0.000 324.415 0.070 ;
    END
  END w0_wd_in[108]
  PIN w0_wd_in[109]
    DIRECTION INPUT ;
    USE SIGNAL ;
    SHAPE ABUTMENT ;
    PORT
      LAYER metal3 ;
      RECT 324.485 0.000 324.555 0.070 ;
    END
  END w0_wd_in[109]
  PIN w0_wd_in[110]
    DIRECTION INPUT ;
    USE SIGNAL ;
    SHAPE ABUTMENT ;
    PORT
      LAYER metal3 ;
      RECT 324.625 0.000 324.695 0.070 ;
    END
  END w0_wd_in[110]
  PIN w0_wd_in[111]
    DIRECTION INPUT ;
    USE SIGNAL ;
    SHAPE ABUTMENT ;
    PORT
      LAYER metal3 ;
      RECT 324.765 0.000 324.835 0.070 ;
    END
  END w0_wd_in[111]
  PIN w0_wd_in[112]
    DIRECTION INPUT ;
    USE SIGNAL ;
    SHAPE ABUTMENT ;
    PORT
      LAYER metal3 ;
      RECT 324.905 0.000 324.975 0.070 ;
    END
  END w0_wd_in[112]
  PIN w0_wd_in[113]
    DIRECTION INPUT ;
    USE SIGNAL ;
    SHAPE ABUTMENT ;
    PORT
      LAYER metal3 ;
      RECT 325.045 0.000 325.115 0.070 ;
    END
  END w0_wd_in[113]
  PIN w0_wd_in[114]
    DIRECTION INPUT ;
    USE SIGNAL ;
    SHAPE ABUTMENT ;
    PORT
      LAYER metal3 ;
      RECT 325.185 0.000 325.255 0.070 ;
    END
  END w0_wd_in[114]
  PIN w0_wd_in[115]
    DIRECTION INPUT ;
    USE SIGNAL ;
    SHAPE ABUTMENT ;
    PORT
      LAYER metal3 ;
      RECT 325.325 0.000 325.395 0.070 ;
    END
  END w0_wd_in[115]
  PIN w0_wd_in[116]
    DIRECTION INPUT ;
    USE SIGNAL ;
    SHAPE ABUTMENT ;
    PORT
      LAYER metal3 ;
      RECT 325.465 0.000 325.535 0.070 ;
    END
  END w0_wd_in[116]
  PIN w0_wd_in[117]
    DIRECTION INPUT ;
    USE SIGNAL ;
    SHAPE ABUTMENT ;
    PORT
      LAYER metal3 ;
      RECT 325.605 0.000 325.675 0.070 ;
    END
  END w0_wd_in[117]
  PIN w0_wd_in[118]
    DIRECTION INPUT ;
    USE SIGNAL ;
    SHAPE ABUTMENT ;
    PORT
      LAYER metal3 ;
      RECT 325.745 0.000 325.815 0.070 ;
    END
  END w0_wd_in[118]
  PIN w0_wd_in[119]
    DIRECTION INPUT ;
    USE SIGNAL ;
    SHAPE ABUTMENT ;
    PORT
      LAYER metal3 ;
      RECT 325.885 0.000 325.955 0.070 ;
    END
  END w0_wd_in[119]
  PIN w0_wd_in[120]
    DIRECTION INPUT ;
    USE SIGNAL ;
    SHAPE ABUTMENT ;
    PORT
      LAYER metal3 ;
      RECT 326.025 0.000 326.095 0.070 ;
    END
  END w0_wd_in[120]
  PIN w0_wd_in[121]
    DIRECTION INPUT ;
    USE SIGNAL ;
    SHAPE ABUTMENT ;
    PORT
      LAYER metal3 ;
      RECT 326.165 0.000 326.235 0.070 ;
    END
  END w0_wd_in[121]
  PIN w0_wd_in[122]
    DIRECTION INPUT ;
    USE SIGNAL ;
    SHAPE ABUTMENT ;
    PORT
      LAYER metal3 ;
      RECT 326.305 0.000 326.375 0.070 ;
    END
  END w0_wd_in[122]
  PIN w0_wd_in[123]
    DIRECTION INPUT ;
    USE SIGNAL ;
    SHAPE ABUTMENT ;
    PORT
      LAYER metal3 ;
      RECT 326.445 0.000 326.515 0.070 ;
    END
  END w0_wd_in[123]
  PIN w0_wd_in[124]
    DIRECTION INPUT ;
    USE SIGNAL ;
    SHAPE ABUTMENT ;
    PORT
      LAYER metal3 ;
      RECT 326.585 0.000 326.655 0.070 ;
    END
  END w0_wd_in[124]
  PIN w0_wd_in[125]
    DIRECTION INPUT ;
    USE SIGNAL ;
    SHAPE ABUTMENT ;
    PORT
      LAYER metal3 ;
      RECT 326.725 0.000 326.795 0.070 ;
    END
  END w0_wd_in[125]
  PIN w0_wd_in[126]
    DIRECTION INPUT ;
    USE SIGNAL ;
    SHAPE ABUTMENT ;
    PORT
      LAYER metal3 ;
      RECT 326.865 0.000 326.935 0.070 ;
    END
  END w0_wd_in[126]
  PIN w0_wd_in[127]
    DIRECTION INPUT ;
    USE SIGNAL ;
    SHAPE ABUTMENT ;
    PORT
      LAYER metal3 ;
      RECT 327.005 0.000 327.075 0.070 ;
    END
  END w0_wd_in[127]
  PIN w0_wd_in[128]
    DIRECTION INPUT ;
    USE SIGNAL ;
    SHAPE ABUTMENT ;
    PORT
      LAYER metal3 ;
      RECT 327.145 0.000 327.215 0.070 ;
    END
  END w0_wd_in[128]
  PIN w0_wd_in[129]
    DIRECTION INPUT ;
    USE SIGNAL ;
    SHAPE ABUTMENT ;
    PORT
      LAYER metal3 ;
      RECT 327.285 0.000 327.355 0.070 ;
    END
  END w0_wd_in[129]
  PIN w0_wd_in[130]
    DIRECTION INPUT ;
    USE SIGNAL ;
    SHAPE ABUTMENT ;
    PORT
      LAYER metal3 ;
      RECT 327.425 0.000 327.495 0.070 ;
    END
  END w0_wd_in[130]
  PIN w0_wd_in[131]
    DIRECTION INPUT ;
    USE SIGNAL ;
    SHAPE ABUTMENT ;
    PORT
      LAYER metal3 ;
      RECT 327.565 0.000 327.635 0.070 ;
    END
  END w0_wd_in[131]
  PIN w0_wd_in[132]
    DIRECTION INPUT ;
    USE SIGNAL ;
    SHAPE ABUTMENT ;
    PORT
      LAYER metal3 ;
      RECT 327.705 0.000 327.775 0.070 ;
    END
  END w0_wd_in[132]
  PIN w0_wd_in[133]
    DIRECTION INPUT ;
    USE SIGNAL ;
    SHAPE ABUTMENT ;
    PORT
      LAYER metal3 ;
      RECT 327.845 0.000 327.915 0.070 ;
    END
  END w0_wd_in[133]
  PIN w0_wd_in[134]
    DIRECTION INPUT ;
    USE SIGNAL ;
    SHAPE ABUTMENT ;
    PORT
      LAYER metal3 ;
      RECT 327.985 0.000 328.055 0.070 ;
    END
  END w0_wd_in[134]
  PIN w0_wd_in[135]
    DIRECTION INPUT ;
    USE SIGNAL ;
    SHAPE ABUTMENT ;
    PORT
      LAYER metal3 ;
      RECT 328.125 0.000 328.195 0.070 ;
    END
  END w0_wd_in[135]
  PIN w0_wd_in[136]
    DIRECTION INPUT ;
    USE SIGNAL ;
    SHAPE ABUTMENT ;
    PORT
      LAYER metal3 ;
      RECT 328.265 0.000 328.335 0.070 ;
    END
  END w0_wd_in[136]
  PIN w0_wd_in[137]
    DIRECTION INPUT ;
    USE SIGNAL ;
    SHAPE ABUTMENT ;
    PORT
      LAYER metal3 ;
      RECT 328.405 0.000 328.475 0.070 ;
    END
  END w0_wd_in[137]
  PIN w0_wd_in[138]
    DIRECTION INPUT ;
    USE SIGNAL ;
    SHAPE ABUTMENT ;
    PORT
      LAYER metal3 ;
      RECT 328.545 0.000 328.615 0.070 ;
    END
  END w0_wd_in[138]
  PIN w0_wd_in[139]
    DIRECTION INPUT ;
    USE SIGNAL ;
    SHAPE ABUTMENT ;
    PORT
      LAYER metal3 ;
      RECT 328.685 0.000 328.755 0.070 ;
    END
  END w0_wd_in[139]
  PIN w0_wd_in[140]
    DIRECTION INPUT ;
    USE SIGNAL ;
    SHAPE ABUTMENT ;
    PORT
      LAYER metal3 ;
      RECT 328.825 0.000 328.895 0.070 ;
    END
  END w0_wd_in[140]
  PIN w0_wd_in[141]
    DIRECTION INPUT ;
    USE SIGNAL ;
    SHAPE ABUTMENT ;
    PORT
      LAYER metal3 ;
      RECT 328.965 0.000 329.035 0.070 ;
    END
  END w0_wd_in[141]
  PIN w0_wd_in[142]
    DIRECTION INPUT ;
    USE SIGNAL ;
    SHAPE ABUTMENT ;
    PORT
      LAYER metal3 ;
      RECT 329.105 0.000 329.175 0.070 ;
    END
  END w0_wd_in[142]
  PIN w0_wd_in[143]
    DIRECTION INPUT ;
    USE SIGNAL ;
    SHAPE ABUTMENT ;
    PORT
      LAYER metal3 ;
      RECT 329.245 0.000 329.315 0.070 ;
    END
  END w0_wd_in[143]
  PIN w0_wd_in[144]
    DIRECTION INPUT ;
    USE SIGNAL ;
    SHAPE ABUTMENT ;
    PORT
      LAYER metal3 ;
      RECT 329.385 0.000 329.455 0.070 ;
    END
  END w0_wd_in[144]
  PIN w0_wd_in[145]
    DIRECTION INPUT ;
    USE SIGNAL ;
    SHAPE ABUTMENT ;
    PORT
      LAYER metal3 ;
      RECT 329.525 0.000 329.595 0.070 ;
    END
  END w0_wd_in[145]
  PIN w0_wd_in[146]
    DIRECTION INPUT ;
    USE SIGNAL ;
    SHAPE ABUTMENT ;
    PORT
      LAYER metal3 ;
      RECT 329.665 0.000 329.735 0.070 ;
    END
  END w0_wd_in[146]
  PIN w0_wd_in[147]
    DIRECTION INPUT ;
    USE SIGNAL ;
    SHAPE ABUTMENT ;
    PORT
      LAYER metal3 ;
      RECT 329.805 0.000 329.875 0.070 ;
    END
  END w0_wd_in[147]
  PIN w0_wd_in[148]
    DIRECTION INPUT ;
    USE SIGNAL ;
    SHAPE ABUTMENT ;
    PORT
      LAYER metal3 ;
      RECT 329.945 0.000 330.015 0.070 ;
    END
  END w0_wd_in[148]
  PIN w0_wd_in[149]
    DIRECTION INPUT ;
    USE SIGNAL ;
    SHAPE ABUTMENT ;
    PORT
      LAYER metal3 ;
      RECT 330.085 0.000 330.155 0.070 ;
    END
  END w0_wd_in[149]
  PIN w0_wd_in[150]
    DIRECTION INPUT ;
    USE SIGNAL ;
    SHAPE ABUTMENT ;
    PORT
      LAYER metal3 ;
      RECT 330.225 0.000 330.295 0.070 ;
    END
  END w0_wd_in[150]
  PIN w0_wd_in[151]
    DIRECTION INPUT ;
    USE SIGNAL ;
    SHAPE ABUTMENT ;
    PORT
      LAYER metal3 ;
      RECT 330.365 0.000 330.435 0.070 ;
    END
  END w0_wd_in[151]
  PIN w0_wd_in[152]
    DIRECTION INPUT ;
    USE SIGNAL ;
    SHAPE ABUTMENT ;
    PORT
      LAYER metal3 ;
      RECT 330.505 0.000 330.575 0.070 ;
    END
  END w0_wd_in[152]
  PIN w0_wd_in[153]
    DIRECTION INPUT ;
    USE SIGNAL ;
    SHAPE ABUTMENT ;
    PORT
      LAYER metal3 ;
      RECT 330.645 0.000 330.715 0.070 ;
    END
  END w0_wd_in[153]
  PIN w0_wd_in[154]
    DIRECTION INPUT ;
    USE SIGNAL ;
    SHAPE ABUTMENT ;
    PORT
      LAYER metal3 ;
      RECT 330.785 0.000 330.855 0.070 ;
    END
  END w0_wd_in[154]
  PIN w0_wd_in[155]
    DIRECTION INPUT ;
    USE SIGNAL ;
    SHAPE ABUTMENT ;
    PORT
      LAYER metal3 ;
      RECT 330.925 0.000 330.995 0.070 ;
    END
  END w0_wd_in[155]
  PIN w0_wd_in[156]
    DIRECTION INPUT ;
    USE SIGNAL ;
    SHAPE ABUTMENT ;
    PORT
      LAYER metal3 ;
      RECT 331.065 0.000 331.135 0.070 ;
    END
  END w0_wd_in[156]
  PIN w0_wd_in[157]
    DIRECTION INPUT ;
    USE SIGNAL ;
    SHAPE ABUTMENT ;
    PORT
      LAYER metal3 ;
      RECT 331.205 0.000 331.275 0.070 ;
    END
  END w0_wd_in[157]
  PIN w0_wd_in[158]
    DIRECTION INPUT ;
    USE SIGNAL ;
    SHAPE ABUTMENT ;
    PORT
      LAYER metal3 ;
      RECT 331.345 0.000 331.415 0.070 ;
    END
  END w0_wd_in[158]
  PIN w0_wd_in[159]
    DIRECTION INPUT ;
    USE SIGNAL ;
    SHAPE ABUTMENT ;
    PORT
      LAYER metal3 ;
      RECT 331.485 0.000 331.555 0.070 ;
    END
  END w0_wd_in[159]
  PIN w0_wd_in[160]
    DIRECTION INPUT ;
    USE SIGNAL ;
    SHAPE ABUTMENT ;
    PORT
      LAYER metal3 ;
      RECT 331.625 0.000 331.695 0.070 ;
    END
  END w0_wd_in[160]
  PIN w0_wd_in[161]
    DIRECTION INPUT ;
    USE SIGNAL ;
    SHAPE ABUTMENT ;
    PORT
      LAYER metal3 ;
      RECT 331.765 0.000 331.835 0.070 ;
    END
  END w0_wd_in[161]
  PIN w0_wd_in[162]
    DIRECTION INPUT ;
    USE SIGNAL ;
    SHAPE ABUTMENT ;
    PORT
      LAYER metal3 ;
      RECT 331.905 0.000 331.975 0.070 ;
    END
  END w0_wd_in[162]
  PIN w0_wd_in[163]
    DIRECTION INPUT ;
    USE SIGNAL ;
    SHAPE ABUTMENT ;
    PORT
      LAYER metal3 ;
      RECT 332.045 0.000 332.115 0.070 ;
    END
  END w0_wd_in[163]
  PIN w0_wd_in[164]
    DIRECTION INPUT ;
    USE SIGNAL ;
    SHAPE ABUTMENT ;
    PORT
      LAYER metal3 ;
      RECT 332.185 0.000 332.255 0.070 ;
    END
  END w0_wd_in[164]
  PIN w0_wd_in[165]
    DIRECTION INPUT ;
    USE SIGNAL ;
    SHAPE ABUTMENT ;
    PORT
      LAYER metal3 ;
      RECT 332.325 0.000 332.395 0.070 ;
    END
  END w0_wd_in[165]
  PIN w0_wd_in[166]
    DIRECTION INPUT ;
    USE SIGNAL ;
    SHAPE ABUTMENT ;
    PORT
      LAYER metal3 ;
      RECT 332.465 0.000 332.535 0.070 ;
    END
  END w0_wd_in[166]
  PIN w0_wd_in[167]
    DIRECTION INPUT ;
    USE SIGNAL ;
    SHAPE ABUTMENT ;
    PORT
      LAYER metal3 ;
      RECT 332.605 0.000 332.675 0.070 ;
    END
  END w0_wd_in[167]
  PIN w0_wd_in[168]
    DIRECTION INPUT ;
    USE SIGNAL ;
    SHAPE ABUTMENT ;
    PORT
      LAYER metal3 ;
      RECT 332.745 0.000 332.815 0.070 ;
    END
  END w0_wd_in[168]
  PIN w0_wd_in[169]
    DIRECTION INPUT ;
    USE SIGNAL ;
    SHAPE ABUTMENT ;
    PORT
      LAYER metal3 ;
      RECT 332.885 0.000 332.955 0.070 ;
    END
  END w0_wd_in[169]
  PIN w0_wd_in[170]
    DIRECTION INPUT ;
    USE SIGNAL ;
    SHAPE ABUTMENT ;
    PORT
      LAYER metal3 ;
      RECT 333.025 0.000 333.095 0.070 ;
    END
  END w0_wd_in[170]
  PIN w0_wd_in[171]
    DIRECTION INPUT ;
    USE SIGNAL ;
    SHAPE ABUTMENT ;
    PORT
      LAYER metal3 ;
      RECT 333.165 0.000 333.235 0.070 ;
    END
  END w0_wd_in[171]
  PIN w0_wd_in[172]
    DIRECTION INPUT ;
    USE SIGNAL ;
    SHAPE ABUTMENT ;
    PORT
      LAYER metal3 ;
      RECT 333.305 0.000 333.375 0.070 ;
    END
  END w0_wd_in[172]
  PIN w0_wd_in[173]
    DIRECTION INPUT ;
    USE SIGNAL ;
    SHAPE ABUTMENT ;
    PORT
      LAYER metal3 ;
      RECT 333.445 0.000 333.515 0.070 ;
    END
  END w0_wd_in[173]
  PIN w0_wd_in[174]
    DIRECTION INPUT ;
    USE SIGNAL ;
    SHAPE ABUTMENT ;
    PORT
      LAYER metal3 ;
      RECT 333.585 0.000 333.655 0.070 ;
    END
  END w0_wd_in[174]
  PIN w0_wd_in[175]
    DIRECTION INPUT ;
    USE SIGNAL ;
    SHAPE ABUTMENT ;
    PORT
      LAYER metal3 ;
      RECT 333.725 0.000 333.795 0.070 ;
    END
  END w0_wd_in[175]
  PIN w0_wd_in[176]
    DIRECTION INPUT ;
    USE SIGNAL ;
    SHAPE ABUTMENT ;
    PORT
      LAYER metal3 ;
      RECT 333.865 0.000 333.935 0.070 ;
    END
  END w0_wd_in[176]
  PIN w0_wd_in[177]
    DIRECTION INPUT ;
    USE SIGNAL ;
    SHAPE ABUTMENT ;
    PORT
      LAYER metal3 ;
      RECT 334.005 0.000 334.075 0.070 ;
    END
  END w0_wd_in[177]
  PIN w0_wd_in[178]
    DIRECTION INPUT ;
    USE SIGNAL ;
    SHAPE ABUTMENT ;
    PORT
      LAYER metal3 ;
      RECT 334.145 0.000 334.215 0.070 ;
    END
  END w0_wd_in[178]
  PIN w0_wd_in[179]
    DIRECTION INPUT ;
    USE SIGNAL ;
    SHAPE ABUTMENT ;
    PORT
      LAYER metal3 ;
      RECT 334.285 0.000 334.355 0.070 ;
    END
  END w0_wd_in[179]
  PIN w0_wd_in[180]
    DIRECTION INPUT ;
    USE SIGNAL ;
    SHAPE ABUTMENT ;
    PORT
      LAYER metal3 ;
      RECT 334.425 0.000 334.495 0.070 ;
    END
  END w0_wd_in[180]
  PIN w0_wd_in[181]
    DIRECTION INPUT ;
    USE SIGNAL ;
    SHAPE ABUTMENT ;
    PORT
      LAYER metal3 ;
      RECT 334.565 0.000 334.635 0.070 ;
    END
  END w0_wd_in[181]
  PIN w0_wd_in[182]
    DIRECTION INPUT ;
    USE SIGNAL ;
    SHAPE ABUTMENT ;
    PORT
      LAYER metal3 ;
      RECT 334.705 0.000 334.775 0.070 ;
    END
  END w0_wd_in[182]
  PIN w0_wd_in[183]
    DIRECTION INPUT ;
    USE SIGNAL ;
    SHAPE ABUTMENT ;
    PORT
      LAYER metal3 ;
      RECT 334.845 0.000 334.915 0.070 ;
    END
  END w0_wd_in[183]
  PIN w0_wd_in[184]
    DIRECTION INPUT ;
    USE SIGNAL ;
    SHAPE ABUTMENT ;
    PORT
      LAYER metal3 ;
      RECT 334.985 0.000 335.055 0.070 ;
    END
  END w0_wd_in[184]
  PIN w0_wd_in[185]
    DIRECTION INPUT ;
    USE SIGNAL ;
    SHAPE ABUTMENT ;
    PORT
      LAYER metal3 ;
      RECT 335.125 0.000 335.195 0.070 ;
    END
  END w0_wd_in[185]
  PIN w0_wd_in[186]
    DIRECTION INPUT ;
    USE SIGNAL ;
    SHAPE ABUTMENT ;
    PORT
      LAYER metal3 ;
      RECT 335.265 0.000 335.335 0.070 ;
    END
  END w0_wd_in[186]
  PIN w0_wd_in[187]
    DIRECTION INPUT ;
    USE SIGNAL ;
    SHAPE ABUTMENT ;
    PORT
      LAYER metal3 ;
      RECT 335.405 0.000 335.475 0.070 ;
    END
  END w0_wd_in[187]
  PIN w0_wd_in[188]
    DIRECTION INPUT ;
    USE SIGNAL ;
    SHAPE ABUTMENT ;
    PORT
      LAYER metal3 ;
      RECT 335.545 0.000 335.615 0.070 ;
    END
  END w0_wd_in[188]
  PIN w0_wd_in[189]
    DIRECTION INPUT ;
    USE SIGNAL ;
    SHAPE ABUTMENT ;
    PORT
      LAYER metal3 ;
      RECT 335.685 0.000 335.755 0.070 ;
    END
  END w0_wd_in[189]
  PIN w0_wd_in[190]
    DIRECTION INPUT ;
    USE SIGNAL ;
    SHAPE ABUTMENT ;
    PORT
      LAYER metal3 ;
      RECT 335.825 0.000 335.895 0.070 ;
    END
  END w0_wd_in[190]
  PIN w0_wd_in[191]
    DIRECTION INPUT ;
    USE SIGNAL ;
    SHAPE ABUTMENT ;
    PORT
      LAYER metal3 ;
      RECT 335.965 0.000 336.035 0.070 ;
    END
  END w0_wd_in[191]
  PIN w0_wd_in[192]
    DIRECTION INPUT ;
    USE SIGNAL ;
    SHAPE ABUTMENT ;
    PORT
      LAYER metal3 ;
      RECT 336.105 0.000 336.175 0.070 ;
    END
  END w0_wd_in[192]
  PIN w0_wd_in[193]
    DIRECTION INPUT ;
    USE SIGNAL ;
    SHAPE ABUTMENT ;
    PORT
      LAYER metal3 ;
      RECT 336.245 0.000 336.315 0.070 ;
    END
  END w0_wd_in[193]
  PIN w0_wd_in[194]
    DIRECTION INPUT ;
    USE SIGNAL ;
    SHAPE ABUTMENT ;
    PORT
      LAYER metal3 ;
      RECT 336.385 0.000 336.455 0.070 ;
    END
  END w0_wd_in[194]
  PIN w0_wd_in[195]
    DIRECTION INPUT ;
    USE SIGNAL ;
    SHAPE ABUTMENT ;
    PORT
      LAYER metal3 ;
      RECT 336.525 0.000 336.595 0.070 ;
    END
  END w0_wd_in[195]
  PIN w0_wd_in[196]
    DIRECTION INPUT ;
    USE SIGNAL ;
    SHAPE ABUTMENT ;
    PORT
      LAYER metal3 ;
      RECT 336.665 0.000 336.735 0.070 ;
    END
  END w0_wd_in[196]
  PIN w0_wd_in[197]
    DIRECTION INPUT ;
    USE SIGNAL ;
    SHAPE ABUTMENT ;
    PORT
      LAYER metal3 ;
      RECT 336.805 0.000 336.875 0.070 ;
    END
  END w0_wd_in[197]
  PIN w0_wd_in[198]
    DIRECTION INPUT ;
    USE SIGNAL ;
    SHAPE ABUTMENT ;
    PORT
      LAYER metal3 ;
      RECT 336.945 0.000 337.015 0.070 ;
    END
  END w0_wd_in[198]
  PIN w0_wd_in[199]
    DIRECTION INPUT ;
    USE SIGNAL ;
    SHAPE ABUTMENT ;
    PORT
      LAYER metal3 ;
      RECT 337.085 0.000 337.155 0.070 ;
    END
  END w0_wd_in[199]
  PIN w0_wd_in[200]
    DIRECTION INPUT ;
    USE SIGNAL ;
    SHAPE ABUTMENT ;
    PORT
      LAYER metal3 ;
      RECT 337.225 0.000 337.295 0.070 ;
    END
  END w0_wd_in[200]
  PIN w0_wd_in[201]
    DIRECTION INPUT ;
    USE SIGNAL ;
    SHAPE ABUTMENT ;
    PORT
      LAYER metal3 ;
      RECT 337.365 0.000 337.435 0.070 ;
    END
  END w0_wd_in[201]
  PIN w0_wd_in[202]
    DIRECTION INPUT ;
    USE SIGNAL ;
    SHAPE ABUTMENT ;
    PORT
      LAYER metal3 ;
      RECT 337.505 0.000 337.575 0.070 ;
    END
  END w0_wd_in[202]
  PIN w0_wd_in[203]
    DIRECTION INPUT ;
    USE SIGNAL ;
    SHAPE ABUTMENT ;
    PORT
      LAYER metal3 ;
      RECT 337.645 0.000 337.715 0.070 ;
    END
  END w0_wd_in[203]
  PIN w0_wd_in[204]
    DIRECTION INPUT ;
    USE SIGNAL ;
    SHAPE ABUTMENT ;
    PORT
      LAYER metal3 ;
      RECT 337.785 0.000 337.855 0.070 ;
    END
  END w0_wd_in[204]
  PIN w0_wd_in[205]
    DIRECTION INPUT ;
    USE SIGNAL ;
    SHAPE ABUTMENT ;
    PORT
      LAYER metal3 ;
      RECT 337.925 0.000 337.995 0.070 ;
    END
  END w0_wd_in[205]
  PIN w0_wd_in[206]
    DIRECTION INPUT ;
    USE SIGNAL ;
    SHAPE ABUTMENT ;
    PORT
      LAYER metal3 ;
      RECT 338.065 0.000 338.135 0.070 ;
    END
  END w0_wd_in[206]
  PIN w0_wd_in[207]
    DIRECTION INPUT ;
    USE SIGNAL ;
    SHAPE ABUTMENT ;
    PORT
      LAYER metal3 ;
      RECT 338.205 0.000 338.275 0.070 ;
    END
  END w0_wd_in[207]
  PIN w0_wd_in[208]
    DIRECTION INPUT ;
    USE SIGNAL ;
    SHAPE ABUTMENT ;
    PORT
      LAYER metal3 ;
      RECT 338.345 0.000 338.415 0.070 ;
    END
  END w0_wd_in[208]
  PIN w0_wd_in[209]
    DIRECTION INPUT ;
    USE SIGNAL ;
    SHAPE ABUTMENT ;
    PORT
      LAYER metal3 ;
      RECT 338.485 0.000 338.555 0.070 ;
    END
  END w0_wd_in[209]
  PIN w0_wd_in[210]
    DIRECTION INPUT ;
    USE SIGNAL ;
    SHAPE ABUTMENT ;
    PORT
      LAYER metal3 ;
      RECT 338.625 0.000 338.695 0.070 ;
    END
  END w0_wd_in[210]
  PIN w0_wd_in[211]
    DIRECTION INPUT ;
    USE SIGNAL ;
    SHAPE ABUTMENT ;
    PORT
      LAYER metal3 ;
      RECT 338.765 0.000 338.835 0.070 ;
    END
  END w0_wd_in[211]
  PIN w0_wd_in[212]
    DIRECTION INPUT ;
    USE SIGNAL ;
    SHAPE ABUTMENT ;
    PORT
      LAYER metal3 ;
      RECT 338.905 0.000 338.975 0.070 ;
    END
  END w0_wd_in[212]
  PIN w0_wd_in[213]
    DIRECTION INPUT ;
    USE SIGNAL ;
    SHAPE ABUTMENT ;
    PORT
      LAYER metal3 ;
      RECT 339.045 0.000 339.115 0.070 ;
    END
  END w0_wd_in[213]
  PIN w0_wd_in[214]
    DIRECTION INPUT ;
    USE SIGNAL ;
    SHAPE ABUTMENT ;
    PORT
      LAYER metal3 ;
      RECT 339.185 0.000 339.255 0.070 ;
    END
  END w0_wd_in[214]
  PIN w0_wd_in[215]
    DIRECTION INPUT ;
    USE SIGNAL ;
    SHAPE ABUTMENT ;
    PORT
      LAYER metal3 ;
      RECT 339.325 0.000 339.395 0.070 ;
    END
  END w0_wd_in[215]
  PIN w0_wd_in[216]
    DIRECTION INPUT ;
    USE SIGNAL ;
    SHAPE ABUTMENT ;
    PORT
      LAYER metal3 ;
      RECT 339.465 0.000 339.535 0.070 ;
    END
  END w0_wd_in[216]
  PIN w0_wd_in[217]
    DIRECTION INPUT ;
    USE SIGNAL ;
    SHAPE ABUTMENT ;
    PORT
      LAYER metal3 ;
      RECT 339.605 0.000 339.675 0.070 ;
    END
  END w0_wd_in[217]
  PIN w0_wd_in[218]
    DIRECTION INPUT ;
    USE SIGNAL ;
    SHAPE ABUTMENT ;
    PORT
      LAYER metal3 ;
      RECT 339.745 0.000 339.815 0.070 ;
    END
  END w0_wd_in[218]
  PIN w0_wd_in[219]
    DIRECTION INPUT ;
    USE SIGNAL ;
    SHAPE ABUTMENT ;
    PORT
      LAYER metal3 ;
      RECT 339.885 0.000 339.955 0.070 ;
    END
  END w0_wd_in[219]
  PIN w0_wd_in[220]
    DIRECTION INPUT ;
    USE SIGNAL ;
    SHAPE ABUTMENT ;
    PORT
      LAYER metal3 ;
      RECT 340.025 0.000 340.095 0.070 ;
    END
  END w0_wd_in[220]
  PIN w0_wd_in[221]
    DIRECTION INPUT ;
    USE SIGNAL ;
    SHAPE ABUTMENT ;
    PORT
      LAYER metal3 ;
      RECT 340.165 0.000 340.235 0.070 ;
    END
  END w0_wd_in[221]
  PIN w0_wd_in[222]
    DIRECTION INPUT ;
    USE SIGNAL ;
    SHAPE ABUTMENT ;
    PORT
      LAYER metal3 ;
      RECT 340.305 0.000 340.375 0.070 ;
    END
  END w0_wd_in[222]
  PIN w0_wd_in[223]
    DIRECTION INPUT ;
    USE SIGNAL ;
    SHAPE ABUTMENT ;
    PORT
      LAYER metal3 ;
      RECT 340.445 0.000 340.515 0.070 ;
    END
  END w0_wd_in[223]
  PIN w0_wd_in[224]
    DIRECTION INPUT ;
    USE SIGNAL ;
    SHAPE ABUTMENT ;
    PORT
      LAYER metal3 ;
      RECT 340.585 0.000 340.655 0.070 ;
    END
  END w0_wd_in[224]
  PIN w0_wd_in[225]
    DIRECTION INPUT ;
    USE SIGNAL ;
    SHAPE ABUTMENT ;
    PORT
      LAYER metal3 ;
      RECT 340.725 0.000 340.795 0.070 ;
    END
  END w0_wd_in[225]
  PIN w0_wd_in[226]
    DIRECTION INPUT ;
    USE SIGNAL ;
    SHAPE ABUTMENT ;
    PORT
      LAYER metal3 ;
      RECT 340.865 0.000 340.935 0.070 ;
    END
  END w0_wd_in[226]
  PIN w0_wd_in[227]
    DIRECTION INPUT ;
    USE SIGNAL ;
    SHAPE ABUTMENT ;
    PORT
      LAYER metal3 ;
      RECT 341.005 0.000 341.075 0.070 ;
    END
  END w0_wd_in[227]
  PIN w0_wd_in[228]
    DIRECTION INPUT ;
    USE SIGNAL ;
    SHAPE ABUTMENT ;
    PORT
      LAYER metal3 ;
      RECT 341.145 0.000 341.215 0.070 ;
    END
  END w0_wd_in[228]
  PIN w0_wd_in[229]
    DIRECTION INPUT ;
    USE SIGNAL ;
    SHAPE ABUTMENT ;
    PORT
      LAYER metal3 ;
      RECT 341.285 0.000 341.355 0.070 ;
    END
  END w0_wd_in[229]
  PIN w0_wd_in[230]
    DIRECTION INPUT ;
    USE SIGNAL ;
    SHAPE ABUTMENT ;
    PORT
      LAYER metal3 ;
      RECT 341.425 0.000 341.495 0.070 ;
    END
  END w0_wd_in[230]
  PIN w0_wd_in[231]
    DIRECTION INPUT ;
    USE SIGNAL ;
    SHAPE ABUTMENT ;
    PORT
      LAYER metal3 ;
      RECT 341.565 0.000 341.635 0.070 ;
    END
  END w0_wd_in[231]
  PIN w0_wd_in[232]
    DIRECTION INPUT ;
    USE SIGNAL ;
    SHAPE ABUTMENT ;
    PORT
      LAYER metal3 ;
      RECT 341.705 0.000 341.775 0.070 ;
    END
  END w0_wd_in[232]
  PIN w0_wd_in[233]
    DIRECTION INPUT ;
    USE SIGNAL ;
    SHAPE ABUTMENT ;
    PORT
      LAYER metal3 ;
      RECT 341.845 0.000 341.915 0.070 ;
    END
  END w0_wd_in[233]
  PIN w0_wd_in[234]
    DIRECTION INPUT ;
    USE SIGNAL ;
    SHAPE ABUTMENT ;
    PORT
      LAYER metal3 ;
      RECT 341.985 0.000 342.055 0.070 ;
    END
  END w0_wd_in[234]
  PIN w0_wd_in[235]
    DIRECTION INPUT ;
    USE SIGNAL ;
    SHAPE ABUTMENT ;
    PORT
      LAYER metal3 ;
      RECT 342.125 0.000 342.195 0.070 ;
    END
  END w0_wd_in[235]
  PIN w0_wd_in[236]
    DIRECTION INPUT ;
    USE SIGNAL ;
    SHAPE ABUTMENT ;
    PORT
      LAYER metal3 ;
      RECT 342.265 0.000 342.335 0.070 ;
    END
  END w0_wd_in[236]
  PIN w0_wd_in[237]
    DIRECTION INPUT ;
    USE SIGNAL ;
    SHAPE ABUTMENT ;
    PORT
      LAYER metal3 ;
      RECT 342.405 0.000 342.475 0.070 ;
    END
  END w0_wd_in[237]
  PIN w0_wd_in[238]
    DIRECTION INPUT ;
    USE SIGNAL ;
    SHAPE ABUTMENT ;
    PORT
      LAYER metal3 ;
      RECT 342.545 0.000 342.615 0.070 ;
    END
  END w0_wd_in[238]
  PIN w0_wd_in[239]
    DIRECTION INPUT ;
    USE SIGNAL ;
    SHAPE ABUTMENT ;
    PORT
      LAYER metal3 ;
      RECT 342.685 0.000 342.755 0.070 ;
    END
  END w0_wd_in[239]
  PIN w0_wd_in[240]
    DIRECTION INPUT ;
    USE SIGNAL ;
    SHAPE ABUTMENT ;
    PORT
      LAYER metal3 ;
      RECT 342.825 0.000 342.895 0.070 ;
    END
  END w0_wd_in[240]
  PIN w0_wd_in[241]
    DIRECTION INPUT ;
    USE SIGNAL ;
    SHAPE ABUTMENT ;
    PORT
      LAYER metal3 ;
      RECT 342.965 0.000 343.035 0.070 ;
    END
  END w0_wd_in[241]
  PIN w0_wd_in[242]
    DIRECTION INPUT ;
    USE SIGNAL ;
    SHAPE ABUTMENT ;
    PORT
      LAYER metal3 ;
      RECT 343.105 0.000 343.175 0.070 ;
    END
  END w0_wd_in[242]
  PIN w0_wd_in[243]
    DIRECTION INPUT ;
    USE SIGNAL ;
    SHAPE ABUTMENT ;
    PORT
      LAYER metal3 ;
      RECT 343.245 0.000 343.315 0.070 ;
    END
  END w0_wd_in[243]
  PIN w0_wd_in[244]
    DIRECTION INPUT ;
    USE SIGNAL ;
    SHAPE ABUTMENT ;
    PORT
      LAYER metal3 ;
      RECT 343.385 0.000 343.455 0.070 ;
    END
  END w0_wd_in[244]
  PIN w0_wd_in[245]
    DIRECTION INPUT ;
    USE SIGNAL ;
    SHAPE ABUTMENT ;
    PORT
      LAYER metal3 ;
      RECT 343.525 0.000 343.595 0.070 ;
    END
  END w0_wd_in[245]
  PIN w0_wd_in[246]
    DIRECTION INPUT ;
    USE SIGNAL ;
    SHAPE ABUTMENT ;
    PORT
      LAYER metal3 ;
      RECT 343.665 0.000 343.735 0.070 ;
    END
  END w0_wd_in[246]
  PIN w0_wd_in[247]
    DIRECTION INPUT ;
    USE SIGNAL ;
    SHAPE ABUTMENT ;
    PORT
      LAYER metal3 ;
      RECT 343.805 0.000 343.875 0.070 ;
    END
  END w0_wd_in[247]
  PIN w0_wd_in[248]
    DIRECTION INPUT ;
    USE SIGNAL ;
    SHAPE ABUTMENT ;
    PORT
      LAYER metal3 ;
      RECT 343.945 0.000 344.015 0.070 ;
    END
  END w0_wd_in[248]
  PIN w0_wd_in[249]
    DIRECTION INPUT ;
    USE SIGNAL ;
    SHAPE ABUTMENT ;
    PORT
      LAYER metal3 ;
      RECT 344.085 0.000 344.155 0.070 ;
    END
  END w0_wd_in[249]
  PIN w0_wd_in[250]
    DIRECTION INPUT ;
    USE SIGNAL ;
    SHAPE ABUTMENT ;
    PORT
      LAYER metal3 ;
      RECT 344.225 0.000 344.295 0.070 ;
    END
  END w0_wd_in[250]
  PIN w0_wd_in[251]
    DIRECTION INPUT ;
    USE SIGNAL ;
    SHAPE ABUTMENT ;
    PORT
      LAYER metal3 ;
      RECT 344.365 0.000 344.435 0.070 ;
    END
  END w0_wd_in[251]
  PIN w0_wd_in[252]
    DIRECTION INPUT ;
    USE SIGNAL ;
    SHAPE ABUTMENT ;
    PORT
      LAYER metal3 ;
      RECT 344.505 0.000 344.575 0.070 ;
    END
  END w0_wd_in[252]
  PIN w0_wd_in[253]
    DIRECTION INPUT ;
    USE SIGNAL ;
    SHAPE ABUTMENT ;
    PORT
      LAYER metal3 ;
      RECT 344.645 0.000 344.715 0.070 ;
    END
  END w0_wd_in[253]
  PIN w0_wd_in[254]
    DIRECTION INPUT ;
    USE SIGNAL ;
    SHAPE ABUTMENT ;
    PORT
      LAYER metal3 ;
      RECT 344.785 0.000 344.855 0.070 ;
    END
  END w0_wd_in[254]
  PIN w0_wd_in[255]
    DIRECTION INPUT ;
    USE SIGNAL ;
    SHAPE ABUTMENT ;
    PORT
      LAYER metal3 ;
      RECT 344.925 0.000 344.995 0.070 ;
    END
  END w0_wd_in[255]
  PIN w0_wd_in[256]
    DIRECTION INPUT ;
    USE SIGNAL ;
    SHAPE ABUTMENT ;
    PORT
      LAYER metal3 ;
      RECT 345.065 0.000 345.135 0.070 ;
    END
  END w0_wd_in[256]
  PIN w0_wd_in[257]
    DIRECTION INPUT ;
    USE SIGNAL ;
    SHAPE ABUTMENT ;
    PORT
      LAYER metal3 ;
      RECT 345.205 0.000 345.275 0.070 ;
    END
  END w0_wd_in[257]
  PIN w0_wd_in[258]
    DIRECTION INPUT ;
    USE SIGNAL ;
    SHAPE ABUTMENT ;
    PORT
      LAYER metal3 ;
      RECT 345.345 0.000 345.415 0.070 ;
    END
  END w0_wd_in[258]
  PIN w0_wd_in[259]
    DIRECTION INPUT ;
    USE SIGNAL ;
    SHAPE ABUTMENT ;
    PORT
      LAYER metal3 ;
      RECT 345.485 0.000 345.555 0.070 ;
    END
  END w0_wd_in[259]
  PIN w0_wd_in[260]
    DIRECTION INPUT ;
    USE SIGNAL ;
    SHAPE ABUTMENT ;
    PORT
      LAYER metal3 ;
      RECT 345.625 0.000 345.695 0.070 ;
    END
  END w0_wd_in[260]
  PIN w0_wd_in[261]
    DIRECTION INPUT ;
    USE SIGNAL ;
    SHAPE ABUTMENT ;
    PORT
      LAYER metal3 ;
      RECT 345.765 0.000 345.835 0.070 ;
    END
  END w0_wd_in[261]
  PIN w0_wd_in[262]
    DIRECTION INPUT ;
    USE SIGNAL ;
    SHAPE ABUTMENT ;
    PORT
      LAYER metal3 ;
      RECT 345.905 0.000 345.975 0.070 ;
    END
  END w0_wd_in[262]
  PIN w0_wd_in[263]
    DIRECTION INPUT ;
    USE SIGNAL ;
    SHAPE ABUTMENT ;
    PORT
      LAYER metal3 ;
      RECT 346.045 0.000 346.115 0.070 ;
    END
  END w0_wd_in[263]
  PIN w0_wd_in[264]
    DIRECTION INPUT ;
    USE SIGNAL ;
    SHAPE ABUTMENT ;
    PORT
      LAYER metal3 ;
      RECT 346.185 0.000 346.255 0.070 ;
    END
  END w0_wd_in[264]
  PIN w0_wd_in[265]
    DIRECTION INPUT ;
    USE SIGNAL ;
    SHAPE ABUTMENT ;
    PORT
      LAYER metal3 ;
      RECT 346.325 0.000 346.395 0.070 ;
    END
  END w0_wd_in[265]
  PIN w0_wd_in[266]
    DIRECTION INPUT ;
    USE SIGNAL ;
    SHAPE ABUTMENT ;
    PORT
      LAYER metal3 ;
      RECT 346.465 0.000 346.535 0.070 ;
    END
  END w0_wd_in[266]
  PIN w0_wd_in[267]
    DIRECTION INPUT ;
    USE SIGNAL ;
    SHAPE ABUTMENT ;
    PORT
      LAYER metal3 ;
      RECT 346.605 0.000 346.675 0.070 ;
    END
  END w0_wd_in[267]
  PIN w0_wd_in[268]
    DIRECTION INPUT ;
    USE SIGNAL ;
    SHAPE ABUTMENT ;
    PORT
      LAYER metal3 ;
      RECT 346.745 0.000 346.815 0.070 ;
    END
  END w0_wd_in[268]
  PIN w0_wd_in[269]
    DIRECTION INPUT ;
    USE SIGNAL ;
    SHAPE ABUTMENT ;
    PORT
      LAYER metal3 ;
      RECT 346.885 0.000 346.955 0.070 ;
    END
  END w0_wd_in[269]
  PIN w0_wd_in[270]
    DIRECTION INPUT ;
    USE SIGNAL ;
    SHAPE ABUTMENT ;
    PORT
      LAYER metal3 ;
      RECT 347.025 0.000 347.095 0.070 ;
    END
  END w0_wd_in[270]
  PIN w0_wd_in[271]
    DIRECTION INPUT ;
    USE SIGNAL ;
    SHAPE ABUTMENT ;
    PORT
      LAYER metal3 ;
      RECT 347.165 0.000 347.235 0.070 ;
    END
  END w0_wd_in[271]
  PIN w0_wd_in[272]
    DIRECTION INPUT ;
    USE SIGNAL ;
    SHAPE ABUTMENT ;
    PORT
      LAYER metal3 ;
      RECT 347.305 0.000 347.375 0.070 ;
    END
  END w0_wd_in[272]
  PIN w0_wd_in[273]
    DIRECTION INPUT ;
    USE SIGNAL ;
    SHAPE ABUTMENT ;
    PORT
      LAYER metal3 ;
      RECT 347.445 0.000 347.515 0.070 ;
    END
  END w0_wd_in[273]
  PIN w0_wd_in[274]
    DIRECTION INPUT ;
    USE SIGNAL ;
    SHAPE ABUTMENT ;
    PORT
      LAYER metal3 ;
      RECT 347.585 0.000 347.655 0.070 ;
    END
  END w0_wd_in[274]
  PIN w0_wd_in[275]
    DIRECTION INPUT ;
    USE SIGNAL ;
    SHAPE ABUTMENT ;
    PORT
      LAYER metal3 ;
      RECT 347.725 0.000 347.795 0.070 ;
    END
  END w0_wd_in[275]
  PIN w0_wd_in[276]
    DIRECTION INPUT ;
    USE SIGNAL ;
    SHAPE ABUTMENT ;
    PORT
      LAYER metal3 ;
      RECT 347.865 0.000 347.935 0.070 ;
    END
  END w0_wd_in[276]
  PIN w0_wd_in[277]
    DIRECTION INPUT ;
    USE SIGNAL ;
    SHAPE ABUTMENT ;
    PORT
      LAYER metal3 ;
      RECT 348.005 0.000 348.075 0.070 ;
    END
  END w0_wd_in[277]
  PIN w0_wd_in[278]
    DIRECTION INPUT ;
    USE SIGNAL ;
    SHAPE ABUTMENT ;
    PORT
      LAYER metal3 ;
      RECT 348.145 0.000 348.215 0.070 ;
    END
  END w0_wd_in[278]
  PIN w0_wd_in[279]
    DIRECTION INPUT ;
    USE SIGNAL ;
    SHAPE ABUTMENT ;
    PORT
      LAYER metal3 ;
      RECT 348.285 0.000 348.355 0.070 ;
    END
  END w0_wd_in[279]
  PIN w0_wd_in[280]
    DIRECTION INPUT ;
    USE SIGNAL ;
    SHAPE ABUTMENT ;
    PORT
      LAYER metal3 ;
      RECT 348.425 0.000 348.495 0.070 ;
    END
  END w0_wd_in[280]
  PIN w0_wd_in[281]
    DIRECTION INPUT ;
    USE SIGNAL ;
    SHAPE ABUTMENT ;
    PORT
      LAYER metal3 ;
      RECT 348.565 0.000 348.635 0.070 ;
    END
  END w0_wd_in[281]
  PIN w0_wd_in[282]
    DIRECTION INPUT ;
    USE SIGNAL ;
    SHAPE ABUTMENT ;
    PORT
      LAYER metal3 ;
      RECT 348.705 0.000 348.775 0.070 ;
    END
  END w0_wd_in[282]
  PIN w0_wd_in[283]
    DIRECTION INPUT ;
    USE SIGNAL ;
    SHAPE ABUTMENT ;
    PORT
      LAYER metal3 ;
      RECT 348.845 0.000 348.915 0.070 ;
    END
  END w0_wd_in[283]
  PIN w0_wd_in[284]
    DIRECTION INPUT ;
    USE SIGNAL ;
    SHAPE ABUTMENT ;
    PORT
      LAYER metal3 ;
      RECT 348.985 0.000 349.055 0.070 ;
    END
  END w0_wd_in[284]
  PIN w0_wd_in[285]
    DIRECTION INPUT ;
    USE SIGNAL ;
    SHAPE ABUTMENT ;
    PORT
      LAYER metal3 ;
      RECT 349.125 0.000 349.195 0.070 ;
    END
  END w0_wd_in[285]
  PIN w0_wd_in[286]
    DIRECTION INPUT ;
    USE SIGNAL ;
    SHAPE ABUTMENT ;
    PORT
      LAYER metal3 ;
      RECT 349.265 0.000 349.335 0.070 ;
    END
  END w0_wd_in[286]
  PIN w0_wd_in[287]
    DIRECTION INPUT ;
    USE SIGNAL ;
    SHAPE ABUTMENT ;
    PORT
      LAYER metal3 ;
      RECT 349.405 0.000 349.475 0.070 ;
    END
  END w0_wd_in[287]
  PIN w0_wd_in[288]
    DIRECTION INPUT ;
    USE SIGNAL ;
    SHAPE ABUTMENT ;
    PORT
      LAYER metal3 ;
      RECT 349.545 0.000 349.615 0.070 ;
    END
  END w0_wd_in[288]
  PIN w0_wd_in[289]
    DIRECTION INPUT ;
    USE SIGNAL ;
    SHAPE ABUTMENT ;
    PORT
      LAYER metal3 ;
      RECT 349.685 0.000 349.755 0.070 ;
    END
  END w0_wd_in[289]
  PIN w0_wd_in[290]
    DIRECTION INPUT ;
    USE SIGNAL ;
    SHAPE ABUTMENT ;
    PORT
      LAYER metal3 ;
      RECT 349.825 0.000 349.895 0.070 ;
    END
  END w0_wd_in[290]
  PIN w0_wd_in[291]
    DIRECTION INPUT ;
    USE SIGNAL ;
    SHAPE ABUTMENT ;
    PORT
      LAYER metal3 ;
      RECT 349.965 0.000 350.035 0.070 ;
    END
  END w0_wd_in[291]
  PIN w0_wd_in[292]
    DIRECTION INPUT ;
    USE SIGNAL ;
    SHAPE ABUTMENT ;
    PORT
      LAYER metal3 ;
      RECT 350.105 0.000 350.175 0.070 ;
    END
  END w0_wd_in[292]
  PIN w0_wd_in[293]
    DIRECTION INPUT ;
    USE SIGNAL ;
    SHAPE ABUTMENT ;
    PORT
      LAYER metal3 ;
      RECT 350.245 0.000 350.315 0.070 ;
    END
  END w0_wd_in[293]
  PIN w0_wd_in[294]
    DIRECTION INPUT ;
    USE SIGNAL ;
    SHAPE ABUTMENT ;
    PORT
      LAYER metal3 ;
      RECT 350.385 0.000 350.455 0.070 ;
    END
  END w0_wd_in[294]
  PIN w0_wd_in[295]
    DIRECTION INPUT ;
    USE SIGNAL ;
    SHAPE ABUTMENT ;
    PORT
      LAYER metal3 ;
      RECT 350.525 0.000 350.595 0.070 ;
    END
  END w0_wd_in[295]
  PIN w0_wd_in[296]
    DIRECTION INPUT ;
    USE SIGNAL ;
    SHAPE ABUTMENT ;
    PORT
      LAYER metal3 ;
      RECT 350.665 0.000 350.735 0.070 ;
    END
  END w0_wd_in[296]
  PIN w0_wd_in[297]
    DIRECTION INPUT ;
    USE SIGNAL ;
    SHAPE ABUTMENT ;
    PORT
      LAYER metal3 ;
      RECT 350.805 0.000 350.875 0.070 ;
    END
  END w0_wd_in[297]
  PIN w0_wd_in[298]
    DIRECTION INPUT ;
    USE SIGNAL ;
    SHAPE ABUTMENT ;
    PORT
      LAYER metal3 ;
      RECT 350.945 0.000 351.015 0.070 ;
    END
  END w0_wd_in[298]
  PIN w0_wd_in[299]
    DIRECTION INPUT ;
    USE SIGNAL ;
    SHAPE ABUTMENT ;
    PORT
      LAYER metal3 ;
      RECT 351.085 0.000 351.155 0.070 ;
    END
  END w0_wd_in[299]
  PIN w0_wd_in[300]
    DIRECTION INPUT ;
    USE SIGNAL ;
    SHAPE ABUTMENT ;
    PORT
      LAYER metal3 ;
      RECT 351.225 0.000 351.295 0.070 ;
    END
  END w0_wd_in[300]
  PIN w0_wd_in[301]
    DIRECTION INPUT ;
    USE SIGNAL ;
    SHAPE ABUTMENT ;
    PORT
      LAYER metal3 ;
      RECT 351.365 0.000 351.435 0.070 ;
    END
  END w0_wd_in[301]
  PIN w0_wd_in[302]
    DIRECTION INPUT ;
    USE SIGNAL ;
    SHAPE ABUTMENT ;
    PORT
      LAYER metal3 ;
      RECT 351.505 0.000 351.575 0.070 ;
    END
  END w0_wd_in[302]
  PIN w0_wd_in[303]
    DIRECTION INPUT ;
    USE SIGNAL ;
    SHAPE ABUTMENT ;
    PORT
      LAYER metal3 ;
      RECT 351.645 0.000 351.715 0.070 ;
    END
  END w0_wd_in[303]
  PIN w0_wd_in[304]
    DIRECTION INPUT ;
    USE SIGNAL ;
    SHAPE ABUTMENT ;
    PORT
      LAYER metal3 ;
      RECT 351.785 0.000 351.855 0.070 ;
    END
  END w0_wd_in[304]
  PIN w0_wd_in[305]
    DIRECTION INPUT ;
    USE SIGNAL ;
    SHAPE ABUTMENT ;
    PORT
      LAYER metal3 ;
      RECT 351.925 0.000 351.995 0.070 ;
    END
  END w0_wd_in[305]
  PIN w0_wd_in[306]
    DIRECTION INPUT ;
    USE SIGNAL ;
    SHAPE ABUTMENT ;
    PORT
      LAYER metal3 ;
      RECT 352.065 0.000 352.135 0.070 ;
    END
  END w0_wd_in[306]
  PIN w0_wd_in[307]
    DIRECTION INPUT ;
    USE SIGNAL ;
    SHAPE ABUTMENT ;
    PORT
      LAYER metal3 ;
      RECT 352.205 0.000 352.275 0.070 ;
    END
  END w0_wd_in[307]
  PIN w0_wd_in[308]
    DIRECTION INPUT ;
    USE SIGNAL ;
    SHAPE ABUTMENT ;
    PORT
      LAYER metal3 ;
      RECT 352.345 0.000 352.415 0.070 ;
    END
  END w0_wd_in[308]
  PIN w0_wd_in[309]
    DIRECTION INPUT ;
    USE SIGNAL ;
    SHAPE ABUTMENT ;
    PORT
      LAYER metal3 ;
      RECT 352.485 0.000 352.555 0.070 ;
    END
  END w0_wd_in[309]
  PIN w0_wd_in[310]
    DIRECTION INPUT ;
    USE SIGNAL ;
    SHAPE ABUTMENT ;
    PORT
      LAYER metal3 ;
      RECT 352.625 0.000 352.695 0.070 ;
    END
  END w0_wd_in[310]
  PIN w0_wd_in[311]
    DIRECTION INPUT ;
    USE SIGNAL ;
    SHAPE ABUTMENT ;
    PORT
      LAYER metal3 ;
      RECT 352.765 0.000 352.835 0.070 ;
    END
  END w0_wd_in[311]
  PIN w0_wd_in[312]
    DIRECTION INPUT ;
    USE SIGNAL ;
    SHAPE ABUTMENT ;
    PORT
      LAYER metal3 ;
      RECT 352.905 0.000 352.975 0.070 ;
    END
  END w0_wd_in[312]
  PIN w0_wd_in[313]
    DIRECTION INPUT ;
    USE SIGNAL ;
    SHAPE ABUTMENT ;
    PORT
      LAYER metal3 ;
      RECT 353.045 0.000 353.115 0.070 ;
    END
  END w0_wd_in[313]
  PIN w0_wd_in[314]
    DIRECTION INPUT ;
    USE SIGNAL ;
    SHAPE ABUTMENT ;
    PORT
      LAYER metal3 ;
      RECT 353.185 0.000 353.255 0.070 ;
    END
  END w0_wd_in[314]
  PIN w0_wd_in[315]
    DIRECTION INPUT ;
    USE SIGNAL ;
    SHAPE ABUTMENT ;
    PORT
      LAYER metal3 ;
      RECT 353.325 0.000 353.395 0.070 ;
    END
  END w0_wd_in[315]
  PIN w0_wd_in[316]
    DIRECTION INPUT ;
    USE SIGNAL ;
    SHAPE ABUTMENT ;
    PORT
      LAYER metal3 ;
      RECT 353.465 0.000 353.535 0.070 ;
    END
  END w0_wd_in[316]
  PIN w0_wd_in[317]
    DIRECTION INPUT ;
    USE SIGNAL ;
    SHAPE ABUTMENT ;
    PORT
      LAYER metal3 ;
      RECT 353.605 0.000 353.675 0.070 ;
    END
  END w0_wd_in[317]
  PIN w0_wd_in[318]
    DIRECTION INPUT ;
    USE SIGNAL ;
    SHAPE ABUTMENT ;
    PORT
      LAYER metal3 ;
      RECT 353.745 0.000 353.815 0.070 ;
    END
  END w0_wd_in[318]
  PIN w0_wd_in[319]
    DIRECTION INPUT ;
    USE SIGNAL ;
    SHAPE ABUTMENT ;
    PORT
      LAYER metal3 ;
      RECT 353.885 0.000 353.955 0.070 ;
    END
  END w0_wd_in[319]
  PIN w0_wd_in[320]
    DIRECTION INPUT ;
    USE SIGNAL ;
    SHAPE ABUTMENT ;
    PORT
      LAYER metal3 ;
      RECT 354.025 0.000 354.095 0.070 ;
    END
  END w0_wd_in[320]
  PIN w0_wd_in[321]
    DIRECTION INPUT ;
    USE SIGNAL ;
    SHAPE ABUTMENT ;
    PORT
      LAYER metal3 ;
      RECT 354.165 0.000 354.235 0.070 ;
    END
  END w0_wd_in[321]
  PIN w0_wd_in[322]
    DIRECTION INPUT ;
    USE SIGNAL ;
    SHAPE ABUTMENT ;
    PORT
      LAYER metal3 ;
      RECT 354.305 0.000 354.375 0.070 ;
    END
  END w0_wd_in[322]
  PIN w0_wd_in[323]
    DIRECTION INPUT ;
    USE SIGNAL ;
    SHAPE ABUTMENT ;
    PORT
      LAYER metal3 ;
      RECT 354.445 0.000 354.515 0.070 ;
    END
  END w0_wd_in[323]
  PIN w0_wd_in[324]
    DIRECTION INPUT ;
    USE SIGNAL ;
    SHAPE ABUTMENT ;
    PORT
      LAYER metal3 ;
      RECT 354.585 0.000 354.655 0.070 ;
    END
  END w0_wd_in[324]
  PIN w0_wd_in[325]
    DIRECTION INPUT ;
    USE SIGNAL ;
    SHAPE ABUTMENT ;
    PORT
      LAYER metal3 ;
      RECT 354.725 0.000 354.795 0.070 ;
    END
  END w0_wd_in[325]
  PIN w0_wd_in[326]
    DIRECTION INPUT ;
    USE SIGNAL ;
    SHAPE ABUTMENT ;
    PORT
      LAYER metal3 ;
      RECT 354.865 0.000 354.935 0.070 ;
    END
  END w0_wd_in[326]
  PIN w0_wd_in[327]
    DIRECTION INPUT ;
    USE SIGNAL ;
    SHAPE ABUTMENT ;
    PORT
      LAYER metal3 ;
      RECT 355.005 0.000 355.075 0.070 ;
    END
  END w0_wd_in[327]
  PIN w0_wd_in[328]
    DIRECTION INPUT ;
    USE SIGNAL ;
    SHAPE ABUTMENT ;
    PORT
      LAYER metal3 ;
      RECT 355.145 0.000 355.215 0.070 ;
    END
  END w0_wd_in[328]
  PIN w0_wd_in[329]
    DIRECTION INPUT ;
    USE SIGNAL ;
    SHAPE ABUTMENT ;
    PORT
      LAYER metal3 ;
      RECT 355.285 0.000 355.355 0.070 ;
    END
  END w0_wd_in[329]
  PIN w0_wd_in[330]
    DIRECTION INPUT ;
    USE SIGNAL ;
    SHAPE ABUTMENT ;
    PORT
      LAYER metal3 ;
      RECT 355.425 0.000 355.495 0.070 ;
    END
  END w0_wd_in[330]
  PIN w0_wd_in[331]
    DIRECTION INPUT ;
    USE SIGNAL ;
    SHAPE ABUTMENT ;
    PORT
      LAYER metal3 ;
      RECT 355.565 0.000 355.635 0.070 ;
    END
  END w0_wd_in[331]
  PIN w0_wd_in[332]
    DIRECTION INPUT ;
    USE SIGNAL ;
    SHAPE ABUTMENT ;
    PORT
      LAYER metal3 ;
      RECT 355.705 0.000 355.775 0.070 ;
    END
  END w0_wd_in[332]
  PIN w0_wd_in[333]
    DIRECTION INPUT ;
    USE SIGNAL ;
    SHAPE ABUTMENT ;
    PORT
      LAYER metal3 ;
      RECT 355.845 0.000 355.915 0.070 ;
    END
  END w0_wd_in[333]
  PIN w0_wd_in[334]
    DIRECTION INPUT ;
    USE SIGNAL ;
    SHAPE ABUTMENT ;
    PORT
      LAYER metal3 ;
      RECT 355.985 0.000 356.055 0.070 ;
    END
  END w0_wd_in[334]
  PIN w0_wd_in[335]
    DIRECTION INPUT ;
    USE SIGNAL ;
    SHAPE ABUTMENT ;
    PORT
      LAYER metal3 ;
      RECT 356.125 0.000 356.195 0.070 ;
    END
  END w0_wd_in[335]
  PIN w0_wd_in[336]
    DIRECTION INPUT ;
    USE SIGNAL ;
    SHAPE ABUTMENT ;
    PORT
      LAYER metal3 ;
      RECT 356.265 0.000 356.335 0.070 ;
    END
  END w0_wd_in[336]
  PIN w0_wd_in[337]
    DIRECTION INPUT ;
    USE SIGNAL ;
    SHAPE ABUTMENT ;
    PORT
      LAYER metal3 ;
      RECT 356.405 0.000 356.475 0.070 ;
    END
  END w0_wd_in[337]
  PIN w0_wd_in[338]
    DIRECTION INPUT ;
    USE SIGNAL ;
    SHAPE ABUTMENT ;
    PORT
      LAYER metal3 ;
      RECT 356.545 0.000 356.615 0.070 ;
    END
  END w0_wd_in[338]
  PIN w0_wd_in[339]
    DIRECTION INPUT ;
    USE SIGNAL ;
    SHAPE ABUTMENT ;
    PORT
      LAYER metal3 ;
      RECT 356.685 0.000 356.755 0.070 ;
    END
  END w0_wd_in[339]
  PIN w0_wd_in[340]
    DIRECTION INPUT ;
    USE SIGNAL ;
    SHAPE ABUTMENT ;
    PORT
      LAYER metal3 ;
      RECT 356.825 0.000 356.895 0.070 ;
    END
  END w0_wd_in[340]
  PIN w0_wd_in[341]
    DIRECTION INPUT ;
    USE SIGNAL ;
    SHAPE ABUTMENT ;
    PORT
      LAYER metal3 ;
      RECT 356.965 0.000 357.035 0.070 ;
    END
  END w0_wd_in[341]
  PIN w0_wd_in[342]
    DIRECTION INPUT ;
    USE SIGNAL ;
    SHAPE ABUTMENT ;
    PORT
      LAYER metal3 ;
      RECT 357.105 0.000 357.175 0.070 ;
    END
  END w0_wd_in[342]
  PIN w0_wd_in[343]
    DIRECTION INPUT ;
    USE SIGNAL ;
    SHAPE ABUTMENT ;
    PORT
      LAYER metal3 ;
      RECT 357.245 0.000 357.315 0.070 ;
    END
  END w0_wd_in[343]
  PIN w0_wd_in[344]
    DIRECTION INPUT ;
    USE SIGNAL ;
    SHAPE ABUTMENT ;
    PORT
      LAYER metal3 ;
      RECT 357.385 0.000 357.455 0.070 ;
    END
  END w0_wd_in[344]
  PIN w0_wd_in[345]
    DIRECTION INPUT ;
    USE SIGNAL ;
    SHAPE ABUTMENT ;
    PORT
      LAYER metal3 ;
      RECT 357.525 0.000 357.595 0.070 ;
    END
  END w0_wd_in[345]
  PIN w0_wd_in[346]
    DIRECTION INPUT ;
    USE SIGNAL ;
    SHAPE ABUTMENT ;
    PORT
      LAYER metal3 ;
      RECT 357.665 0.000 357.735 0.070 ;
    END
  END w0_wd_in[346]
  PIN w0_wd_in[347]
    DIRECTION INPUT ;
    USE SIGNAL ;
    SHAPE ABUTMENT ;
    PORT
      LAYER metal3 ;
      RECT 357.805 0.000 357.875 0.070 ;
    END
  END w0_wd_in[347]
  PIN w0_wd_in[348]
    DIRECTION INPUT ;
    USE SIGNAL ;
    SHAPE ABUTMENT ;
    PORT
      LAYER metal3 ;
      RECT 357.945 0.000 358.015 0.070 ;
    END
  END w0_wd_in[348]
  PIN w0_wd_in[349]
    DIRECTION INPUT ;
    USE SIGNAL ;
    SHAPE ABUTMENT ;
    PORT
      LAYER metal3 ;
      RECT 358.085 0.000 358.155 0.070 ;
    END
  END w0_wd_in[349]
  PIN w0_wd_in[350]
    DIRECTION INPUT ;
    USE SIGNAL ;
    SHAPE ABUTMENT ;
    PORT
      LAYER metal3 ;
      RECT 358.225 0.000 358.295 0.070 ;
    END
  END w0_wd_in[350]
  PIN w0_wd_in[351]
    DIRECTION INPUT ;
    USE SIGNAL ;
    SHAPE ABUTMENT ;
    PORT
      LAYER metal3 ;
      RECT 358.365 0.000 358.435 0.070 ;
    END
  END w0_wd_in[351]
  PIN w0_wd_in[352]
    DIRECTION INPUT ;
    USE SIGNAL ;
    SHAPE ABUTMENT ;
    PORT
      LAYER metal3 ;
      RECT 358.505 0.000 358.575 0.070 ;
    END
  END w0_wd_in[352]
  PIN w0_wd_in[353]
    DIRECTION INPUT ;
    USE SIGNAL ;
    SHAPE ABUTMENT ;
    PORT
      LAYER metal3 ;
      RECT 358.645 0.000 358.715 0.070 ;
    END
  END w0_wd_in[353]
  PIN w0_wd_in[354]
    DIRECTION INPUT ;
    USE SIGNAL ;
    SHAPE ABUTMENT ;
    PORT
      LAYER metal3 ;
      RECT 358.785 0.000 358.855 0.070 ;
    END
  END w0_wd_in[354]
  PIN w0_wd_in[355]
    DIRECTION INPUT ;
    USE SIGNAL ;
    SHAPE ABUTMENT ;
    PORT
      LAYER metal3 ;
      RECT 358.925 0.000 358.995 0.070 ;
    END
  END w0_wd_in[355]
  PIN w0_wd_in[356]
    DIRECTION INPUT ;
    USE SIGNAL ;
    SHAPE ABUTMENT ;
    PORT
      LAYER metal3 ;
      RECT 359.065 0.000 359.135 0.070 ;
    END
  END w0_wd_in[356]
  PIN w0_wd_in[357]
    DIRECTION INPUT ;
    USE SIGNAL ;
    SHAPE ABUTMENT ;
    PORT
      LAYER metal3 ;
      RECT 359.205 0.000 359.275 0.070 ;
    END
  END w0_wd_in[357]
  PIN w0_wd_in[358]
    DIRECTION INPUT ;
    USE SIGNAL ;
    SHAPE ABUTMENT ;
    PORT
      LAYER metal3 ;
      RECT 359.345 0.000 359.415 0.070 ;
    END
  END w0_wd_in[358]
  PIN w0_wd_in[359]
    DIRECTION INPUT ;
    USE SIGNAL ;
    SHAPE ABUTMENT ;
    PORT
      LAYER metal3 ;
      RECT 359.485 0.000 359.555 0.070 ;
    END
  END w0_wd_in[359]
  PIN w0_wd_in[360]
    DIRECTION INPUT ;
    USE SIGNAL ;
    SHAPE ABUTMENT ;
    PORT
      LAYER metal3 ;
      RECT 359.625 0.000 359.695 0.070 ;
    END
  END w0_wd_in[360]
  PIN w0_wd_in[361]
    DIRECTION INPUT ;
    USE SIGNAL ;
    SHAPE ABUTMENT ;
    PORT
      LAYER metal3 ;
      RECT 359.765 0.000 359.835 0.070 ;
    END
  END w0_wd_in[361]
  PIN w0_wd_in[362]
    DIRECTION INPUT ;
    USE SIGNAL ;
    SHAPE ABUTMENT ;
    PORT
      LAYER metal3 ;
      RECT 359.905 0.000 359.975 0.070 ;
    END
  END w0_wd_in[362]
  PIN w0_wd_in[363]
    DIRECTION INPUT ;
    USE SIGNAL ;
    SHAPE ABUTMENT ;
    PORT
      LAYER metal3 ;
      RECT 360.045 0.000 360.115 0.070 ;
    END
  END w0_wd_in[363]
  PIN w0_wd_in[364]
    DIRECTION INPUT ;
    USE SIGNAL ;
    SHAPE ABUTMENT ;
    PORT
      LAYER metal3 ;
      RECT 360.185 0.000 360.255 0.070 ;
    END
  END w0_wd_in[364]
  PIN w0_wd_in[365]
    DIRECTION INPUT ;
    USE SIGNAL ;
    SHAPE ABUTMENT ;
    PORT
      LAYER metal3 ;
      RECT 360.325 0.000 360.395 0.070 ;
    END
  END w0_wd_in[365]
  PIN w0_wd_in[366]
    DIRECTION INPUT ;
    USE SIGNAL ;
    SHAPE ABUTMENT ;
    PORT
      LAYER metal3 ;
      RECT 360.465 0.000 360.535 0.070 ;
    END
  END w0_wd_in[366]
  PIN w0_wd_in[367]
    DIRECTION INPUT ;
    USE SIGNAL ;
    SHAPE ABUTMENT ;
    PORT
      LAYER metal3 ;
      RECT 360.605 0.000 360.675 0.070 ;
    END
  END w0_wd_in[367]
  PIN w0_wd_in[368]
    DIRECTION INPUT ;
    USE SIGNAL ;
    SHAPE ABUTMENT ;
    PORT
      LAYER metal3 ;
      RECT 360.745 0.000 360.815 0.070 ;
    END
  END w0_wd_in[368]
  PIN w0_wd_in[369]
    DIRECTION INPUT ;
    USE SIGNAL ;
    SHAPE ABUTMENT ;
    PORT
      LAYER metal3 ;
      RECT 360.885 0.000 360.955 0.070 ;
    END
  END w0_wd_in[369]
  PIN w0_wd_in[370]
    DIRECTION INPUT ;
    USE SIGNAL ;
    SHAPE ABUTMENT ;
    PORT
      LAYER metal3 ;
      RECT 361.025 0.000 361.095 0.070 ;
    END
  END w0_wd_in[370]
  PIN w0_wd_in[371]
    DIRECTION INPUT ;
    USE SIGNAL ;
    SHAPE ABUTMENT ;
    PORT
      LAYER metal3 ;
      RECT 361.165 0.000 361.235 0.070 ;
    END
  END w0_wd_in[371]
  PIN w0_wd_in[372]
    DIRECTION INPUT ;
    USE SIGNAL ;
    SHAPE ABUTMENT ;
    PORT
      LAYER metal3 ;
      RECT 361.305 0.000 361.375 0.070 ;
    END
  END w0_wd_in[372]
  PIN w0_wd_in[373]
    DIRECTION INPUT ;
    USE SIGNAL ;
    SHAPE ABUTMENT ;
    PORT
      LAYER metal3 ;
      RECT 361.445 0.000 361.515 0.070 ;
    END
  END w0_wd_in[373]
  PIN w0_wd_in[374]
    DIRECTION INPUT ;
    USE SIGNAL ;
    SHAPE ABUTMENT ;
    PORT
      LAYER metal3 ;
      RECT 361.585 0.000 361.655 0.070 ;
    END
  END w0_wd_in[374]
  PIN w0_wd_in[375]
    DIRECTION INPUT ;
    USE SIGNAL ;
    SHAPE ABUTMENT ;
    PORT
      LAYER metal3 ;
      RECT 361.725 0.000 361.795 0.070 ;
    END
  END w0_wd_in[375]
  PIN w0_wd_in[376]
    DIRECTION INPUT ;
    USE SIGNAL ;
    SHAPE ABUTMENT ;
    PORT
      LAYER metal3 ;
      RECT 361.865 0.000 361.935 0.070 ;
    END
  END w0_wd_in[376]
  PIN w0_wd_in[377]
    DIRECTION INPUT ;
    USE SIGNAL ;
    SHAPE ABUTMENT ;
    PORT
      LAYER metal3 ;
      RECT 362.005 0.000 362.075 0.070 ;
    END
  END w0_wd_in[377]
  PIN w0_wd_in[378]
    DIRECTION INPUT ;
    USE SIGNAL ;
    SHAPE ABUTMENT ;
    PORT
      LAYER metal3 ;
      RECT 362.145 0.000 362.215 0.070 ;
    END
  END w0_wd_in[378]
  PIN w0_wd_in[379]
    DIRECTION INPUT ;
    USE SIGNAL ;
    SHAPE ABUTMENT ;
    PORT
      LAYER metal3 ;
      RECT 362.285 0.000 362.355 0.070 ;
    END
  END w0_wd_in[379]
  PIN w0_wd_in[380]
    DIRECTION INPUT ;
    USE SIGNAL ;
    SHAPE ABUTMENT ;
    PORT
      LAYER metal3 ;
      RECT 362.425 0.000 362.495 0.070 ;
    END
  END w0_wd_in[380]
  PIN w0_wd_in[381]
    DIRECTION INPUT ;
    USE SIGNAL ;
    SHAPE ABUTMENT ;
    PORT
      LAYER metal3 ;
      RECT 362.565 0.000 362.635 0.070 ;
    END
  END w0_wd_in[381]
  PIN w0_wd_in[382]
    DIRECTION INPUT ;
    USE SIGNAL ;
    SHAPE ABUTMENT ;
    PORT
      LAYER metal3 ;
      RECT 362.705 0.000 362.775 0.070 ;
    END
  END w0_wd_in[382]
  PIN w0_wd_in[383]
    DIRECTION INPUT ;
    USE SIGNAL ;
    SHAPE ABUTMENT ;
    PORT
      LAYER metal3 ;
      RECT 362.845 0.000 362.915 0.070 ;
    END
  END w0_wd_in[383]
  PIN w0_wd_in[384]
    DIRECTION INPUT ;
    USE SIGNAL ;
    SHAPE ABUTMENT ;
    PORT
      LAYER metal3 ;
      RECT 362.985 0.000 363.055 0.070 ;
    END
  END w0_wd_in[384]
  PIN w0_wd_in[385]
    DIRECTION INPUT ;
    USE SIGNAL ;
    SHAPE ABUTMENT ;
    PORT
      LAYER metal3 ;
      RECT 363.125 0.000 363.195 0.070 ;
    END
  END w0_wd_in[385]
  PIN w0_wd_in[386]
    DIRECTION INPUT ;
    USE SIGNAL ;
    SHAPE ABUTMENT ;
    PORT
      LAYER metal3 ;
      RECT 363.265 0.000 363.335 0.070 ;
    END
  END w0_wd_in[386]
  PIN w0_wd_in[387]
    DIRECTION INPUT ;
    USE SIGNAL ;
    SHAPE ABUTMENT ;
    PORT
      LAYER metal3 ;
      RECT 363.405 0.000 363.475 0.070 ;
    END
  END w0_wd_in[387]
  PIN w0_wd_in[388]
    DIRECTION INPUT ;
    USE SIGNAL ;
    SHAPE ABUTMENT ;
    PORT
      LAYER metal3 ;
      RECT 363.545 0.000 363.615 0.070 ;
    END
  END w0_wd_in[388]
  PIN w0_wd_in[389]
    DIRECTION INPUT ;
    USE SIGNAL ;
    SHAPE ABUTMENT ;
    PORT
      LAYER metal3 ;
      RECT 363.685 0.000 363.755 0.070 ;
    END
  END w0_wd_in[389]
  PIN w0_wd_in[390]
    DIRECTION INPUT ;
    USE SIGNAL ;
    SHAPE ABUTMENT ;
    PORT
      LAYER metal3 ;
      RECT 363.825 0.000 363.895 0.070 ;
    END
  END w0_wd_in[390]
  PIN w0_wd_in[391]
    DIRECTION INPUT ;
    USE SIGNAL ;
    SHAPE ABUTMENT ;
    PORT
      LAYER metal3 ;
      RECT 363.965 0.000 364.035 0.070 ;
    END
  END w0_wd_in[391]
  PIN w0_wd_in[392]
    DIRECTION INPUT ;
    USE SIGNAL ;
    SHAPE ABUTMENT ;
    PORT
      LAYER metal3 ;
      RECT 364.105 0.000 364.175 0.070 ;
    END
  END w0_wd_in[392]
  PIN w0_wd_in[393]
    DIRECTION INPUT ;
    USE SIGNAL ;
    SHAPE ABUTMENT ;
    PORT
      LAYER metal3 ;
      RECT 364.245 0.000 364.315 0.070 ;
    END
  END w0_wd_in[393]
  PIN w0_wd_in[394]
    DIRECTION INPUT ;
    USE SIGNAL ;
    SHAPE ABUTMENT ;
    PORT
      LAYER metal3 ;
      RECT 364.385 0.000 364.455 0.070 ;
    END
  END w0_wd_in[394]
  PIN w0_wd_in[395]
    DIRECTION INPUT ;
    USE SIGNAL ;
    SHAPE ABUTMENT ;
    PORT
      LAYER metal3 ;
      RECT 364.525 0.000 364.595 0.070 ;
    END
  END w0_wd_in[395]
  PIN w0_wd_in[396]
    DIRECTION INPUT ;
    USE SIGNAL ;
    SHAPE ABUTMENT ;
    PORT
      LAYER metal3 ;
      RECT 364.665 0.000 364.735 0.070 ;
    END
  END w0_wd_in[396]
  PIN w0_wd_in[397]
    DIRECTION INPUT ;
    USE SIGNAL ;
    SHAPE ABUTMENT ;
    PORT
      LAYER metal3 ;
      RECT 364.805 0.000 364.875 0.070 ;
    END
  END w0_wd_in[397]
  PIN w0_wd_in[398]
    DIRECTION INPUT ;
    USE SIGNAL ;
    SHAPE ABUTMENT ;
    PORT
      LAYER metal3 ;
      RECT 364.945 0.000 365.015 0.070 ;
    END
  END w0_wd_in[398]
  PIN w0_wd_in[399]
    DIRECTION INPUT ;
    USE SIGNAL ;
    SHAPE ABUTMENT ;
    PORT
      LAYER metal3 ;
      RECT 365.085 0.000 365.155 0.070 ;
    END
  END w0_wd_in[399]
  PIN w0_wd_in[400]
    DIRECTION INPUT ;
    USE SIGNAL ;
    SHAPE ABUTMENT ;
    PORT
      LAYER metal3 ;
      RECT 365.225 0.000 365.295 0.070 ;
    END
  END w0_wd_in[400]
  PIN w0_wd_in[401]
    DIRECTION INPUT ;
    USE SIGNAL ;
    SHAPE ABUTMENT ;
    PORT
      LAYER metal3 ;
      RECT 365.365 0.000 365.435 0.070 ;
    END
  END w0_wd_in[401]
  PIN w0_wd_in[402]
    DIRECTION INPUT ;
    USE SIGNAL ;
    SHAPE ABUTMENT ;
    PORT
      LAYER metal3 ;
      RECT 365.505 0.000 365.575 0.070 ;
    END
  END w0_wd_in[402]
  PIN w0_wd_in[403]
    DIRECTION INPUT ;
    USE SIGNAL ;
    SHAPE ABUTMENT ;
    PORT
      LAYER metal3 ;
      RECT 365.645 0.000 365.715 0.070 ;
    END
  END w0_wd_in[403]
  PIN w0_wd_in[404]
    DIRECTION INPUT ;
    USE SIGNAL ;
    SHAPE ABUTMENT ;
    PORT
      LAYER metal3 ;
      RECT 365.785 0.000 365.855 0.070 ;
    END
  END w0_wd_in[404]
  PIN w0_wd_in[405]
    DIRECTION INPUT ;
    USE SIGNAL ;
    SHAPE ABUTMENT ;
    PORT
      LAYER metal3 ;
      RECT 365.925 0.000 365.995 0.070 ;
    END
  END w0_wd_in[405]
  PIN w0_wd_in[406]
    DIRECTION INPUT ;
    USE SIGNAL ;
    SHAPE ABUTMENT ;
    PORT
      LAYER metal3 ;
      RECT 366.065 0.000 366.135 0.070 ;
    END
  END w0_wd_in[406]
  PIN w0_wd_in[407]
    DIRECTION INPUT ;
    USE SIGNAL ;
    SHAPE ABUTMENT ;
    PORT
      LAYER metal3 ;
      RECT 366.205 0.000 366.275 0.070 ;
    END
  END w0_wd_in[407]
  PIN w0_wd_in[408]
    DIRECTION INPUT ;
    USE SIGNAL ;
    SHAPE ABUTMENT ;
    PORT
      LAYER metal3 ;
      RECT 366.345 0.000 366.415 0.070 ;
    END
  END w0_wd_in[408]
  PIN w0_wd_in[409]
    DIRECTION INPUT ;
    USE SIGNAL ;
    SHAPE ABUTMENT ;
    PORT
      LAYER metal3 ;
      RECT 366.485 0.000 366.555 0.070 ;
    END
  END w0_wd_in[409]
  PIN w0_wd_in[410]
    DIRECTION INPUT ;
    USE SIGNAL ;
    SHAPE ABUTMENT ;
    PORT
      LAYER metal3 ;
      RECT 366.625 0.000 366.695 0.070 ;
    END
  END w0_wd_in[410]
  PIN w0_wd_in[411]
    DIRECTION INPUT ;
    USE SIGNAL ;
    SHAPE ABUTMENT ;
    PORT
      LAYER metal3 ;
      RECT 366.765 0.000 366.835 0.070 ;
    END
  END w0_wd_in[411]
  PIN w0_wd_in[412]
    DIRECTION INPUT ;
    USE SIGNAL ;
    SHAPE ABUTMENT ;
    PORT
      LAYER metal3 ;
      RECT 366.905 0.000 366.975 0.070 ;
    END
  END w0_wd_in[412]
  PIN w0_wd_in[413]
    DIRECTION INPUT ;
    USE SIGNAL ;
    SHAPE ABUTMENT ;
    PORT
      LAYER metal3 ;
      RECT 367.045 0.000 367.115 0.070 ;
    END
  END w0_wd_in[413]
  PIN w0_wd_in[414]
    DIRECTION INPUT ;
    USE SIGNAL ;
    SHAPE ABUTMENT ;
    PORT
      LAYER metal3 ;
      RECT 367.185 0.000 367.255 0.070 ;
    END
  END w0_wd_in[414]
  PIN w0_wd_in[415]
    DIRECTION INPUT ;
    USE SIGNAL ;
    SHAPE ABUTMENT ;
    PORT
      LAYER metal3 ;
      RECT 367.325 0.000 367.395 0.070 ;
    END
  END w0_wd_in[415]
  PIN w0_wd_in[416]
    DIRECTION INPUT ;
    USE SIGNAL ;
    SHAPE ABUTMENT ;
    PORT
      LAYER metal3 ;
      RECT 367.465 0.000 367.535 0.070 ;
    END
  END w0_wd_in[416]
  PIN w0_wd_in[417]
    DIRECTION INPUT ;
    USE SIGNAL ;
    SHAPE ABUTMENT ;
    PORT
      LAYER metal3 ;
      RECT 367.605 0.000 367.675 0.070 ;
    END
  END w0_wd_in[417]
  PIN w0_wd_in[418]
    DIRECTION INPUT ;
    USE SIGNAL ;
    SHAPE ABUTMENT ;
    PORT
      LAYER metal3 ;
      RECT 367.745 0.000 367.815 0.070 ;
    END
  END w0_wd_in[418]
  PIN w0_wd_in[419]
    DIRECTION INPUT ;
    USE SIGNAL ;
    SHAPE ABUTMENT ;
    PORT
      LAYER metal3 ;
      RECT 367.885 0.000 367.955 0.070 ;
    END
  END w0_wd_in[419]
  PIN w0_wd_in[420]
    DIRECTION INPUT ;
    USE SIGNAL ;
    SHAPE ABUTMENT ;
    PORT
      LAYER metal3 ;
      RECT 368.025 0.000 368.095 0.070 ;
    END
  END w0_wd_in[420]
  PIN w0_wd_in[421]
    DIRECTION INPUT ;
    USE SIGNAL ;
    SHAPE ABUTMENT ;
    PORT
      LAYER metal3 ;
      RECT 368.165 0.000 368.235 0.070 ;
    END
  END w0_wd_in[421]
  PIN w0_wd_in[422]
    DIRECTION INPUT ;
    USE SIGNAL ;
    SHAPE ABUTMENT ;
    PORT
      LAYER metal3 ;
      RECT 368.305 0.000 368.375 0.070 ;
    END
  END w0_wd_in[422]
  PIN w0_wd_in[423]
    DIRECTION INPUT ;
    USE SIGNAL ;
    SHAPE ABUTMENT ;
    PORT
      LAYER metal3 ;
      RECT 368.445 0.000 368.515 0.070 ;
    END
  END w0_wd_in[423]
  PIN w0_wd_in[424]
    DIRECTION INPUT ;
    USE SIGNAL ;
    SHAPE ABUTMENT ;
    PORT
      LAYER metal3 ;
      RECT 368.585 0.000 368.655 0.070 ;
    END
  END w0_wd_in[424]
  PIN w0_wd_in[425]
    DIRECTION INPUT ;
    USE SIGNAL ;
    SHAPE ABUTMENT ;
    PORT
      LAYER metal3 ;
      RECT 368.725 0.000 368.795 0.070 ;
    END
  END w0_wd_in[425]
  PIN w0_wd_in[426]
    DIRECTION INPUT ;
    USE SIGNAL ;
    SHAPE ABUTMENT ;
    PORT
      LAYER metal3 ;
      RECT 368.865 0.000 368.935 0.070 ;
    END
  END w0_wd_in[426]
  PIN w0_wd_in[427]
    DIRECTION INPUT ;
    USE SIGNAL ;
    SHAPE ABUTMENT ;
    PORT
      LAYER metal3 ;
      RECT 369.005 0.000 369.075 0.070 ;
    END
  END w0_wd_in[427]
  PIN w0_wd_in[428]
    DIRECTION INPUT ;
    USE SIGNAL ;
    SHAPE ABUTMENT ;
    PORT
      LAYER metal3 ;
      RECT 369.145 0.000 369.215 0.070 ;
    END
  END w0_wd_in[428]
  PIN w0_wd_in[429]
    DIRECTION INPUT ;
    USE SIGNAL ;
    SHAPE ABUTMENT ;
    PORT
      LAYER metal3 ;
      RECT 369.285 0.000 369.355 0.070 ;
    END
  END w0_wd_in[429]
  PIN w0_wd_in[430]
    DIRECTION INPUT ;
    USE SIGNAL ;
    SHAPE ABUTMENT ;
    PORT
      LAYER metal3 ;
      RECT 369.425 0.000 369.495 0.070 ;
    END
  END w0_wd_in[430]
  PIN w0_wd_in[431]
    DIRECTION INPUT ;
    USE SIGNAL ;
    SHAPE ABUTMENT ;
    PORT
      LAYER metal3 ;
      RECT 369.565 0.000 369.635 0.070 ;
    END
  END w0_wd_in[431]
  PIN w0_wd_in[432]
    DIRECTION INPUT ;
    USE SIGNAL ;
    SHAPE ABUTMENT ;
    PORT
      LAYER metal3 ;
      RECT 369.705 0.000 369.775 0.070 ;
    END
  END w0_wd_in[432]
  PIN w0_wd_in[433]
    DIRECTION INPUT ;
    USE SIGNAL ;
    SHAPE ABUTMENT ;
    PORT
      LAYER metal3 ;
      RECT 369.845 0.000 369.915 0.070 ;
    END
  END w0_wd_in[433]
  PIN w0_wd_in[434]
    DIRECTION INPUT ;
    USE SIGNAL ;
    SHAPE ABUTMENT ;
    PORT
      LAYER metal3 ;
      RECT 369.985 0.000 370.055 0.070 ;
    END
  END w0_wd_in[434]
  PIN w0_wd_in[435]
    DIRECTION INPUT ;
    USE SIGNAL ;
    SHAPE ABUTMENT ;
    PORT
      LAYER metal3 ;
      RECT 370.125 0.000 370.195 0.070 ;
    END
  END w0_wd_in[435]
  PIN w0_wd_in[436]
    DIRECTION INPUT ;
    USE SIGNAL ;
    SHAPE ABUTMENT ;
    PORT
      LAYER metal3 ;
      RECT 370.265 0.000 370.335 0.070 ;
    END
  END w0_wd_in[436]
  PIN w0_wd_in[437]
    DIRECTION INPUT ;
    USE SIGNAL ;
    SHAPE ABUTMENT ;
    PORT
      LAYER metal3 ;
      RECT 370.405 0.000 370.475 0.070 ;
    END
  END w0_wd_in[437]
  PIN w0_wd_in[438]
    DIRECTION INPUT ;
    USE SIGNAL ;
    SHAPE ABUTMENT ;
    PORT
      LAYER metal3 ;
      RECT 370.545 0.000 370.615 0.070 ;
    END
  END w0_wd_in[438]
  PIN w0_wd_in[439]
    DIRECTION INPUT ;
    USE SIGNAL ;
    SHAPE ABUTMENT ;
    PORT
      LAYER metal3 ;
      RECT 370.685 0.000 370.755 0.070 ;
    END
  END w0_wd_in[439]
  PIN w0_wd_in[440]
    DIRECTION INPUT ;
    USE SIGNAL ;
    SHAPE ABUTMENT ;
    PORT
      LAYER metal3 ;
      RECT 370.825 0.000 370.895 0.070 ;
    END
  END w0_wd_in[440]
  PIN w0_wd_in[441]
    DIRECTION INPUT ;
    USE SIGNAL ;
    SHAPE ABUTMENT ;
    PORT
      LAYER metal3 ;
      RECT 370.965 0.000 371.035 0.070 ;
    END
  END w0_wd_in[441]
  PIN w0_wd_in[442]
    DIRECTION INPUT ;
    USE SIGNAL ;
    SHAPE ABUTMENT ;
    PORT
      LAYER metal3 ;
      RECT 371.105 0.000 371.175 0.070 ;
    END
  END w0_wd_in[442]
  PIN w0_wd_in[443]
    DIRECTION INPUT ;
    USE SIGNAL ;
    SHAPE ABUTMENT ;
    PORT
      LAYER metal3 ;
      RECT 371.245 0.000 371.315 0.070 ;
    END
  END w0_wd_in[443]
  PIN w0_wd_in[444]
    DIRECTION INPUT ;
    USE SIGNAL ;
    SHAPE ABUTMENT ;
    PORT
      LAYER metal3 ;
      RECT 371.385 0.000 371.455 0.070 ;
    END
  END w0_wd_in[444]
  PIN w0_wd_in[445]
    DIRECTION INPUT ;
    USE SIGNAL ;
    SHAPE ABUTMENT ;
    PORT
      LAYER metal3 ;
      RECT 371.525 0.000 371.595 0.070 ;
    END
  END w0_wd_in[445]
  PIN w0_wd_in[446]
    DIRECTION INPUT ;
    USE SIGNAL ;
    SHAPE ABUTMENT ;
    PORT
      LAYER metal3 ;
      RECT 371.665 0.000 371.735 0.070 ;
    END
  END w0_wd_in[446]
  PIN w0_wd_in[447]
    DIRECTION INPUT ;
    USE SIGNAL ;
    SHAPE ABUTMENT ;
    PORT
      LAYER metal3 ;
      RECT 371.805 0.000 371.875 0.070 ;
    END
  END w0_wd_in[447]
  PIN w0_wd_in[448]
    DIRECTION INPUT ;
    USE SIGNAL ;
    SHAPE ABUTMENT ;
    PORT
      LAYER metal3 ;
      RECT 371.945 0.000 372.015 0.070 ;
    END
  END w0_wd_in[448]
  PIN w0_wd_in[449]
    DIRECTION INPUT ;
    USE SIGNAL ;
    SHAPE ABUTMENT ;
    PORT
      LAYER metal3 ;
      RECT 372.085 0.000 372.155 0.070 ;
    END
  END w0_wd_in[449]
  PIN w0_wd_in[450]
    DIRECTION INPUT ;
    USE SIGNAL ;
    SHAPE ABUTMENT ;
    PORT
      LAYER metal3 ;
      RECT 372.225 0.000 372.295 0.070 ;
    END
  END w0_wd_in[450]
  PIN w0_wd_in[451]
    DIRECTION INPUT ;
    USE SIGNAL ;
    SHAPE ABUTMENT ;
    PORT
      LAYER metal3 ;
      RECT 372.365 0.000 372.435 0.070 ;
    END
  END w0_wd_in[451]
  PIN w0_wd_in[452]
    DIRECTION INPUT ;
    USE SIGNAL ;
    SHAPE ABUTMENT ;
    PORT
      LAYER metal3 ;
      RECT 372.505 0.000 372.575 0.070 ;
    END
  END w0_wd_in[452]
  PIN w0_wd_in[453]
    DIRECTION INPUT ;
    USE SIGNAL ;
    SHAPE ABUTMENT ;
    PORT
      LAYER metal3 ;
      RECT 372.645 0.000 372.715 0.070 ;
    END
  END w0_wd_in[453]
  PIN w0_wd_in[454]
    DIRECTION INPUT ;
    USE SIGNAL ;
    SHAPE ABUTMENT ;
    PORT
      LAYER metal3 ;
      RECT 372.785 0.000 372.855 0.070 ;
    END
  END w0_wd_in[454]
  PIN w0_wd_in[455]
    DIRECTION INPUT ;
    USE SIGNAL ;
    SHAPE ABUTMENT ;
    PORT
      LAYER metal3 ;
      RECT 372.925 0.000 372.995 0.070 ;
    END
  END w0_wd_in[455]
  PIN w0_wd_in[456]
    DIRECTION INPUT ;
    USE SIGNAL ;
    SHAPE ABUTMENT ;
    PORT
      LAYER metal3 ;
      RECT 373.065 0.000 373.135 0.070 ;
    END
  END w0_wd_in[456]
  PIN w0_wd_in[457]
    DIRECTION INPUT ;
    USE SIGNAL ;
    SHAPE ABUTMENT ;
    PORT
      LAYER metal3 ;
      RECT 373.205 0.000 373.275 0.070 ;
    END
  END w0_wd_in[457]
  PIN w0_wd_in[458]
    DIRECTION INPUT ;
    USE SIGNAL ;
    SHAPE ABUTMENT ;
    PORT
      LAYER metal3 ;
      RECT 373.345 0.000 373.415 0.070 ;
    END
  END w0_wd_in[458]
  PIN w0_wd_in[459]
    DIRECTION INPUT ;
    USE SIGNAL ;
    SHAPE ABUTMENT ;
    PORT
      LAYER metal3 ;
      RECT 373.485 0.000 373.555 0.070 ;
    END
  END w0_wd_in[459]
  PIN w0_wd_in[460]
    DIRECTION INPUT ;
    USE SIGNAL ;
    SHAPE ABUTMENT ;
    PORT
      LAYER metal3 ;
      RECT 373.625 0.000 373.695 0.070 ;
    END
  END w0_wd_in[460]
  PIN w0_wd_in[461]
    DIRECTION INPUT ;
    USE SIGNAL ;
    SHAPE ABUTMENT ;
    PORT
      LAYER metal3 ;
      RECT 373.765 0.000 373.835 0.070 ;
    END
  END w0_wd_in[461]
  PIN w0_wd_in[462]
    DIRECTION INPUT ;
    USE SIGNAL ;
    SHAPE ABUTMENT ;
    PORT
      LAYER metal3 ;
      RECT 373.905 0.000 373.975 0.070 ;
    END
  END w0_wd_in[462]
  PIN w0_wd_in[463]
    DIRECTION INPUT ;
    USE SIGNAL ;
    SHAPE ABUTMENT ;
    PORT
      LAYER metal3 ;
      RECT 374.045 0.000 374.115 0.070 ;
    END
  END w0_wd_in[463]
  PIN w0_wd_in[464]
    DIRECTION INPUT ;
    USE SIGNAL ;
    SHAPE ABUTMENT ;
    PORT
      LAYER metal3 ;
      RECT 374.185 0.000 374.255 0.070 ;
    END
  END w0_wd_in[464]
  PIN w0_wd_in[465]
    DIRECTION INPUT ;
    USE SIGNAL ;
    SHAPE ABUTMENT ;
    PORT
      LAYER metal3 ;
      RECT 374.325 0.000 374.395 0.070 ;
    END
  END w0_wd_in[465]
  PIN w0_wd_in[466]
    DIRECTION INPUT ;
    USE SIGNAL ;
    SHAPE ABUTMENT ;
    PORT
      LAYER metal3 ;
      RECT 374.465 0.000 374.535 0.070 ;
    END
  END w0_wd_in[466]
  PIN w0_wd_in[467]
    DIRECTION INPUT ;
    USE SIGNAL ;
    SHAPE ABUTMENT ;
    PORT
      LAYER metal3 ;
      RECT 374.605 0.000 374.675 0.070 ;
    END
  END w0_wd_in[467]
  PIN w0_wd_in[468]
    DIRECTION INPUT ;
    USE SIGNAL ;
    SHAPE ABUTMENT ;
    PORT
      LAYER metal3 ;
      RECT 374.745 0.000 374.815 0.070 ;
    END
  END w0_wd_in[468]
  PIN w0_wd_in[469]
    DIRECTION INPUT ;
    USE SIGNAL ;
    SHAPE ABUTMENT ;
    PORT
      LAYER metal3 ;
      RECT 374.885 0.000 374.955 0.070 ;
    END
  END w0_wd_in[469]
  PIN w0_wd_in[470]
    DIRECTION INPUT ;
    USE SIGNAL ;
    SHAPE ABUTMENT ;
    PORT
      LAYER metal3 ;
      RECT 375.025 0.000 375.095 0.070 ;
    END
  END w0_wd_in[470]
  PIN w0_wd_in[471]
    DIRECTION INPUT ;
    USE SIGNAL ;
    SHAPE ABUTMENT ;
    PORT
      LAYER metal3 ;
      RECT 375.165 0.000 375.235 0.070 ;
    END
  END w0_wd_in[471]
  PIN w0_wd_in[472]
    DIRECTION INPUT ;
    USE SIGNAL ;
    SHAPE ABUTMENT ;
    PORT
      LAYER metal3 ;
      RECT 375.305 0.000 375.375 0.070 ;
    END
  END w0_wd_in[472]
  PIN w0_wd_in[473]
    DIRECTION INPUT ;
    USE SIGNAL ;
    SHAPE ABUTMENT ;
    PORT
      LAYER metal3 ;
      RECT 375.445 0.000 375.515 0.070 ;
    END
  END w0_wd_in[473]
  PIN w0_wd_in[474]
    DIRECTION INPUT ;
    USE SIGNAL ;
    SHAPE ABUTMENT ;
    PORT
      LAYER metal3 ;
      RECT 375.585 0.000 375.655 0.070 ;
    END
  END w0_wd_in[474]
  PIN w0_wd_in[475]
    DIRECTION INPUT ;
    USE SIGNAL ;
    SHAPE ABUTMENT ;
    PORT
      LAYER metal3 ;
      RECT 375.725 0.000 375.795 0.070 ;
    END
  END w0_wd_in[475]
  PIN w0_wd_in[476]
    DIRECTION INPUT ;
    USE SIGNAL ;
    SHAPE ABUTMENT ;
    PORT
      LAYER metal3 ;
      RECT 375.865 0.000 375.935 0.070 ;
    END
  END w0_wd_in[476]
  PIN w0_wd_in[477]
    DIRECTION INPUT ;
    USE SIGNAL ;
    SHAPE ABUTMENT ;
    PORT
      LAYER metal3 ;
      RECT 376.005 0.000 376.075 0.070 ;
    END
  END w0_wd_in[477]
  PIN w0_wd_in[478]
    DIRECTION INPUT ;
    USE SIGNAL ;
    SHAPE ABUTMENT ;
    PORT
      LAYER metal3 ;
      RECT 376.145 0.000 376.215 0.070 ;
    END
  END w0_wd_in[478]
  PIN w0_wd_in[479]
    DIRECTION INPUT ;
    USE SIGNAL ;
    SHAPE ABUTMENT ;
    PORT
      LAYER metal3 ;
      RECT 376.285 0.000 376.355 0.070 ;
    END
  END w0_wd_in[479]
  PIN w0_wd_in[480]
    DIRECTION INPUT ;
    USE SIGNAL ;
    SHAPE ABUTMENT ;
    PORT
      LAYER metal3 ;
      RECT 376.425 0.000 376.495 0.070 ;
    END
  END w0_wd_in[480]
  PIN w0_wd_in[481]
    DIRECTION INPUT ;
    USE SIGNAL ;
    SHAPE ABUTMENT ;
    PORT
      LAYER metal3 ;
      RECT 376.565 0.000 376.635 0.070 ;
    END
  END w0_wd_in[481]
  PIN w0_wd_in[482]
    DIRECTION INPUT ;
    USE SIGNAL ;
    SHAPE ABUTMENT ;
    PORT
      LAYER metal3 ;
      RECT 376.705 0.000 376.775 0.070 ;
    END
  END w0_wd_in[482]
  PIN w0_wd_in[483]
    DIRECTION INPUT ;
    USE SIGNAL ;
    SHAPE ABUTMENT ;
    PORT
      LAYER metal3 ;
      RECT 376.845 0.000 376.915 0.070 ;
    END
  END w0_wd_in[483]
  PIN w0_wd_in[484]
    DIRECTION INPUT ;
    USE SIGNAL ;
    SHAPE ABUTMENT ;
    PORT
      LAYER metal3 ;
      RECT 376.985 0.000 377.055 0.070 ;
    END
  END w0_wd_in[484]
  PIN w0_wd_in[485]
    DIRECTION INPUT ;
    USE SIGNAL ;
    SHAPE ABUTMENT ;
    PORT
      LAYER metal3 ;
      RECT 377.125 0.000 377.195 0.070 ;
    END
  END w0_wd_in[485]
  PIN w0_wd_in[486]
    DIRECTION INPUT ;
    USE SIGNAL ;
    SHAPE ABUTMENT ;
    PORT
      LAYER metal3 ;
      RECT 377.265 0.000 377.335 0.070 ;
    END
  END w0_wd_in[486]
  PIN w0_wd_in[487]
    DIRECTION INPUT ;
    USE SIGNAL ;
    SHAPE ABUTMENT ;
    PORT
      LAYER metal3 ;
      RECT 377.405 0.000 377.475 0.070 ;
    END
  END w0_wd_in[487]
  PIN w0_wd_in[488]
    DIRECTION INPUT ;
    USE SIGNAL ;
    SHAPE ABUTMENT ;
    PORT
      LAYER metal3 ;
      RECT 377.545 0.000 377.615 0.070 ;
    END
  END w0_wd_in[488]
  PIN w0_wd_in[489]
    DIRECTION INPUT ;
    USE SIGNAL ;
    SHAPE ABUTMENT ;
    PORT
      LAYER metal3 ;
      RECT 377.685 0.000 377.755 0.070 ;
    END
  END w0_wd_in[489]
  PIN w0_wd_in[490]
    DIRECTION INPUT ;
    USE SIGNAL ;
    SHAPE ABUTMENT ;
    PORT
      LAYER metal3 ;
      RECT 377.825 0.000 377.895 0.070 ;
    END
  END w0_wd_in[490]
  PIN w0_wd_in[491]
    DIRECTION INPUT ;
    USE SIGNAL ;
    SHAPE ABUTMENT ;
    PORT
      LAYER metal3 ;
      RECT 377.965 0.000 378.035 0.070 ;
    END
  END w0_wd_in[491]
  PIN w0_wd_in[492]
    DIRECTION INPUT ;
    USE SIGNAL ;
    SHAPE ABUTMENT ;
    PORT
      LAYER metal3 ;
      RECT 378.105 0.000 378.175 0.070 ;
    END
  END w0_wd_in[492]
  PIN w0_wd_in[493]
    DIRECTION INPUT ;
    USE SIGNAL ;
    SHAPE ABUTMENT ;
    PORT
      LAYER metal3 ;
      RECT 378.245 0.000 378.315 0.070 ;
    END
  END w0_wd_in[493]
  PIN w0_wd_in[494]
    DIRECTION INPUT ;
    USE SIGNAL ;
    SHAPE ABUTMENT ;
    PORT
      LAYER metal3 ;
      RECT 378.385 0.000 378.455 0.070 ;
    END
  END w0_wd_in[494]
  PIN w0_wd_in[495]
    DIRECTION INPUT ;
    USE SIGNAL ;
    SHAPE ABUTMENT ;
    PORT
      LAYER metal3 ;
      RECT 378.525 0.000 378.595 0.070 ;
    END
  END w0_wd_in[495]
  PIN w0_wd_in[496]
    DIRECTION INPUT ;
    USE SIGNAL ;
    SHAPE ABUTMENT ;
    PORT
      LAYER metal3 ;
      RECT 378.665 0.000 378.735 0.070 ;
    END
  END w0_wd_in[496]
  PIN w0_wd_in[497]
    DIRECTION INPUT ;
    USE SIGNAL ;
    SHAPE ABUTMENT ;
    PORT
      LAYER metal3 ;
      RECT 378.805 0.000 378.875 0.070 ;
    END
  END w0_wd_in[497]
  PIN w0_wd_in[498]
    DIRECTION INPUT ;
    USE SIGNAL ;
    SHAPE ABUTMENT ;
    PORT
      LAYER metal3 ;
      RECT 378.945 0.000 379.015 0.070 ;
    END
  END w0_wd_in[498]
  PIN w0_wd_in[499]
    DIRECTION INPUT ;
    USE SIGNAL ;
    SHAPE ABUTMENT ;
    PORT
      LAYER metal3 ;
      RECT 379.085 0.000 379.155 0.070 ;
    END
  END w0_wd_in[499]
  PIN w0_wd_in[500]
    DIRECTION INPUT ;
    USE SIGNAL ;
    SHAPE ABUTMENT ;
    PORT
      LAYER metal3 ;
      RECT 379.225 0.000 379.295 0.070 ;
    END
  END w0_wd_in[500]
  PIN w0_wd_in[501]
    DIRECTION INPUT ;
    USE SIGNAL ;
    SHAPE ABUTMENT ;
    PORT
      LAYER metal3 ;
      RECT 379.365 0.000 379.435 0.070 ;
    END
  END w0_wd_in[501]
  PIN w0_wd_in[502]
    DIRECTION INPUT ;
    USE SIGNAL ;
    SHAPE ABUTMENT ;
    PORT
      LAYER metal3 ;
      RECT 379.505 0.000 379.575 0.070 ;
    END
  END w0_wd_in[502]
  PIN w0_wd_in[503]
    DIRECTION INPUT ;
    USE SIGNAL ;
    SHAPE ABUTMENT ;
    PORT
      LAYER metal3 ;
      RECT 379.645 0.000 379.715 0.070 ;
    END
  END w0_wd_in[503]
  PIN w0_wd_in[504]
    DIRECTION INPUT ;
    USE SIGNAL ;
    SHAPE ABUTMENT ;
    PORT
      LAYER metal3 ;
      RECT 379.785 0.000 379.855 0.070 ;
    END
  END w0_wd_in[504]
  PIN w0_wd_in[505]
    DIRECTION INPUT ;
    USE SIGNAL ;
    SHAPE ABUTMENT ;
    PORT
      LAYER metal3 ;
      RECT 379.925 0.000 379.995 0.070 ;
    END
  END w0_wd_in[505]
  PIN w0_wd_in[506]
    DIRECTION INPUT ;
    USE SIGNAL ;
    SHAPE ABUTMENT ;
    PORT
      LAYER metal3 ;
      RECT 380.065 0.000 380.135 0.070 ;
    END
  END w0_wd_in[506]
  PIN w0_wd_in[507]
    DIRECTION INPUT ;
    USE SIGNAL ;
    SHAPE ABUTMENT ;
    PORT
      LAYER metal3 ;
      RECT 380.205 0.000 380.275 0.070 ;
    END
  END w0_wd_in[507]
  PIN w0_wd_in[508]
    DIRECTION INPUT ;
    USE SIGNAL ;
    SHAPE ABUTMENT ;
    PORT
      LAYER metal3 ;
      RECT 380.345 0.000 380.415 0.070 ;
    END
  END w0_wd_in[508]
  PIN w0_wd_in[509]
    DIRECTION INPUT ;
    USE SIGNAL ;
    SHAPE ABUTMENT ;
    PORT
      LAYER metal3 ;
      RECT 380.485 0.000 380.555 0.070 ;
    END
  END w0_wd_in[509]
  PIN w0_wd_in[510]
    DIRECTION INPUT ;
    USE SIGNAL ;
    SHAPE ABUTMENT ;
    PORT
      LAYER metal3 ;
      RECT 380.625 0.000 380.695 0.070 ;
    END
  END w0_wd_in[510]
  PIN w0_wd_in[511]
    DIRECTION INPUT ;
    USE SIGNAL ;
    SHAPE ABUTMENT ;
    PORT
      LAYER metal3 ;
      RECT 380.765 0.000 380.835 0.070 ;
    END
  END w0_wd_in[511]
  PIN VSS
    DIRECTION INOUT ;
    USE GROUND ;
    PORT
      LAYER metal4 ;
      RECT 2.450 0.140 2.730 769.930 ;
      RECT 4.690 0.140 4.970 769.930 ;
      RECT 6.930 0.140 7.210 769.930 ;
      RECT 9.170 0.140 9.450 769.930 ;
      RECT 11.410 0.140 11.690 769.930 ;
      RECT 13.650 0.140 13.930 769.930 ;
      RECT 15.890 0.140 16.170 769.930 ;
      RECT 18.130 0.140 18.410 769.930 ;
      RECT 20.370 0.140 20.650 769.930 ;
      RECT 22.610 0.140 22.890 769.930 ;
      RECT 24.850 0.140 25.130 769.930 ;
      RECT 27.090 0.140 27.370 769.930 ;
      RECT 29.330 0.140 29.610 769.930 ;
      RECT 31.570 0.140 31.850 769.930 ;
      RECT 33.810 0.140 34.090 769.930 ;
      RECT 36.050 0.140 36.330 769.930 ;
      RECT 38.290 0.140 38.570 769.930 ;
      RECT 40.530 0.140 40.810 769.930 ;
      RECT 42.770 0.140 43.050 769.930 ;
      RECT 45.010 0.140 45.290 769.930 ;
      RECT 47.250 0.140 47.530 769.930 ;
      RECT 49.490 0.140 49.770 769.930 ;
      RECT 51.730 0.140 52.010 769.930 ;
      RECT 53.970 0.140 54.250 769.930 ;
      RECT 56.210 0.140 56.490 769.930 ;
      RECT 58.450 0.140 58.730 769.930 ;
      RECT 60.690 0.140 60.970 769.930 ;
      RECT 62.930 0.140 63.210 769.930 ;
      RECT 65.170 0.140 65.450 769.930 ;
      RECT 67.410 0.140 67.690 769.930 ;
      RECT 69.650 0.140 69.930 769.930 ;
      RECT 71.890 0.140 72.170 769.930 ;
      RECT 74.130 0.140 74.410 769.930 ;
      RECT 76.370 0.140 76.650 769.930 ;
      RECT 78.610 0.140 78.890 769.930 ;
      RECT 80.850 0.140 81.130 769.930 ;
      RECT 83.090 0.140 83.370 769.930 ;
      RECT 85.330 0.140 85.610 769.930 ;
      RECT 87.570 0.140 87.850 769.930 ;
      RECT 89.810 0.140 90.090 769.930 ;
      RECT 92.050 0.140 92.330 769.930 ;
      RECT 94.290 0.140 94.570 769.930 ;
      RECT 96.530 0.140 96.810 769.930 ;
      RECT 98.770 0.140 99.050 769.930 ;
      RECT 101.010 0.140 101.290 769.930 ;
      RECT 103.250 0.140 103.530 769.930 ;
      RECT 105.490 0.140 105.770 769.930 ;
      RECT 107.730 0.140 108.010 769.930 ;
      RECT 109.970 0.140 110.250 769.930 ;
      RECT 112.210 0.140 112.490 769.930 ;
      RECT 114.450 0.140 114.730 769.930 ;
      RECT 116.690 0.140 116.970 769.930 ;
      RECT 118.930 0.140 119.210 769.930 ;
      RECT 121.170 0.140 121.450 769.930 ;
      RECT 123.410 0.140 123.690 769.930 ;
      RECT 125.650 0.140 125.930 769.930 ;
      RECT 127.890 0.140 128.170 769.930 ;
      RECT 130.130 0.140 130.410 769.930 ;
      RECT 132.370 0.140 132.650 769.930 ;
      RECT 134.610 0.140 134.890 769.930 ;
      RECT 136.850 0.140 137.130 769.930 ;
      RECT 139.090 0.140 139.370 769.930 ;
      RECT 141.330 0.140 141.610 769.930 ;
      RECT 143.570 0.140 143.850 769.930 ;
      RECT 145.810 0.140 146.090 769.930 ;
      RECT 148.050 0.140 148.330 769.930 ;
      RECT 150.290 0.140 150.570 769.930 ;
      RECT 152.530 0.140 152.810 769.930 ;
      RECT 154.770 0.140 155.050 769.930 ;
      RECT 157.010 0.140 157.290 769.930 ;
      RECT 159.250 0.140 159.530 769.930 ;
      RECT 161.490 0.140 161.770 769.930 ;
      RECT 163.730 0.140 164.010 769.930 ;
      RECT 165.970 0.140 166.250 769.930 ;
      RECT 168.210 0.140 168.490 769.930 ;
      RECT 170.450 0.140 170.730 769.930 ;
      RECT 172.690 0.140 172.970 769.930 ;
      RECT 174.930 0.140 175.210 769.930 ;
      RECT 177.170 0.140 177.450 769.930 ;
      RECT 179.410 0.140 179.690 769.930 ;
      RECT 181.650 0.140 181.930 769.930 ;
      RECT 183.890 0.140 184.170 769.930 ;
      RECT 186.130 0.140 186.410 769.930 ;
      RECT 188.370 0.140 188.650 769.930 ;
      RECT 190.610 0.140 190.890 769.930 ;
      RECT 192.850 0.140 193.130 769.930 ;
      RECT 195.090 0.140 195.370 769.930 ;
      RECT 197.330 0.140 197.610 769.930 ;
      RECT 199.570 0.140 199.850 769.930 ;
      RECT 201.810 0.140 202.090 769.930 ;
      RECT 204.050 0.140 204.330 769.930 ;
      RECT 206.290 0.140 206.570 769.930 ;
      RECT 208.530 0.140 208.810 769.930 ;
      RECT 210.770 0.140 211.050 769.930 ;
      RECT 213.010 0.140 213.290 769.930 ;
      RECT 215.250 0.140 215.530 769.930 ;
      RECT 217.490 0.140 217.770 769.930 ;
      RECT 219.730 0.140 220.010 769.930 ;
      RECT 221.970 0.140 222.250 769.930 ;
      RECT 224.210 0.140 224.490 769.930 ;
      RECT 226.450 0.140 226.730 769.930 ;
      RECT 228.690 0.140 228.970 769.930 ;
      RECT 230.930 0.140 231.210 769.930 ;
      RECT 233.170 0.140 233.450 769.930 ;
      RECT 235.410 0.140 235.690 769.930 ;
      RECT 237.650 0.140 237.930 769.930 ;
      RECT 239.890 0.140 240.170 769.930 ;
      RECT 242.130 0.140 242.410 769.930 ;
      RECT 244.370 0.140 244.650 769.930 ;
      RECT 246.610 0.140 246.890 769.930 ;
      RECT 248.850 0.140 249.130 769.930 ;
      RECT 251.090 0.140 251.370 769.930 ;
      RECT 253.330 0.140 253.610 769.930 ;
      RECT 255.570 0.140 255.850 769.930 ;
      RECT 257.810 0.140 258.090 769.930 ;
      RECT 260.050 0.140 260.330 769.930 ;
      RECT 262.290 0.140 262.570 769.930 ;
      RECT 264.530 0.140 264.810 769.930 ;
      RECT 266.770 0.140 267.050 769.930 ;
      RECT 269.010 0.140 269.290 769.930 ;
      RECT 271.250 0.140 271.530 769.930 ;
      RECT 273.490 0.140 273.770 769.930 ;
      RECT 275.730 0.140 276.010 769.930 ;
      RECT 277.970 0.140 278.250 769.930 ;
      RECT 280.210 0.140 280.490 769.930 ;
      RECT 282.450 0.140 282.730 769.930 ;
      RECT 284.690 0.140 284.970 769.930 ;
      RECT 286.930 0.140 287.210 769.930 ;
      RECT 289.170 0.140 289.450 769.930 ;
      RECT 291.410 0.140 291.690 769.930 ;
      RECT 293.650 0.140 293.930 769.930 ;
      RECT 295.890 0.140 296.170 769.930 ;
      RECT 298.130 0.140 298.410 769.930 ;
      RECT 300.370 0.140 300.650 769.930 ;
      RECT 302.610 0.140 302.890 769.930 ;
      RECT 304.850 0.140 305.130 769.930 ;
      RECT 307.090 0.140 307.370 769.930 ;
      RECT 309.330 0.140 309.610 769.930 ;
      RECT 311.570 0.140 311.850 769.930 ;
      RECT 313.810 0.140 314.090 769.930 ;
      RECT 316.050 0.140 316.330 769.930 ;
      RECT 318.290 0.140 318.570 769.930 ;
      RECT 320.530 0.140 320.810 769.930 ;
      RECT 322.770 0.140 323.050 769.930 ;
      RECT 325.010 0.140 325.290 769.930 ;
      RECT 327.250 0.140 327.530 769.930 ;
      RECT 329.490 0.140 329.770 769.930 ;
      RECT 331.730 0.140 332.010 769.930 ;
      RECT 333.970 0.140 334.250 769.930 ;
      RECT 336.210 0.140 336.490 769.930 ;
      RECT 338.450 0.140 338.730 769.930 ;
      RECT 340.690 0.140 340.970 769.930 ;
      RECT 342.930 0.140 343.210 769.930 ;
      RECT 345.170 0.140 345.450 769.930 ;
      RECT 347.410 0.140 347.690 769.930 ;
      RECT 349.650 0.140 349.930 769.930 ;
      RECT 351.890 0.140 352.170 769.930 ;
      RECT 354.130 0.140 354.410 769.930 ;
      RECT 356.370 0.140 356.650 769.930 ;
      RECT 358.610 0.140 358.890 769.930 ;
      RECT 360.850 0.140 361.130 769.930 ;
      RECT 363.090 0.140 363.370 769.930 ;
      RECT 365.330 0.140 365.610 769.930 ;
      RECT 367.570 0.140 367.850 769.930 ;
      RECT 369.810 0.140 370.090 769.930 ;
      RECT 372.050 0.140 372.330 769.930 ;
      RECT 374.290 0.140 374.570 769.930 ;
      RECT 376.530 0.140 376.810 769.930 ;
      RECT 378.770 0.140 379.050 769.930 ;
      RECT 381.010 0.140 381.290 769.930 ;
      RECT 383.250 0.140 383.530 769.930 ;
      RECT 385.490 0.140 385.770 769.930 ;
      RECT 387.730 0.140 388.010 769.930 ;
      RECT 389.970 0.140 390.250 769.930 ;
      RECT 392.210 0.140 392.490 769.930 ;
      RECT 394.450 0.140 394.730 769.930 ;
      RECT 396.690 0.140 396.970 769.930 ;
      RECT 398.930 0.140 399.210 769.930 ;
      RECT 401.170 0.140 401.450 769.930 ;
      RECT 403.410 0.140 403.690 769.930 ;
      RECT 405.650 0.140 405.930 769.930 ;
      RECT 407.890 0.140 408.170 769.930 ;
      RECT 410.130 0.140 410.410 769.930 ;
      RECT 412.370 0.140 412.650 769.930 ;
      RECT 414.610 0.140 414.890 769.930 ;
      RECT 416.850 0.140 417.130 769.930 ;
      RECT 419.090 0.140 419.370 769.930 ;
      RECT 421.330 0.140 421.610 769.930 ;
      RECT 423.570 0.140 423.850 769.930 ;
      RECT 425.810 0.140 426.090 769.930 ;
      RECT 428.050 0.140 428.330 769.930 ;
      RECT 430.290 0.140 430.570 769.930 ;
      RECT 432.530 0.140 432.810 769.930 ;
      RECT 434.770 0.140 435.050 769.930 ;
      RECT 437.010 0.140 437.290 769.930 ;
      RECT 439.250 0.140 439.530 769.930 ;
      RECT 441.490 0.140 441.770 769.930 ;
      RECT 443.730 0.140 444.010 769.930 ;
      RECT 445.970 0.140 446.250 769.930 ;
      RECT 448.210 0.140 448.490 769.930 ;
      RECT 450.450 0.140 450.730 769.930 ;
      RECT 452.690 0.140 452.970 769.930 ;
      RECT 454.930 0.140 455.210 769.930 ;
      RECT 457.170 0.140 457.450 769.930 ;
      RECT 459.410 0.140 459.690 769.930 ;
      RECT 461.650 0.140 461.930 769.930 ;
      RECT 463.890 0.140 464.170 769.930 ;
      RECT 466.130 0.140 466.410 769.930 ;
      RECT 468.370 0.140 468.650 769.930 ;
      RECT 470.610 0.140 470.890 769.930 ;
      RECT 472.850 0.140 473.130 769.930 ;
      RECT 475.090 0.140 475.370 769.930 ;
      RECT 477.330 0.140 477.610 769.930 ;
      RECT 479.570 0.140 479.850 769.930 ;
      RECT 481.810 0.140 482.090 769.930 ;
      RECT 484.050 0.140 484.330 769.930 ;
      RECT 486.290 0.140 486.570 769.930 ;
      RECT 488.530 0.140 488.810 769.930 ;
      RECT 490.770 0.140 491.050 769.930 ;
      RECT 493.010 0.140 493.290 769.930 ;
      RECT 495.250 0.140 495.530 769.930 ;
      RECT 497.490 0.140 497.770 769.930 ;
      RECT 499.730 0.140 500.010 769.930 ;
      RECT 501.970 0.140 502.250 769.930 ;
      RECT 504.210 0.140 504.490 769.930 ;
      RECT 506.450 0.140 506.730 769.930 ;
      RECT 508.690 0.140 508.970 769.930 ;
      RECT 510.930 0.140 511.210 769.930 ;
      RECT 513.170 0.140 513.450 769.930 ;
      RECT 515.410 0.140 515.690 769.930 ;
      RECT 517.650 0.140 517.930 769.930 ;
      RECT 519.890 0.140 520.170 769.930 ;
      RECT 522.130 0.140 522.410 769.930 ;
      RECT 524.370 0.140 524.650 769.930 ;
      RECT 526.610 0.140 526.890 769.930 ;
      RECT 528.850 0.140 529.130 769.930 ;
      RECT 531.090 0.140 531.370 769.930 ;
      RECT 533.330 0.140 533.610 769.930 ;
      RECT 535.570 0.140 535.850 769.930 ;
      RECT 537.810 0.140 538.090 769.930 ;
      RECT 540.050 0.140 540.330 769.930 ;
      RECT 542.290 0.140 542.570 769.930 ;
      RECT 544.530 0.140 544.810 769.930 ;
      RECT 546.770 0.140 547.050 769.930 ;
      RECT 549.010 0.140 549.290 769.930 ;
      RECT 551.250 0.140 551.530 769.930 ;
      RECT 553.490 0.140 553.770 769.930 ;
      RECT 555.730 0.140 556.010 769.930 ;
      RECT 557.970 0.140 558.250 769.930 ;
      RECT 560.210 0.140 560.490 769.930 ;
      RECT 562.450 0.140 562.730 769.930 ;
      RECT 564.690 0.140 564.970 769.930 ;
      RECT 566.930 0.140 567.210 769.930 ;
      RECT 569.170 0.140 569.450 769.930 ;
      RECT 571.410 0.140 571.690 769.930 ;
      RECT 573.650 0.140 573.930 769.930 ;
      RECT 575.890 0.140 576.170 769.930 ;
      RECT 578.130 0.140 578.410 769.930 ;
      RECT 580.370 0.140 580.650 769.930 ;
      RECT 582.610 0.140 582.890 769.930 ;
      RECT 584.850 0.140 585.130 769.930 ;
      RECT 587.090 0.140 587.370 769.930 ;
      RECT 589.330 0.140 589.610 769.930 ;
      RECT 591.570 0.140 591.850 769.930 ;
      RECT 593.810 0.140 594.090 769.930 ;
      RECT 596.050 0.140 596.330 769.930 ;
      RECT 598.290 0.140 598.570 769.930 ;
      RECT 600.530 0.140 600.810 769.930 ;
      RECT 602.770 0.140 603.050 769.930 ;
      RECT 605.010 0.140 605.290 769.930 ;
      RECT 607.250 0.140 607.530 769.930 ;
      RECT 609.490 0.140 609.770 769.930 ;
      RECT 611.730 0.140 612.010 769.930 ;
      RECT 613.970 0.140 614.250 769.930 ;
      RECT 616.210 0.140 616.490 769.930 ;
      RECT 618.450 0.140 618.730 769.930 ;
      RECT 620.690 0.140 620.970 769.930 ;
      RECT 622.930 0.140 623.210 769.930 ;
      RECT 625.170 0.140 625.450 769.930 ;
      RECT 627.410 0.140 627.690 769.930 ;
      RECT 629.650 0.140 629.930 769.930 ;
      RECT 631.890 0.140 632.170 769.930 ;
      RECT 634.130 0.140 634.410 769.930 ;
      RECT 636.370 0.140 636.650 769.930 ;
      RECT 638.610 0.140 638.890 769.930 ;
      RECT 640.850 0.140 641.130 769.930 ;
      RECT 643.090 0.140 643.370 769.930 ;
      RECT 645.330 0.140 645.610 769.930 ;
      RECT 647.570 0.140 647.850 769.930 ;
      RECT 649.810 0.140 650.090 769.930 ;
      RECT 652.050 0.140 652.330 769.930 ;
      RECT 654.290 0.140 654.570 769.930 ;
      RECT 656.530 0.140 656.810 769.930 ;
      RECT 658.770 0.140 659.050 769.930 ;
      RECT 661.010 0.140 661.290 769.930 ;
      RECT 663.250 0.140 663.530 769.930 ;
      RECT 665.490 0.140 665.770 769.930 ;
      RECT 667.730 0.140 668.010 769.930 ;
      RECT 669.970 0.140 670.250 769.930 ;
      RECT 672.210 0.140 672.490 769.930 ;
      RECT 674.450 0.140 674.730 769.930 ;
      RECT 676.690 0.140 676.970 769.930 ;
      RECT 678.930 0.140 679.210 769.930 ;
      RECT 681.170 0.140 681.450 769.930 ;
      RECT 683.410 0.140 683.690 769.930 ;
      RECT 685.650 0.140 685.930 769.930 ;
      RECT 687.890 0.140 688.170 769.930 ;
    END
  END VSS
  PIN VDD
    DIRECTION INOUT ;
    USE POWER ;
    PORT
      LAYER metal4 ;
      RECT 1.330 0.140 1.610 769.930 ;
      RECT 3.570 0.140 3.850 769.930 ;
      RECT 5.810 0.140 6.090 769.930 ;
      RECT 8.050 0.140 8.330 769.930 ;
      RECT 10.290 0.140 10.570 769.930 ;
      RECT 12.530 0.140 12.810 769.930 ;
      RECT 14.770 0.140 15.050 769.930 ;
      RECT 17.010 0.140 17.290 769.930 ;
      RECT 19.250 0.140 19.530 769.930 ;
      RECT 21.490 0.140 21.770 769.930 ;
      RECT 23.730 0.140 24.010 769.930 ;
      RECT 25.970 0.140 26.250 769.930 ;
      RECT 28.210 0.140 28.490 769.930 ;
      RECT 30.450 0.140 30.730 769.930 ;
      RECT 32.690 0.140 32.970 769.930 ;
      RECT 34.930 0.140 35.210 769.930 ;
      RECT 37.170 0.140 37.450 769.930 ;
      RECT 39.410 0.140 39.690 769.930 ;
      RECT 41.650 0.140 41.930 769.930 ;
      RECT 43.890 0.140 44.170 769.930 ;
      RECT 46.130 0.140 46.410 769.930 ;
      RECT 48.370 0.140 48.650 769.930 ;
      RECT 50.610 0.140 50.890 769.930 ;
      RECT 52.850 0.140 53.130 769.930 ;
      RECT 55.090 0.140 55.370 769.930 ;
      RECT 57.330 0.140 57.610 769.930 ;
      RECT 59.570 0.140 59.850 769.930 ;
      RECT 61.810 0.140 62.090 769.930 ;
      RECT 64.050 0.140 64.330 769.930 ;
      RECT 66.290 0.140 66.570 769.930 ;
      RECT 68.530 0.140 68.810 769.930 ;
      RECT 70.770 0.140 71.050 769.930 ;
      RECT 73.010 0.140 73.290 769.930 ;
      RECT 75.250 0.140 75.530 769.930 ;
      RECT 77.490 0.140 77.770 769.930 ;
      RECT 79.730 0.140 80.010 769.930 ;
      RECT 81.970 0.140 82.250 769.930 ;
      RECT 84.210 0.140 84.490 769.930 ;
      RECT 86.450 0.140 86.730 769.930 ;
      RECT 88.690 0.140 88.970 769.930 ;
      RECT 90.930 0.140 91.210 769.930 ;
      RECT 93.170 0.140 93.450 769.930 ;
      RECT 95.410 0.140 95.690 769.930 ;
      RECT 97.650 0.140 97.930 769.930 ;
      RECT 99.890 0.140 100.170 769.930 ;
      RECT 102.130 0.140 102.410 769.930 ;
      RECT 104.370 0.140 104.650 769.930 ;
      RECT 106.610 0.140 106.890 769.930 ;
      RECT 108.850 0.140 109.130 769.930 ;
      RECT 111.090 0.140 111.370 769.930 ;
      RECT 113.330 0.140 113.610 769.930 ;
      RECT 115.570 0.140 115.850 769.930 ;
      RECT 117.810 0.140 118.090 769.930 ;
      RECT 120.050 0.140 120.330 769.930 ;
      RECT 122.290 0.140 122.570 769.930 ;
      RECT 124.530 0.140 124.810 769.930 ;
      RECT 126.770 0.140 127.050 769.930 ;
      RECT 129.010 0.140 129.290 769.930 ;
      RECT 131.250 0.140 131.530 769.930 ;
      RECT 133.490 0.140 133.770 769.930 ;
      RECT 135.730 0.140 136.010 769.930 ;
      RECT 137.970 0.140 138.250 769.930 ;
      RECT 140.210 0.140 140.490 769.930 ;
      RECT 142.450 0.140 142.730 769.930 ;
      RECT 144.690 0.140 144.970 769.930 ;
      RECT 146.930 0.140 147.210 769.930 ;
      RECT 149.170 0.140 149.450 769.930 ;
      RECT 151.410 0.140 151.690 769.930 ;
      RECT 153.650 0.140 153.930 769.930 ;
      RECT 155.890 0.140 156.170 769.930 ;
      RECT 158.130 0.140 158.410 769.930 ;
      RECT 160.370 0.140 160.650 769.930 ;
      RECT 162.610 0.140 162.890 769.930 ;
      RECT 164.850 0.140 165.130 769.930 ;
      RECT 167.090 0.140 167.370 769.930 ;
      RECT 169.330 0.140 169.610 769.930 ;
      RECT 171.570 0.140 171.850 769.930 ;
      RECT 173.810 0.140 174.090 769.930 ;
      RECT 176.050 0.140 176.330 769.930 ;
      RECT 178.290 0.140 178.570 769.930 ;
      RECT 180.530 0.140 180.810 769.930 ;
      RECT 182.770 0.140 183.050 769.930 ;
      RECT 185.010 0.140 185.290 769.930 ;
      RECT 187.250 0.140 187.530 769.930 ;
      RECT 189.490 0.140 189.770 769.930 ;
      RECT 191.730 0.140 192.010 769.930 ;
      RECT 193.970 0.140 194.250 769.930 ;
      RECT 196.210 0.140 196.490 769.930 ;
      RECT 198.450 0.140 198.730 769.930 ;
      RECT 200.690 0.140 200.970 769.930 ;
      RECT 202.930 0.140 203.210 769.930 ;
      RECT 205.170 0.140 205.450 769.930 ;
      RECT 207.410 0.140 207.690 769.930 ;
      RECT 209.650 0.140 209.930 769.930 ;
      RECT 211.890 0.140 212.170 769.930 ;
      RECT 214.130 0.140 214.410 769.930 ;
      RECT 216.370 0.140 216.650 769.930 ;
      RECT 218.610 0.140 218.890 769.930 ;
      RECT 220.850 0.140 221.130 769.930 ;
      RECT 223.090 0.140 223.370 769.930 ;
      RECT 225.330 0.140 225.610 769.930 ;
      RECT 227.570 0.140 227.850 769.930 ;
      RECT 229.810 0.140 230.090 769.930 ;
      RECT 232.050 0.140 232.330 769.930 ;
      RECT 234.290 0.140 234.570 769.930 ;
      RECT 236.530 0.140 236.810 769.930 ;
      RECT 238.770 0.140 239.050 769.930 ;
      RECT 241.010 0.140 241.290 769.930 ;
      RECT 243.250 0.140 243.530 769.930 ;
      RECT 245.490 0.140 245.770 769.930 ;
      RECT 247.730 0.140 248.010 769.930 ;
      RECT 249.970 0.140 250.250 769.930 ;
      RECT 252.210 0.140 252.490 769.930 ;
      RECT 254.450 0.140 254.730 769.930 ;
      RECT 256.690 0.140 256.970 769.930 ;
      RECT 258.930 0.140 259.210 769.930 ;
      RECT 261.170 0.140 261.450 769.930 ;
      RECT 263.410 0.140 263.690 769.930 ;
      RECT 265.650 0.140 265.930 769.930 ;
      RECT 267.890 0.140 268.170 769.930 ;
      RECT 270.130 0.140 270.410 769.930 ;
      RECT 272.370 0.140 272.650 769.930 ;
      RECT 274.610 0.140 274.890 769.930 ;
      RECT 276.850 0.140 277.130 769.930 ;
      RECT 279.090 0.140 279.370 769.930 ;
      RECT 281.330 0.140 281.610 769.930 ;
      RECT 283.570 0.140 283.850 769.930 ;
      RECT 285.810 0.140 286.090 769.930 ;
      RECT 288.050 0.140 288.330 769.930 ;
      RECT 290.290 0.140 290.570 769.930 ;
      RECT 292.530 0.140 292.810 769.930 ;
      RECT 294.770 0.140 295.050 769.930 ;
      RECT 297.010 0.140 297.290 769.930 ;
      RECT 299.250 0.140 299.530 769.930 ;
      RECT 301.490 0.140 301.770 769.930 ;
      RECT 303.730 0.140 304.010 769.930 ;
      RECT 305.970 0.140 306.250 769.930 ;
      RECT 308.210 0.140 308.490 769.930 ;
      RECT 310.450 0.140 310.730 769.930 ;
      RECT 312.690 0.140 312.970 769.930 ;
      RECT 314.930 0.140 315.210 769.930 ;
      RECT 317.170 0.140 317.450 769.930 ;
      RECT 319.410 0.140 319.690 769.930 ;
      RECT 321.650 0.140 321.930 769.930 ;
      RECT 323.890 0.140 324.170 769.930 ;
      RECT 326.130 0.140 326.410 769.930 ;
      RECT 328.370 0.140 328.650 769.930 ;
      RECT 330.610 0.140 330.890 769.930 ;
      RECT 332.850 0.140 333.130 769.930 ;
      RECT 335.090 0.140 335.370 769.930 ;
      RECT 337.330 0.140 337.610 769.930 ;
      RECT 339.570 0.140 339.850 769.930 ;
      RECT 341.810 0.140 342.090 769.930 ;
      RECT 344.050 0.140 344.330 769.930 ;
      RECT 346.290 0.140 346.570 769.930 ;
      RECT 348.530 0.140 348.810 769.930 ;
      RECT 350.770 0.140 351.050 769.930 ;
      RECT 353.010 0.140 353.290 769.930 ;
      RECT 355.250 0.140 355.530 769.930 ;
      RECT 357.490 0.140 357.770 769.930 ;
      RECT 359.730 0.140 360.010 769.930 ;
      RECT 361.970 0.140 362.250 769.930 ;
      RECT 364.210 0.140 364.490 769.930 ;
      RECT 366.450 0.140 366.730 769.930 ;
      RECT 368.690 0.140 368.970 769.930 ;
      RECT 370.930 0.140 371.210 769.930 ;
      RECT 373.170 0.140 373.450 769.930 ;
      RECT 375.410 0.140 375.690 769.930 ;
      RECT 377.650 0.140 377.930 769.930 ;
      RECT 379.890 0.140 380.170 769.930 ;
      RECT 382.130 0.140 382.410 769.930 ;
      RECT 384.370 0.140 384.650 769.930 ;
      RECT 386.610 0.140 386.890 769.930 ;
      RECT 388.850 0.140 389.130 769.930 ;
      RECT 391.090 0.140 391.370 769.930 ;
      RECT 393.330 0.140 393.610 769.930 ;
      RECT 395.570 0.140 395.850 769.930 ;
      RECT 397.810 0.140 398.090 769.930 ;
      RECT 400.050 0.140 400.330 769.930 ;
      RECT 402.290 0.140 402.570 769.930 ;
      RECT 404.530 0.140 404.810 769.930 ;
      RECT 406.770 0.140 407.050 769.930 ;
      RECT 409.010 0.140 409.290 769.930 ;
      RECT 411.250 0.140 411.530 769.930 ;
      RECT 413.490 0.140 413.770 769.930 ;
      RECT 415.730 0.140 416.010 769.930 ;
      RECT 417.970 0.140 418.250 769.930 ;
      RECT 420.210 0.140 420.490 769.930 ;
      RECT 422.450 0.140 422.730 769.930 ;
      RECT 424.690 0.140 424.970 769.930 ;
      RECT 426.930 0.140 427.210 769.930 ;
      RECT 429.170 0.140 429.450 769.930 ;
      RECT 431.410 0.140 431.690 769.930 ;
      RECT 433.650 0.140 433.930 769.930 ;
      RECT 435.890 0.140 436.170 769.930 ;
      RECT 438.130 0.140 438.410 769.930 ;
      RECT 440.370 0.140 440.650 769.930 ;
      RECT 442.610 0.140 442.890 769.930 ;
      RECT 444.850 0.140 445.130 769.930 ;
      RECT 447.090 0.140 447.370 769.930 ;
      RECT 449.330 0.140 449.610 769.930 ;
      RECT 451.570 0.140 451.850 769.930 ;
      RECT 453.810 0.140 454.090 769.930 ;
      RECT 456.050 0.140 456.330 769.930 ;
      RECT 458.290 0.140 458.570 769.930 ;
      RECT 460.530 0.140 460.810 769.930 ;
      RECT 462.770 0.140 463.050 769.930 ;
      RECT 465.010 0.140 465.290 769.930 ;
      RECT 467.250 0.140 467.530 769.930 ;
      RECT 469.490 0.140 469.770 769.930 ;
      RECT 471.730 0.140 472.010 769.930 ;
      RECT 473.970 0.140 474.250 769.930 ;
      RECT 476.210 0.140 476.490 769.930 ;
      RECT 478.450 0.140 478.730 769.930 ;
      RECT 480.690 0.140 480.970 769.930 ;
      RECT 482.930 0.140 483.210 769.930 ;
      RECT 485.170 0.140 485.450 769.930 ;
      RECT 487.410 0.140 487.690 769.930 ;
      RECT 489.650 0.140 489.930 769.930 ;
      RECT 491.890 0.140 492.170 769.930 ;
      RECT 494.130 0.140 494.410 769.930 ;
      RECT 496.370 0.140 496.650 769.930 ;
      RECT 498.610 0.140 498.890 769.930 ;
      RECT 500.850 0.140 501.130 769.930 ;
      RECT 503.090 0.140 503.370 769.930 ;
      RECT 505.330 0.140 505.610 769.930 ;
      RECT 507.570 0.140 507.850 769.930 ;
      RECT 509.810 0.140 510.090 769.930 ;
      RECT 512.050 0.140 512.330 769.930 ;
      RECT 514.290 0.140 514.570 769.930 ;
      RECT 516.530 0.140 516.810 769.930 ;
      RECT 518.770 0.140 519.050 769.930 ;
      RECT 521.010 0.140 521.290 769.930 ;
      RECT 523.250 0.140 523.530 769.930 ;
      RECT 525.490 0.140 525.770 769.930 ;
      RECT 527.730 0.140 528.010 769.930 ;
      RECT 529.970 0.140 530.250 769.930 ;
      RECT 532.210 0.140 532.490 769.930 ;
      RECT 534.450 0.140 534.730 769.930 ;
      RECT 536.690 0.140 536.970 769.930 ;
      RECT 538.930 0.140 539.210 769.930 ;
      RECT 541.170 0.140 541.450 769.930 ;
      RECT 543.410 0.140 543.690 769.930 ;
      RECT 545.650 0.140 545.930 769.930 ;
      RECT 547.890 0.140 548.170 769.930 ;
      RECT 550.130 0.140 550.410 769.930 ;
      RECT 552.370 0.140 552.650 769.930 ;
      RECT 554.610 0.140 554.890 769.930 ;
      RECT 556.850 0.140 557.130 769.930 ;
      RECT 559.090 0.140 559.370 769.930 ;
      RECT 561.330 0.140 561.610 769.930 ;
      RECT 563.570 0.140 563.850 769.930 ;
      RECT 565.810 0.140 566.090 769.930 ;
      RECT 568.050 0.140 568.330 769.930 ;
      RECT 570.290 0.140 570.570 769.930 ;
      RECT 572.530 0.140 572.810 769.930 ;
      RECT 574.770 0.140 575.050 769.930 ;
      RECT 577.010 0.140 577.290 769.930 ;
      RECT 579.250 0.140 579.530 769.930 ;
      RECT 581.490 0.140 581.770 769.930 ;
      RECT 583.730 0.140 584.010 769.930 ;
      RECT 585.970 0.140 586.250 769.930 ;
      RECT 588.210 0.140 588.490 769.930 ;
      RECT 590.450 0.140 590.730 769.930 ;
      RECT 592.690 0.140 592.970 769.930 ;
      RECT 594.930 0.140 595.210 769.930 ;
      RECT 597.170 0.140 597.450 769.930 ;
      RECT 599.410 0.140 599.690 769.930 ;
      RECT 601.650 0.140 601.930 769.930 ;
      RECT 603.890 0.140 604.170 769.930 ;
      RECT 606.130 0.140 606.410 769.930 ;
      RECT 608.370 0.140 608.650 769.930 ;
      RECT 610.610 0.140 610.890 769.930 ;
      RECT 612.850 0.140 613.130 769.930 ;
      RECT 615.090 0.140 615.370 769.930 ;
      RECT 617.330 0.140 617.610 769.930 ;
      RECT 619.570 0.140 619.850 769.930 ;
      RECT 621.810 0.140 622.090 769.930 ;
      RECT 624.050 0.140 624.330 769.930 ;
      RECT 626.290 0.140 626.570 769.930 ;
      RECT 628.530 0.140 628.810 769.930 ;
      RECT 630.770 0.140 631.050 769.930 ;
      RECT 633.010 0.140 633.290 769.930 ;
      RECT 635.250 0.140 635.530 769.930 ;
      RECT 637.490 0.140 637.770 769.930 ;
      RECT 639.730 0.140 640.010 769.930 ;
      RECT 641.970 0.140 642.250 769.930 ;
      RECT 644.210 0.140 644.490 769.930 ;
      RECT 646.450 0.140 646.730 769.930 ;
      RECT 648.690 0.140 648.970 769.930 ;
      RECT 650.930 0.140 651.210 769.930 ;
      RECT 653.170 0.140 653.450 769.930 ;
      RECT 655.410 0.140 655.690 769.930 ;
      RECT 657.650 0.140 657.930 769.930 ;
      RECT 659.890 0.140 660.170 769.930 ;
      RECT 662.130 0.140 662.410 769.930 ;
      RECT 664.370 0.140 664.650 769.930 ;
      RECT 666.610 0.140 666.890 769.930 ;
      RECT 668.850 0.140 669.130 769.930 ;
      RECT 671.090 0.140 671.370 769.930 ;
      RECT 673.330 0.140 673.610 769.930 ;
      RECT 675.570 0.140 675.850 769.930 ;
      RECT 677.810 0.140 678.090 769.930 ;
      RECT 680.050 0.140 680.330 769.930 ;
      RECT 682.290 0.140 682.570 769.930 ;
      RECT 684.530 0.140 684.810 769.930 ;
      RECT 686.770 0.140 687.050 769.930 ;
      RECT 689.010 0.140 689.290 769.930 ;
    END
  END VDD
  OBS
    LAYER metal1 ;
    RECT 0 0 690.340 770.070 ;
    LAYER metal2 ;
    RECT 0 0 690.340 770.070 ;
    LAYER metal3 ;
    RECT 0 0 690.340 770.070 ;
    LAYER metal4 ;
    RECT 0 0 690.340 770.070 ;
    LAYER OVERLAP ;
    RECT 0 0 690.340 770.070 ;
  END
END fakeram_512x256_1r1w

END LIBRARY
